# Generated by FakeRAM 2.0
VERSION 5.7 ;
BUSBITCHARS "[]" ;
PROPERTYDEFINITIONS
  MACRO width INTEGER ;
  MACRO depth INTEGER ;
  MACRO banks INTEGER ;
END PROPERTYDEFINITIONS
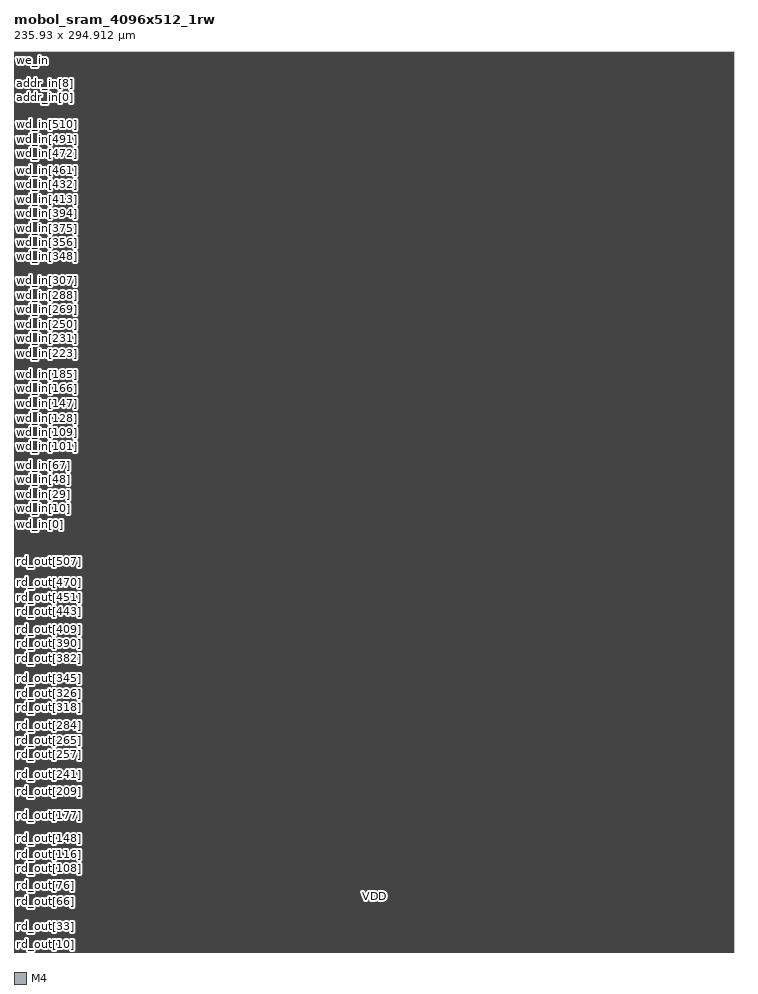
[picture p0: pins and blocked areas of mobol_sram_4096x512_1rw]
MACRO mobol_sram_4096x512_1rw
  PROPERTY width 512 ;
  PROPERTY depth 4096 ;
  PROPERTY banks 4 ;
  FOREIGN mobol_sram_4096x512_1rw 0 0 ;
  SYMMETRY X Y R90 ;
  SIZE 235.930 BY 294.912 ;
  CLASS BLOCK ;
  PIN rd_out[0]
    DIRECTION OUTPUT ;
    USE SIGNAL ;
    SHAPE ABUTMENT ;
    PORT
      LAYER M4 ;
      RECT 0.000 0.035 0.018 0.053 ;
    END
  END rd_out[0]
  PIN rd_out[1]
    DIRECTION OUTPUT ;
    USE SIGNAL ;
    SHAPE ABUTMENT ;
    PORT
      LAYER M4 ;
      RECT 0.000 0.287 0.018 0.305 ;
    END
  END rd_out[1]
  PIN rd_out[2]
    DIRECTION OUTPUT ;
    USE SIGNAL ;
    SHAPE ABUTMENT ;
    PORT
      LAYER M4 ;
      RECT 0.000 0.539 0.018 0.557 ;
    END
  END rd_out[2]
  PIN rd_out[3]
    DIRECTION OUTPUT ;
    USE SIGNAL ;
    SHAPE ABUTMENT ;
    PORT
      LAYER M4 ;
      RECT 0.000 0.791 0.018 0.809 ;
    END
  END rd_out[3]
  PIN rd_out[4]
    DIRECTION OUTPUT ;
    USE SIGNAL ;
    SHAPE ABUTMENT ;
    PORT
      LAYER M4 ;
      RECT 0.000 1.043 0.018 1.061 ;
    END
  END rd_out[4]
  PIN rd_out[5]
    DIRECTION OUTPUT ;
    USE SIGNAL ;
    SHAPE ABUTMENT ;
    PORT
      LAYER M4 ;
      RECT 0.000 1.295 0.018 1.313 ;
    END
  END rd_out[5]
  PIN rd_out[6]
    DIRECTION OUTPUT ;
    USE SIGNAL ;
    SHAPE ABUTMENT ;
    PORT
      LAYER M4 ;
      RECT 0.000 1.547 0.018 1.565 ;
    END
  END rd_out[6]
  PIN rd_out[7]
    DIRECTION OUTPUT ;
    USE SIGNAL ;
    SHAPE ABUTMENT ;
    PORT
      LAYER M4 ;
      RECT 0.000 1.799 0.018 1.817 ;
    END
  END rd_out[7]
  PIN rd_out[8]
    DIRECTION OUTPUT ;
    USE SIGNAL ;
    SHAPE ABUTMENT ;
    PORT
      LAYER M4 ;
      RECT 0.000 2.051 0.018 2.069 ;
    END
  END rd_out[8]
  PIN rd_out[9]
    DIRECTION OUTPUT ;
    USE SIGNAL ;
    SHAPE ABUTMENT ;
    PORT
      LAYER M4 ;
      RECT 0.000 2.303 0.018 2.321 ;
    END
  END rd_out[9]
  PIN rd_out[10]
    DIRECTION OUTPUT ;
    USE SIGNAL ;
    SHAPE ABUTMENT ;
    PORT
      LAYER M4 ;
      RECT 0.000 2.555 0.018 2.573 ;
    END
  END rd_out[10]
  PIN rd_out[11]
    DIRECTION OUTPUT ;
    USE SIGNAL ;
    SHAPE ABUTMENT ;
    PORT
      LAYER M4 ;
      RECT 0.000 2.807 0.018 2.825 ;
    END
  END rd_out[11]
  PIN rd_out[12]
    DIRECTION OUTPUT ;
    USE SIGNAL ;
    SHAPE ABUTMENT ;
    PORT
      LAYER M4 ;
      RECT 0.000 3.059 0.018 3.077 ;
    END
  END rd_out[12]
  PIN rd_out[13]
    DIRECTION OUTPUT ;
    USE SIGNAL ;
    SHAPE ABUTMENT ;
    PORT
      LAYER M4 ;
      RECT 0.000 3.311 0.018 3.329 ;
    END
  END rd_out[13]
  PIN rd_out[14]
    DIRECTION OUTPUT ;
    USE SIGNAL ;
    SHAPE ABUTMENT ;
    PORT
      LAYER M4 ;
      RECT 0.000 3.563 0.018 3.581 ;
    END
  END rd_out[14]
  PIN rd_out[15]
    DIRECTION OUTPUT ;
    USE SIGNAL ;
    SHAPE ABUTMENT ;
    PORT
      LAYER M4 ;
      RECT 0.000 3.815 0.018 3.833 ;
    END
  END rd_out[15]
  PIN rd_out[16]
    DIRECTION OUTPUT ;
    USE SIGNAL ;
    SHAPE ABUTMENT ;
    PORT
      LAYER M4 ;
      RECT 0.000 4.067 0.018 4.085 ;
    END
  END rd_out[16]
  PIN rd_out[17]
    DIRECTION OUTPUT ;
    USE SIGNAL ;
    SHAPE ABUTMENT ;
    PORT
      LAYER M4 ;
      RECT 0.000 4.319 0.018 4.337 ;
    END
  END rd_out[17]
  PIN rd_out[18]
    DIRECTION OUTPUT ;
    USE SIGNAL ;
    SHAPE ABUTMENT ;
    PORT
      LAYER M4 ;
      RECT 0.000 4.571 0.018 4.589 ;
    END
  END rd_out[18]
  PIN rd_out[19]
    DIRECTION OUTPUT ;
    USE SIGNAL ;
    SHAPE ABUTMENT ;
    PORT
      LAYER M4 ;
      RECT 0.000 4.823 0.018 4.841 ;
    END
  END rd_out[19]
  PIN rd_out[20]
    DIRECTION OUTPUT ;
    USE SIGNAL ;
    SHAPE ABUTMENT ;
    PORT
      LAYER M4 ;
      RECT 0.000 5.075 0.018 5.093 ;
    END
  END rd_out[20]
  PIN rd_out[21]
    DIRECTION OUTPUT ;
    USE SIGNAL ;
    SHAPE ABUTMENT ;
    PORT
      LAYER M4 ;
      RECT 0.000 5.327 0.018 5.345 ;
    END
  END rd_out[21]
  PIN rd_out[22]
    DIRECTION OUTPUT ;
    USE SIGNAL ;
    SHAPE ABUTMENT ;
    PORT
      LAYER M4 ;
      RECT 0.000 5.579 0.018 5.597 ;
    END
  END rd_out[22]
  PIN rd_out[23]
    DIRECTION OUTPUT ;
    USE SIGNAL ;
    SHAPE ABUTMENT ;
    PORT
      LAYER M4 ;
      RECT 0.000 5.831 0.018 5.849 ;
    END
  END rd_out[23]
  PIN rd_out[24]
    DIRECTION OUTPUT ;
    USE SIGNAL ;
    SHAPE ABUTMENT ;
    PORT
      LAYER M4 ;
      RECT 0.000 6.083 0.018 6.101 ;
    END
  END rd_out[24]
  PIN rd_out[25]
    DIRECTION OUTPUT ;
    USE SIGNAL ;
    SHAPE ABUTMENT ;
    PORT
      LAYER M4 ;
      RECT 0.000 6.335 0.018 6.353 ;
    END
  END rd_out[25]
  PIN rd_out[26]
    DIRECTION OUTPUT ;
    USE SIGNAL ;
    SHAPE ABUTMENT ;
    PORT
      LAYER M4 ;
      RECT 0.000 6.587 0.018 6.605 ;
    END
  END rd_out[26]
  PIN rd_out[27]
    DIRECTION OUTPUT ;
    USE SIGNAL ;
    SHAPE ABUTMENT ;
    PORT
      LAYER M4 ;
      RECT 0.000 6.839 0.018 6.857 ;
    END
  END rd_out[27]
  PIN rd_out[28]
    DIRECTION OUTPUT ;
    USE SIGNAL ;
    SHAPE ABUTMENT ;
    PORT
      LAYER M4 ;
      RECT 0.000 7.091 0.018 7.109 ;
    END
  END rd_out[28]
  PIN rd_out[29]
    DIRECTION OUTPUT ;
    USE SIGNAL ;
    SHAPE ABUTMENT ;
    PORT
      LAYER M4 ;
      RECT 0.000 7.343 0.018 7.361 ;
    END
  END rd_out[29]
  PIN rd_out[30]
    DIRECTION OUTPUT ;
    USE SIGNAL ;
    SHAPE ABUTMENT ;
    PORT
      LAYER M4 ;
      RECT 0.000 7.595 0.018 7.613 ;
    END
  END rd_out[30]
  PIN rd_out[31]
    DIRECTION OUTPUT ;
    USE SIGNAL ;
    SHAPE ABUTMENT ;
    PORT
      LAYER M4 ;
      RECT 0.000 7.847 0.018 7.865 ;
    END
  END rd_out[31]
  PIN rd_out[32]
    DIRECTION OUTPUT ;
    USE SIGNAL ;
    SHAPE ABUTMENT ;
    PORT
      LAYER M4 ;
      RECT 0.000 8.099 0.018 8.117 ;
    END
  END rd_out[32]
  PIN rd_out[33]
    DIRECTION OUTPUT ;
    USE SIGNAL ;
    SHAPE ABUTMENT ;
    PORT
      LAYER M4 ;
      RECT 0.000 8.351 0.018 8.369 ;
    END
  END rd_out[33]
  PIN rd_out[34]
    DIRECTION OUTPUT ;
    USE SIGNAL ;
    SHAPE ABUTMENT ;
    PORT
      LAYER M4 ;
      RECT 0.000 8.603 0.018 8.621 ;
    END
  END rd_out[34]
  PIN rd_out[35]
    DIRECTION OUTPUT ;
    USE SIGNAL ;
    SHAPE ABUTMENT ;
    PORT
      LAYER M4 ;
      RECT 0.000 8.855 0.018 8.873 ;
    END
  END rd_out[35]
  PIN rd_out[36]
    DIRECTION OUTPUT ;
    USE SIGNAL ;
    SHAPE ABUTMENT ;
    PORT
      LAYER M4 ;
      RECT 0.000 9.107 0.018 9.125 ;
    END
  END rd_out[36]
  PIN rd_out[37]
    DIRECTION OUTPUT ;
    USE SIGNAL ;
    SHAPE ABUTMENT ;
    PORT
      LAYER M4 ;
      RECT 0.000 9.359 0.018 9.377 ;
    END
  END rd_out[37]
  PIN rd_out[38]
    DIRECTION OUTPUT ;
    USE SIGNAL ;
    SHAPE ABUTMENT ;
    PORT
      LAYER M4 ;
      RECT 0.000 9.611 0.018 9.629 ;
    END
  END rd_out[38]
  PIN rd_out[39]
    DIRECTION OUTPUT ;
    USE SIGNAL ;
    SHAPE ABUTMENT ;
    PORT
      LAYER M4 ;
      RECT 0.000 9.863 0.018 9.881 ;
    END
  END rd_out[39]
  PIN rd_out[40]
    DIRECTION OUTPUT ;
    USE SIGNAL ;
    SHAPE ABUTMENT ;
    PORT
      LAYER M4 ;
      RECT 0.000 10.115 0.018 10.133 ;
    END
  END rd_out[40]
  PIN rd_out[41]
    DIRECTION OUTPUT ;
    USE SIGNAL ;
    SHAPE ABUTMENT ;
    PORT
      LAYER M4 ;
      RECT 0.000 10.367 0.018 10.385 ;
    END
  END rd_out[41]
  PIN rd_out[42]
    DIRECTION OUTPUT ;
    USE SIGNAL ;
    SHAPE ABUTMENT ;
    PORT
      LAYER M4 ;
      RECT 0.000 10.619 0.018 10.637 ;
    END
  END rd_out[42]
  PIN rd_out[43]
    DIRECTION OUTPUT ;
    USE SIGNAL ;
    SHAPE ABUTMENT ;
    PORT
      LAYER M4 ;
      RECT 0.000 10.871 0.018 10.889 ;
    END
  END rd_out[43]
  PIN rd_out[44]
    DIRECTION OUTPUT ;
    USE SIGNAL ;
    SHAPE ABUTMENT ;
    PORT
      LAYER M4 ;
      RECT 0.000 11.123 0.018 11.141 ;
    END
  END rd_out[44]
  PIN rd_out[45]
    DIRECTION OUTPUT ;
    USE SIGNAL ;
    SHAPE ABUTMENT ;
    PORT
      LAYER M4 ;
      RECT 0.000 11.375 0.018 11.393 ;
    END
  END rd_out[45]
  PIN rd_out[46]
    DIRECTION OUTPUT ;
    USE SIGNAL ;
    SHAPE ABUTMENT ;
    PORT
      LAYER M4 ;
      RECT 0.000 11.627 0.018 11.645 ;
    END
  END rd_out[46]
  PIN rd_out[47]
    DIRECTION OUTPUT ;
    USE SIGNAL ;
    SHAPE ABUTMENT ;
    PORT
      LAYER M4 ;
      RECT 0.000 11.879 0.018 11.897 ;
    END
  END rd_out[47]
  PIN rd_out[48]
    DIRECTION OUTPUT ;
    USE SIGNAL ;
    SHAPE ABUTMENT ;
    PORT
      LAYER M4 ;
      RECT 0.000 12.131 0.018 12.149 ;
    END
  END rd_out[48]
  PIN rd_out[49]
    DIRECTION OUTPUT ;
    USE SIGNAL ;
    SHAPE ABUTMENT ;
    PORT
      LAYER M4 ;
      RECT 0.000 12.383 0.018 12.401 ;
    END
  END rd_out[49]
  PIN rd_out[50]
    DIRECTION OUTPUT ;
    USE SIGNAL ;
    SHAPE ABUTMENT ;
    PORT
      LAYER M4 ;
      RECT 0.000 12.635 0.018 12.653 ;
    END
  END rd_out[50]
  PIN rd_out[51]
    DIRECTION OUTPUT ;
    USE SIGNAL ;
    SHAPE ABUTMENT ;
    PORT
      LAYER M4 ;
      RECT 0.000 12.887 0.018 12.905 ;
    END
  END rd_out[51]
  PIN rd_out[52]
    DIRECTION OUTPUT ;
    USE SIGNAL ;
    SHAPE ABUTMENT ;
    PORT
      LAYER M4 ;
      RECT 0.000 13.139 0.018 13.157 ;
    END
  END rd_out[52]
  PIN rd_out[53]
    DIRECTION OUTPUT ;
    USE SIGNAL ;
    SHAPE ABUTMENT ;
    PORT
      LAYER M4 ;
      RECT 0.000 13.391 0.018 13.409 ;
    END
  END rd_out[53]
  PIN rd_out[54]
    DIRECTION OUTPUT ;
    USE SIGNAL ;
    SHAPE ABUTMENT ;
    PORT
      LAYER M4 ;
      RECT 0.000 13.643 0.018 13.661 ;
    END
  END rd_out[54]
  PIN rd_out[55]
    DIRECTION OUTPUT ;
    USE SIGNAL ;
    SHAPE ABUTMENT ;
    PORT
      LAYER M4 ;
      RECT 0.000 13.895 0.018 13.913 ;
    END
  END rd_out[55]
  PIN rd_out[56]
    DIRECTION OUTPUT ;
    USE SIGNAL ;
    SHAPE ABUTMENT ;
    PORT
      LAYER M4 ;
      RECT 0.000 14.147 0.018 14.165 ;
    END
  END rd_out[56]
  PIN rd_out[57]
    DIRECTION OUTPUT ;
    USE SIGNAL ;
    SHAPE ABUTMENT ;
    PORT
      LAYER M4 ;
      RECT 0.000 14.399 0.018 14.417 ;
    END
  END rd_out[57]
  PIN rd_out[58]
    DIRECTION OUTPUT ;
    USE SIGNAL ;
    SHAPE ABUTMENT ;
    PORT
      LAYER M4 ;
      RECT 0.000 14.651 0.018 14.669 ;
    END
  END rd_out[58]
  PIN rd_out[59]
    DIRECTION OUTPUT ;
    USE SIGNAL ;
    SHAPE ABUTMENT ;
    PORT
      LAYER M4 ;
      RECT 0.000 14.903 0.018 14.921 ;
    END
  END rd_out[59]
  PIN rd_out[60]
    DIRECTION OUTPUT ;
    USE SIGNAL ;
    SHAPE ABUTMENT ;
    PORT
      LAYER M4 ;
      RECT 0.000 15.155 0.018 15.173 ;
    END
  END rd_out[60]
  PIN rd_out[61]
    DIRECTION OUTPUT ;
    USE SIGNAL ;
    SHAPE ABUTMENT ;
    PORT
      LAYER M4 ;
      RECT 0.000 15.407 0.018 15.425 ;
    END
  END rd_out[61]
  PIN rd_out[62]
    DIRECTION OUTPUT ;
    USE SIGNAL ;
    SHAPE ABUTMENT ;
    PORT
      LAYER M4 ;
      RECT 0.000 15.659 0.018 15.677 ;
    END
  END rd_out[62]
  PIN rd_out[63]
    DIRECTION OUTPUT ;
    USE SIGNAL ;
    SHAPE ABUTMENT ;
    PORT
      LAYER M4 ;
      RECT 0.000 15.911 0.018 15.929 ;
    END
  END rd_out[63]
  PIN rd_out[64]
    DIRECTION OUTPUT ;
    USE SIGNAL ;
    SHAPE ABUTMENT ;
    PORT
      LAYER M4 ;
      RECT 0.000 16.163 0.018 16.181 ;
    END
  END rd_out[64]
  PIN rd_out[65]
    DIRECTION OUTPUT ;
    USE SIGNAL ;
    SHAPE ABUTMENT ;
    PORT
      LAYER M4 ;
      RECT 0.000 16.415 0.018 16.433 ;
    END
  END rd_out[65]
  PIN rd_out[66]
    DIRECTION OUTPUT ;
    USE SIGNAL ;
    SHAPE ABUTMENT ;
    PORT
      LAYER M4 ;
      RECT 0.000 16.667 0.018 16.685 ;
    END
  END rd_out[66]
  PIN rd_out[67]
    DIRECTION OUTPUT ;
    USE SIGNAL ;
    SHAPE ABUTMENT ;
    PORT
      LAYER M4 ;
      RECT 0.000 16.919 0.018 16.937 ;
    END
  END rd_out[67]
  PIN rd_out[68]
    DIRECTION OUTPUT ;
    USE SIGNAL ;
    SHAPE ABUTMENT ;
    PORT
      LAYER M4 ;
      RECT 0.000 17.171 0.018 17.189 ;
    END
  END rd_out[68]
  PIN rd_out[69]
    DIRECTION OUTPUT ;
    USE SIGNAL ;
    SHAPE ABUTMENT ;
    PORT
      LAYER M4 ;
      RECT 0.000 17.423 0.018 17.441 ;
    END
  END rd_out[69]
  PIN rd_out[70]
    DIRECTION OUTPUT ;
    USE SIGNAL ;
    SHAPE ABUTMENT ;
    PORT
      LAYER M4 ;
      RECT 0.000 17.675 0.018 17.693 ;
    END
  END rd_out[70]
  PIN rd_out[71]
    DIRECTION OUTPUT ;
    USE SIGNAL ;
    SHAPE ABUTMENT ;
    PORT
      LAYER M4 ;
      RECT 0.000 17.927 0.018 17.945 ;
    END
  END rd_out[71]
  PIN rd_out[72]
    DIRECTION OUTPUT ;
    USE SIGNAL ;
    SHAPE ABUTMENT ;
    PORT
      LAYER M4 ;
      RECT 0.000 18.179 0.018 18.197 ;
    END
  END rd_out[72]
  PIN rd_out[73]
    DIRECTION OUTPUT ;
    USE SIGNAL ;
    SHAPE ABUTMENT ;
    PORT
      LAYER M4 ;
      RECT 0.000 18.431 0.018 18.449 ;
    END
  END rd_out[73]
  PIN rd_out[74]
    DIRECTION OUTPUT ;
    USE SIGNAL ;
    SHAPE ABUTMENT ;
    PORT
      LAYER M4 ;
      RECT 0.000 18.683 0.018 18.701 ;
    END
  END rd_out[74]
  PIN rd_out[75]
    DIRECTION OUTPUT ;
    USE SIGNAL ;
    SHAPE ABUTMENT ;
    PORT
      LAYER M4 ;
      RECT 0.000 18.935 0.018 18.953 ;
    END
  END rd_out[75]
  PIN rd_out[76]
    DIRECTION OUTPUT ;
    USE SIGNAL ;
    SHAPE ABUTMENT ;
    PORT
      LAYER M4 ;
      RECT 0.000 19.187 0.018 19.205 ;
    END
  END rd_out[76]
  PIN rd_out[77]
    DIRECTION OUTPUT ;
    USE SIGNAL ;
    SHAPE ABUTMENT ;
    PORT
      LAYER M4 ;
      RECT 0.000 19.439 0.018 19.457 ;
    END
  END rd_out[77]
  PIN rd_out[78]
    DIRECTION OUTPUT ;
    USE SIGNAL ;
    SHAPE ABUTMENT ;
    PORT
      LAYER M4 ;
      RECT 0.000 19.691 0.018 19.709 ;
    END
  END rd_out[78]
  PIN rd_out[79]
    DIRECTION OUTPUT ;
    USE SIGNAL ;
    SHAPE ABUTMENT ;
    PORT
      LAYER M4 ;
      RECT 0.000 19.943 0.018 19.961 ;
    END
  END rd_out[79]
  PIN rd_out[80]
    DIRECTION OUTPUT ;
    USE SIGNAL ;
    SHAPE ABUTMENT ;
    PORT
      LAYER M4 ;
      RECT 0.000 20.195 0.018 20.213 ;
    END
  END rd_out[80]
  PIN rd_out[81]
    DIRECTION OUTPUT ;
    USE SIGNAL ;
    SHAPE ABUTMENT ;
    PORT
      LAYER M4 ;
      RECT 0.000 20.447 0.018 20.465 ;
    END
  END rd_out[81]
  PIN rd_out[82]
    DIRECTION OUTPUT ;
    USE SIGNAL ;
    SHAPE ABUTMENT ;
    PORT
      LAYER M4 ;
      RECT 0.000 20.699 0.018 20.717 ;
    END
  END rd_out[82]
  PIN rd_out[83]
    DIRECTION OUTPUT ;
    USE SIGNAL ;
    SHAPE ABUTMENT ;
    PORT
      LAYER M4 ;
      RECT 0.000 20.951 0.018 20.969 ;
    END
  END rd_out[83]
  PIN rd_out[84]
    DIRECTION OUTPUT ;
    USE SIGNAL ;
    SHAPE ABUTMENT ;
    PORT
      LAYER M4 ;
      RECT 0.000 21.203 0.018 21.221 ;
    END
  END rd_out[84]
  PIN rd_out[85]
    DIRECTION OUTPUT ;
    USE SIGNAL ;
    SHAPE ABUTMENT ;
    PORT
      LAYER M4 ;
      RECT 0.000 21.455 0.018 21.473 ;
    END
  END rd_out[85]
  PIN rd_out[86]
    DIRECTION OUTPUT ;
    USE SIGNAL ;
    SHAPE ABUTMENT ;
    PORT
      LAYER M4 ;
      RECT 0.000 21.707 0.018 21.725 ;
    END
  END rd_out[86]
  PIN rd_out[87]
    DIRECTION OUTPUT ;
    USE SIGNAL ;
    SHAPE ABUTMENT ;
    PORT
      LAYER M4 ;
      RECT 0.000 21.959 0.018 21.977 ;
    END
  END rd_out[87]
  PIN rd_out[88]
    DIRECTION OUTPUT ;
    USE SIGNAL ;
    SHAPE ABUTMENT ;
    PORT
      LAYER M4 ;
      RECT 0.000 22.211 0.018 22.229 ;
    END
  END rd_out[88]
  PIN rd_out[89]
    DIRECTION OUTPUT ;
    USE SIGNAL ;
    SHAPE ABUTMENT ;
    PORT
      LAYER M4 ;
      RECT 0.000 22.463 0.018 22.481 ;
    END
  END rd_out[89]
  PIN rd_out[90]
    DIRECTION OUTPUT ;
    USE SIGNAL ;
    SHAPE ABUTMENT ;
    PORT
      LAYER M4 ;
      RECT 0.000 22.715 0.018 22.733 ;
    END
  END rd_out[90]
  PIN rd_out[91]
    DIRECTION OUTPUT ;
    USE SIGNAL ;
    SHAPE ABUTMENT ;
    PORT
      LAYER M4 ;
      RECT 0.000 22.967 0.018 22.985 ;
    END
  END rd_out[91]
  PIN rd_out[92]
    DIRECTION OUTPUT ;
    USE SIGNAL ;
    SHAPE ABUTMENT ;
    PORT
      LAYER M4 ;
      RECT 0.000 23.219 0.018 23.237 ;
    END
  END rd_out[92]
  PIN rd_out[93]
    DIRECTION OUTPUT ;
    USE SIGNAL ;
    SHAPE ABUTMENT ;
    PORT
      LAYER M4 ;
      RECT 0.000 23.471 0.018 23.489 ;
    END
  END rd_out[93]
  PIN rd_out[94]
    DIRECTION OUTPUT ;
    USE SIGNAL ;
    SHAPE ABUTMENT ;
    PORT
      LAYER M4 ;
      RECT 0.000 23.723 0.018 23.741 ;
    END
  END rd_out[94]
  PIN rd_out[95]
    DIRECTION OUTPUT ;
    USE SIGNAL ;
    SHAPE ABUTMENT ;
    PORT
      LAYER M4 ;
      RECT 0.000 23.975 0.018 23.993 ;
    END
  END rd_out[95]
  PIN rd_out[96]
    DIRECTION OUTPUT ;
    USE SIGNAL ;
    SHAPE ABUTMENT ;
    PORT
      LAYER M4 ;
      RECT 0.000 24.227 0.018 24.245 ;
    END
  END rd_out[96]
  PIN rd_out[97]
    DIRECTION OUTPUT ;
    USE SIGNAL ;
    SHAPE ABUTMENT ;
    PORT
      LAYER M4 ;
      RECT 0.000 24.479 0.018 24.497 ;
    END
  END rd_out[97]
  PIN rd_out[98]
    DIRECTION OUTPUT ;
    USE SIGNAL ;
    SHAPE ABUTMENT ;
    PORT
      LAYER M4 ;
      RECT 0.000 24.731 0.018 24.749 ;
    END
  END rd_out[98]
  PIN rd_out[99]
    DIRECTION OUTPUT ;
    USE SIGNAL ;
    SHAPE ABUTMENT ;
    PORT
      LAYER M4 ;
      RECT 0.000 24.983 0.018 25.001 ;
    END
  END rd_out[99]
  PIN rd_out[100]
    DIRECTION OUTPUT ;
    USE SIGNAL ;
    SHAPE ABUTMENT ;
    PORT
      LAYER M4 ;
      RECT 0.000 25.235 0.018 25.253 ;
    END
  END rd_out[100]
  PIN rd_out[101]
    DIRECTION OUTPUT ;
    USE SIGNAL ;
    SHAPE ABUTMENT ;
    PORT
      LAYER M4 ;
      RECT 0.000 25.487 0.018 25.505 ;
    END
  END rd_out[101]
  PIN rd_out[102]
    DIRECTION OUTPUT ;
    USE SIGNAL ;
    SHAPE ABUTMENT ;
    PORT
      LAYER M4 ;
      RECT 0.000 25.739 0.018 25.757 ;
    END
  END rd_out[102]
  PIN rd_out[103]
    DIRECTION OUTPUT ;
    USE SIGNAL ;
    SHAPE ABUTMENT ;
    PORT
      LAYER M4 ;
      RECT 0.000 25.991 0.018 26.009 ;
    END
  END rd_out[103]
  PIN rd_out[104]
    DIRECTION OUTPUT ;
    USE SIGNAL ;
    SHAPE ABUTMENT ;
    PORT
      LAYER M4 ;
      RECT 0.000 26.243 0.018 26.261 ;
    END
  END rd_out[104]
  PIN rd_out[105]
    DIRECTION OUTPUT ;
    USE SIGNAL ;
    SHAPE ABUTMENT ;
    PORT
      LAYER M4 ;
      RECT 0.000 26.495 0.018 26.513 ;
    END
  END rd_out[105]
  PIN rd_out[106]
    DIRECTION OUTPUT ;
    USE SIGNAL ;
    SHAPE ABUTMENT ;
    PORT
      LAYER M4 ;
      RECT 0.000 26.747 0.018 26.765 ;
    END
  END rd_out[106]
  PIN rd_out[107]
    DIRECTION OUTPUT ;
    USE SIGNAL ;
    SHAPE ABUTMENT ;
    PORT
      LAYER M4 ;
      RECT 0.000 26.999 0.018 27.017 ;
    END
  END rd_out[107]
  PIN rd_out[108]
    DIRECTION OUTPUT ;
    USE SIGNAL ;
    SHAPE ABUTMENT ;
    PORT
      LAYER M4 ;
      RECT 0.000 27.251 0.018 27.269 ;
    END
  END rd_out[108]
  PIN rd_out[109]
    DIRECTION OUTPUT ;
    USE SIGNAL ;
    SHAPE ABUTMENT ;
    PORT
      LAYER M4 ;
      RECT 0.000 27.503 0.018 27.521 ;
    END
  END rd_out[109]
  PIN rd_out[110]
    DIRECTION OUTPUT ;
    USE SIGNAL ;
    SHAPE ABUTMENT ;
    PORT
      LAYER M4 ;
      RECT 0.000 27.755 0.018 27.773 ;
    END
  END rd_out[110]
  PIN rd_out[111]
    DIRECTION OUTPUT ;
    USE SIGNAL ;
    SHAPE ABUTMENT ;
    PORT
      LAYER M4 ;
      RECT 0.000 28.007 0.018 28.025 ;
    END
  END rd_out[111]
  PIN rd_out[112]
    DIRECTION OUTPUT ;
    USE SIGNAL ;
    SHAPE ABUTMENT ;
    PORT
      LAYER M4 ;
      RECT 0.000 28.259 0.018 28.277 ;
    END
  END rd_out[112]
  PIN rd_out[113]
    DIRECTION OUTPUT ;
    USE SIGNAL ;
    SHAPE ABUTMENT ;
    PORT
      LAYER M4 ;
      RECT 0.000 28.511 0.018 28.529 ;
    END
  END rd_out[113]
  PIN rd_out[114]
    DIRECTION OUTPUT ;
    USE SIGNAL ;
    SHAPE ABUTMENT ;
    PORT
      LAYER M4 ;
      RECT 0.000 28.763 0.018 28.781 ;
    END
  END rd_out[114]
  PIN rd_out[115]
    DIRECTION OUTPUT ;
    USE SIGNAL ;
    SHAPE ABUTMENT ;
    PORT
      LAYER M4 ;
      RECT 0.000 29.015 0.018 29.033 ;
    END
  END rd_out[115]
  PIN rd_out[116]
    DIRECTION OUTPUT ;
    USE SIGNAL ;
    SHAPE ABUTMENT ;
    PORT
      LAYER M4 ;
      RECT 0.000 29.267 0.018 29.285 ;
    END
  END rd_out[116]
  PIN rd_out[117]
    DIRECTION OUTPUT ;
    USE SIGNAL ;
    SHAPE ABUTMENT ;
    PORT
      LAYER M4 ;
      RECT 0.000 29.519 0.018 29.537 ;
    END
  END rd_out[117]
  PIN rd_out[118]
    DIRECTION OUTPUT ;
    USE SIGNAL ;
    SHAPE ABUTMENT ;
    PORT
      LAYER M4 ;
      RECT 0.000 29.771 0.018 29.789 ;
    END
  END rd_out[118]
  PIN rd_out[119]
    DIRECTION OUTPUT ;
    USE SIGNAL ;
    SHAPE ABUTMENT ;
    PORT
      LAYER M4 ;
      RECT 0.000 30.023 0.018 30.041 ;
    END
  END rd_out[119]
  PIN rd_out[120]
    DIRECTION OUTPUT ;
    USE SIGNAL ;
    SHAPE ABUTMENT ;
    PORT
      LAYER M4 ;
      RECT 0.000 30.275 0.018 30.293 ;
    END
  END rd_out[120]
  PIN rd_out[121]
    DIRECTION OUTPUT ;
    USE SIGNAL ;
    SHAPE ABUTMENT ;
    PORT
      LAYER M4 ;
      RECT 0.000 30.527 0.018 30.545 ;
    END
  END rd_out[121]
  PIN rd_out[122]
    DIRECTION OUTPUT ;
    USE SIGNAL ;
    SHAPE ABUTMENT ;
    PORT
      LAYER M4 ;
      RECT 0.000 30.779 0.018 30.797 ;
    END
  END rd_out[122]
  PIN rd_out[123]
    DIRECTION OUTPUT ;
    USE SIGNAL ;
    SHAPE ABUTMENT ;
    PORT
      LAYER M4 ;
      RECT 0.000 31.031 0.018 31.049 ;
    END
  END rd_out[123]
  PIN rd_out[124]
    DIRECTION OUTPUT ;
    USE SIGNAL ;
    SHAPE ABUTMENT ;
    PORT
      LAYER M4 ;
      RECT 0.000 31.283 0.018 31.301 ;
    END
  END rd_out[124]
  PIN rd_out[125]
    DIRECTION OUTPUT ;
    USE SIGNAL ;
    SHAPE ABUTMENT ;
    PORT
      LAYER M4 ;
      RECT 0.000 31.535 0.018 31.553 ;
    END
  END rd_out[125]
  PIN rd_out[126]
    DIRECTION OUTPUT ;
    USE SIGNAL ;
    SHAPE ABUTMENT ;
    PORT
      LAYER M4 ;
      RECT 0.000 31.787 0.018 31.805 ;
    END
  END rd_out[126]
  PIN rd_out[127]
    DIRECTION OUTPUT ;
    USE SIGNAL ;
    SHAPE ABUTMENT ;
    PORT
      LAYER M4 ;
      RECT 0.000 32.039 0.018 32.057 ;
    END
  END rd_out[127]
  PIN rd_out[128]
    DIRECTION OUTPUT ;
    USE SIGNAL ;
    SHAPE ABUTMENT ;
    PORT
      LAYER M4 ;
      RECT 0.000 32.291 0.018 32.309 ;
    END
  END rd_out[128]
  PIN rd_out[129]
    DIRECTION OUTPUT ;
    USE SIGNAL ;
    SHAPE ABUTMENT ;
    PORT
      LAYER M4 ;
      RECT 0.000 32.543 0.018 32.561 ;
    END
  END rd_out[129]
  PIN rd_out[130]
    DIRECTION OUTPUT ;
    USE SIGNAL ;
    SHAPE ABUTMENT ;
    PORT
      LAYER M4 ;
      RECT 0.000 32.795 0.018 32.813 ;
    END
  END rd_out[130]
  PIN rd_out[131]
    DIRECTION OUTPUT ;
    USE SIGNAL ;
    SHAPE ABUTMENT ;
    PORT
      LAYER M4 ;
      RECT 0.000 33.047 0.018 33.065 ;
    END
  END rd_out[131]
  PIN rd_out[132]
    DIRECTION OUTPUT ;
    USE SIGNAL ;
    SHAPE ABUTMENT ;
    PORT
      LAYER M4 ;
      RECT 0.000 33.299 0.018 33.317 ;
    END
  END rd_out[132]
  PIN rd_out[133]
    DIRECTION OUTPUT ;
    USE SIGNAL ;
    SHAPE ABUTMENT ;
    PORT
      LAYER M4 ;
      RECT 0.000 33.551 0.018 33.569 ;
    END
  END rd_out[133]
  PIN rd_out[134]
    DIRECTION OUTPUT ;
    USE SIGNAL ;
    SHAPE ABUTMENT ;
    PORT
      LAYER M4 ;
      RECT 0.000 33.803 0.018 33.821 ;
    END
  END rd_out[134]
  PIN rd_out[135]
    DIRECTION OUTPUT ;
    USE SIGNAL ;
    SHAPE ABUTMENT ;
    PORT
      LAYER M4 ;
      RECT 0.000 34.055 0.018 34.073 ;
    END
  END rd_out[135]
  PIN rd_out[136]
    DIRECTION OUTPUT ;
    USE SIGNAL ;
    SHAPE ABUTMENT ;
    PORT
      LAYER M4 ;
      RECT 0.000 34.307 0.018 34.325 ;
    END
  END rd_out[136]
  PIN rd_out[137]
    DIRECTION OUTPUT ;
    USE SIGNAL ;
    SHAPE ABUTMENT ;
    PORT
      LAYER M4 ;
      RECT 0.000 34.559 0.018 34.577 ;
    END
  END rd_out[137]
  PIN rd_out[138]
    DIRECTION OUTPUT ;
    USE SIGNAL ;
    SHAPE ABUTMENT ;
    PORT
      LAYER M4 ;
      RECT 0.000 34.811 0.018 34.829 ;
    END
  END rd_out[138]
  PIN rd_out[139]
    DIRECTION OUTPUT ;
    USE SIGNAL ;
    SHAPE ABUTMENT ;
    PORT
      LAYER M4 ;
      RECT 0.000 35.063 0.018 35.081 ;
    END
  END rd_out[139]
  PIN rd_out[140]
    DIRECTION OUTPUT ;
    USE SIGNAL ;
    SHAPE ABUTMENT ;
    PORT
      LAYER M4 ;
      RECT 0.000 35.315 0.018 35.333 ;
    END
  END rd_out[140]
  PIN rd_out[141]
    DIRECTION OUTPUT ;
    USE SIGNAL ;
    SHAPE ABUTMENT ;
    PORT
      LAYER M4 ;
      RECT 0.000 35.567 0.018 35.585 ;
    END
  END rd_out[141]
  PIN rd_out[142]
    DIRECTION OUTPUT ;
    USE SIGNAL ;
    SHAPE ABUTMENT ;
    PORT
      LAYER M4 ;
      RECT 0.000 35.819 0.018 35.837 ;
    END
  END rd_out[142]
  PIN rd_out[143]
    DIRECTION OUTPUT ;
    USE SIGNAL ;
    SHAPE ABUTMENT ;
    PORT
      LAYER M4 ;
      RECT 0.000 36.071 0.018 36.089 ;
    END
  END rd_out[143]
  PIN rd_out[144]
    DIRECTION OUTPUT ;
    USE SIGNAL ;
    SHAPE ABUTMENT ;
    PORT
      LAYER M4 ;
      RECT 0.000 36.323 0.018 36.341 ;
    END
  END rd_out[144]
  PIN rd_out[145]
    DIRECTION OUTPUT ;
    USE SIGNAL ;
    SHAPE ABUTMENT ;
    PORT
      LAYER M4 ;
      RECT 0.000 36.575 0.018 36.593 ;
    END
  END rd_out[145]
  PIN rd_out[146]
    DIRECTION OUTPUT ;
    USE SIGNAL ;
    SHAPE ABUTMENT ;
    PORT
      LAYER M4 ;
      RECT 0.000 36.827 0.018 36.845 ;
    END
  END rd_out[146]
  PIN rd_out[147]
    DIRECTION OUTPUT ;
    USE SIGNAL ;
    SHAPE ABUTMENT ;
    PORT
      LAYER M4 ;
      RECT 0.000 37.079 0.018 37.097 ;
    END
  END rd_out[147]
  PIN rd_out[148]
    DIRECTION OUTPUT ;
    USE SIGNAL ;
    SHAPE ABUTMENT ;
    PORT
      LAYER M4 ;
      RECT 0.000 37.331 0.018 37.349 ;
    END
  END rd_out[148]
  PIN rd_out[149]
    DIRECTION OUTPUT ;
    USE SIGNAL ;
    SHAPE ABUTMENT ;
    PORT
      LAYER M4 ;
      RECT 0.000 37.583 0.018 37.601 ;
    END
  END rd_out[149]
  PIN rd_out[150]
    DIRECTION OUTPUT ;
    USE SIGNAL ;
    SHAPE ABUTMENT ;
    PORT
      LAYER M4 ;
      RECT 0.000 37.835 0.018 37.853 ;
    END
  END rd_out[150]
  PIN rd_out[151]
    DIRECTION OUTPUT ;
    USE SIGNAL ;
    SHAPE ABUTMENT ;
    PORT
      LAYER M4 ;
      RECT 0.000 38.087 0.018 38.105 ;
    END
  END rd_out[151]
  PIN rd_out[152]
    DIRECTION OUTPUT ;
    USE SIGNAL ;
    SHAPE ABUTMENT ;
    PORT
      LAYER M4 ;
      RECT 0.000 38.339 0.018 38.357 ;
    END
  END rd_out[152]
  PIN rd_out[153]
    DIRECTION OUTPUT ;
    USE SIGNAL ;
    SHAPE ABUTMENT ;
    PORT
      LAYER M4 ;
      RECT 0.000 38.591 0.018 38.609 ;
    END
  END rd_out[153]
  PIN rd_out[154]
    DIRECTION OUTPUT ;
    USE SIGNAL ;
    SHAPE ABUTMENT ;
    PORT
      LAYER M4 ;
      RECT 0.000 38.843 0.018 38.861 ;
    END
  END rd_out[154]
  PIN rd_out[155]
    DIRECTION OUTPUT ;
    USE SIGNAL ;
    SHAPE ABUTMENT ;
    PORT
      LAYER M4 ;
      RECT 0.000 39.095 0.018 39.113 ;
    END
  END rd_out[155]
  PIN rd_out[156]
    DIRECTION OUTPUT ;
    USE SIGNAL ;
    SHAPE ABUTMENT ;
    PORT
      LAYER M4 ;
      RECT 0.000 39.347 0.018 39.365 ;
    END
  END rd_out[156]
  PIN rd_out[157]
    DIRECTION OUTPUT ;
    USE SIGNAL ;
    SHAPE ABUTMENT ;
    PORT
      LAYER M4 ;
      RECT 0.000 39.599 0.018 39.617 ;
    END
  END rd_out[157]
  PIN rd_out[158]
    DIRECTION OUTPUT ;
    USE SIGNAL ;
    SHAPE ABUTMENT ;
    PORT
      LAYER M4 ;
      RECT 0.000 39.851 0.018 39.869 ;
    END
  END rd_out[158]
  PIN rd_out[159]
    DIRECTION OUTPUT ;
    USE SIGNAL ;
    SHAPE ABUTMENT ;
    PORT
      LAYER M4 ;
      RECT 0.000 40.103 0.018 40.121 ;
    END
  END rd_out[159]
  PIN rd_out[160]
    DIRECTION OUTPUT ;
    USE SIGNAL ;
    SHAPE ABUTMENT ;
    PORT
      LAYER M4 ;
      RECT 0.000 40.355 0.018 40.373 ;
    END
  END rd_out[160]
  PIN rd_out[161]
    DIRECTION OUTPUT ;
    USE SIGNAL ;
    SHAPE ABUTMENT ;
    PORT
      LAYER M4 ;
      RECT 0.000 40.607 0.018 40.625 ;
    END
  END rd_out[161]
  PIN rd_out[162]
    DIRECTION OUTPUT ;
    USE SIGNAL ;
    SHAPE ABUTMENT ;
    PORT
      LAYER M4 ;
      RECT 0.000 40.859 0.018 40.877 ;
    END
  END rd_out[162]
  PIN rd_out[163]
    DIRECTION OUTPUT ;
    USE SIGNAL ;
    SHAPE ABUTMENT ;
    PORT
      LAYER M4 ;
      RECT 0.000 41.111 0.018 41.129 ;
    END
  END rd_out[163]
  PIN rd_out[164]
    DIRECTION OUTPUT ;
    USE SIGNAL ;
    SHAPE ABUTMENT ;
    PORT
      LAYER M4 ;
      RECT 0.000 41.363 0.018 41.381 ;
    END
  END rd_out[164]
  PIN rd_out[165]
    DIRECTION OUTPUT ;
    USE SIGNAL ;
    SHAPE ABUTMENT ;
    PORT
      LAYER M4 ;
      RECT 0.000 41.615 0.018 41.633 ;
    END
  END rd_out[165]
  PIN rd_out[166]
    DIRECTION OUTPUT ;
    USE SIGNAL ;
    SHAPE ABUTMENT ;
    PORT
      LAYER M4 ;
      RECT 0.000 41.867 0.018 41.885 ;
    END
  END rd_out[166]
  PIN rd_out[167]
    DIRECTION OUTPUT ;
    USE SIGNAL ;
    SHAPE ABUTMENT ;
    PORT
      LAYER M4 ;
      RECT 0.000 42.119 0.018 42.137 ;
    END
  END rd_out[167]
  PIN rd_out[168]
    DIRECTION OUTPUT ;
    USE SIGNAL ;
    SHAPE ABUTMENT ;
    PORT
      LAYER M4 ;
      RECT 0.000 42.371 0.018 42.389 ;
    END
  END rd_out[168]
  PIN rd_out[169]
    DIRECTION OUTPUT ;
    USE SIGNAL ;
    SHAPE ABUTMENT ;
    PORT
      LAYER M4 ;
      RECT 0.000 42.623 0.018 42.641 ;
    END
  END rd_out[169]
  PIN rd_out[170]
    DIRECTION OUTPUT ;
    USE SIGNAL ;
    SHAPE ABUTMENT ;
    PORT
      LAYER M4 ;
      RECT 0.000 42.875 0.018 42.893 ;
    END
  END rd_out[170]
  PIN rd_out[171]
    DIRECTION OUTPUT ;
    USE SIGNAL ;
    SHAPE ABUTMENT ;
    PORT
      LAYER M4 ;
      RECT 0.000 43.127 0.018 43.145 ;
    END
  END rd_out[171]
  PIN rd_out[172]
    DIRECTION OUTPUT ;
    USE SIGNAL ;
    SHAPE ABUTMENT ;
    PORT
      LAYER M4 ;
      RECT 0.000 43.379 0.018 43.397 ;
    END
  END rd_out[172]
  PIN rd_out[173]
    DIRECTION OUTPUT ;
    USE SIGNAL ;
    SHAPE ABUTMENT ;
    PORT
      LAYER M4 ;
      RECT 0.000 43.631 0.018 43.649 ;
    END
  END rd_out[173]
  PIN rd_out[174]
    DIRECTION OUTPUT ;
    USE SIGNAL ;
    SHAPE ABUTMENT ;
    PORT
      LAYER M4 ;
      RECT 0.000 43.883 0.018 43.901 ;
    END
  END rd_out[174]
  PIN rd_out[175]
    DIRECTION OUTPUT ;
    USE SIGNAL ;
    SHAPE ABUTMENT ;
    PORT
      LAYER M4 ;
      RECT 0.000 44.135 0.018 44.153 ;
    END
  END rd_out[175]
  PIN rd_out[176]
    DIRECTION OUTPUT ;
    USE SIGNAL ;
    SHAPE ABUTMENT ;
    PORT
      LAYER M4 ;
      RECT 0.000 44.387 0.018 44.405 ;
    END
  END rd_out[176]
  PIN rd_out[177]
    DIRECTION OUTPUT ;
    USE SIGNAL ;
    SHAPE ABUTMENT ;
    PORT
      LAYER M4 ;
      RECT 0.000 44.639 0.018 44.657 ;
    END
  END rd_out[177]
  PIN rd_out[178]
    DIRECTION OUTPUT ;
    USE SIGNAL ;
    SHAPE ABUTMENT ;
    PORT
      LAYER M4 ;
      RECT 0.000 44.891 0.018 44.909 ;
    END
  END rd_out[178]
  PIN rd_out[179]
    DIRECTION OUTPUT ;
    USE SIGNAL ;
    SHAPE ABUTMENT ;
    PORT
      LAYER M4 ;
      RECT 0.000 45.143 0.018 45.161 ;
    END
  END rd_out[179]
  PIN rd_out[180]
    DIRECTION OUTPUT ;
    USE SIGNAL ;
    SHAPE ABUTMENT ;
    PORT
      LAYER M4 ;
      RECT 0.000 45.395 0.018 45.413 ;
    END
  END rd_out[180]
  PIN rd_out[181]
    DIRECTION OUTPUT ;
    USE SIGNAL ;
    SHAPE ABUTMENT ;
    PORT
      LAYER M4 ;
      RECT 0.000 45.647 0.018 45.665 ;
    END
  END rd_out[181]
  PIN rd_out[182]
    DIRECTION OUTPUT ;
    USE SIGNAL ;
    SHAPE ABUTMENT ;
    PORT
      LAYER M4 ;
      RECT 0.000 45.899 0.018 45.917 ;
    END
  END rd_out[182]
  PIN rd_out[183]
    DIRECTION OUTPUT ;
    USE SIGNAL ;
    SHAPE ABUTMENT ;
    PORT
      LAYER M4 ;
      RECT 0.000 46.151 0.018 46.169 ;
    END
  END rd_out[183]
  PIN rd_out[184]
    DIRECTION OUTPUT ;
    USE SIGNAL ;
    SHAPE ABUTMENT ;
    PORT
      LAYER M4 ;
      RECT 0.000 46.403 0.018 46.421 ;
    END
  END rd_out[184]
  PIN rd_out[185]
    DIRECTION OUTPUT ;
    USE SIGNAL ;
    SHAPE ABUTMENT ;
    PORT
      LAYER M4 ;
      RECT 0.000 46.655 0.018 46.673 ;
    END
  END rd_out[185]
  PIN rd_out[186]
    DIRECTION OUTPUT ;
    USE SIGNAL ;
    SHAPE ABUTMENT ;
    PORT
      LAYER M4 ;
      RECT 0.000 46.907 0.018 46.925 ;
    END
  END rd_out[186]
  PIN rd_out[187]
    DIRECTION OUTPUT ;
    USE SIGNAL ;
    SHAPE ABUTMENT ;
    PORT
      LAYER M4 ;
      RECT 0.000 47.159 0.018 47.177 ;
    END
  END rd_out[187]
  PIN rd_out[188]
    DIRECTION OUTPUT ;
    USE SIGNAL ;
    SHAPE ABUTMENT ;
    PORT
      LAYER M4 ;
      RECT 0.000 47.411 0.018 47.429 ;
    END
  END rd_out[188]
  PIN rd_out[189]
    DIRECTION OUTPUT ;
    USE SIGNAL ;
    SHAPE ABUTMENT ;
    PORT
      LAYER M4 ;
      RECT 0.000 47.663 0.018 47.681 ;
    END
  END rd_out[189]
  PIN rd_out[190]
    DIRECTION OUTPUT ;
    USE SIGNAL ;
    SHAPE ABUTMENT ;
    PORT
      LAYER M4 ;
      RECT 0.000 47.915 0.018 47.933 ;
    END
  END rd_out[190]
  PIN rd_out[191]
    DIRECTION OUTPUT ;
    USE SIGNAL ;
    SHAPE ABUTMENT ;
    PORT
      LAYER M4 ;
      RECT 0.000 48.167 0.018 48.185 ;
    END
  END rd_out[191]
  PIN rd_out[192]
    DIRECTION OUTPUT ;
    USE SIGNAL ;
    SHAPE ABUTMENT ;
    PORT
      LAYER M4 ;
      RECT 0.000 48.419 0.018 48.437 ;
    END
  END rd_out[192]
  PIN rd_out[193]
    DIRECTION OUTPUT ;
    USE SIGNAL ;
    SHAPE ABUTMENT ;
    PORT
      LAYER M4 ;
      RECT 0.000 48.671 0.018 48.689 ;
    END
  END rd_out[193]
  PIN rd_out[194]
    DIRECTION OUTPUT ;
    USE SIGNAL ;
    SHAPE ABUTMENT ;
    PORT
      LAYER M4 ;
      RECT 0.000 48.923 0.018 48.941 ;
    END
  END rd_out[194]
  PIN rd_out[195]
    DIRECTION OUTPUT ;
    USE SIGNAL ;
    SHAPE ABUTMENT ;
    PORT
      LAYER M4 ;
      RECT 0.000 49.175 0.018 49.193 ;
    END
  END rd_out[195]
  PIN rd_out[196]
    DIRECTION OUTPUT ;
    USE SIGNAL ;
    SHAPE ABUTMENT ;
    PORT
      LAYER M4 ;
      RECT 0.000 49.427 0.018 49.445 ;
    END
  END rd_out[196]
  PIN rd_out[197]
    DIRECTION OUTPUT ;
    USE SIGNAL ;
    SHAPE ABUTMENT ;
    PORT
      LAYER M4 ;
      RECT 0.000 49.679 0.018 49.697 ;
    END
  END rd_out[197]
  PIN rd_out[198]
    DIRECTION OUTPUT ;
    USE SIGNAL ;
    SHAPE ABUTMENT ;
    PORT
      LAYER M4 ;
      RECT 0.000 49.931 0.018 49.949 ;
    END
  END rd_out[198]
  PIN rd_out[199]
    DIRECTION OUTPUT ;
    USE SIGNAL ;
    SHAPE ABUTMENT ;
    PORT
      LAYER M4 ;
      RECT 0.000 50.183 0.018 50.201 ;
    END
  END rd_out[199]
  PIN rd_out[200]
    DIRECTION OUTPUT ;
    USE SIGNAL ;
    SHAPE ABUTMENT ;
    PORT
      LAYER M4 ;
      RECT 0.000 50.435 0.018 50.453 ;
    END
  END rd_out[200]
  PIN rd_out[201]
    DIRECTION OUTPUT ;
    USE SIGNAL ;
    SHAPE ABUTMENT ;
    PORT
      LAYER M4 ;
      RECT 0.000 50.687 0.018 50.705 ;
    END
  END rd_out[201]
  PIN rd_out[202]
    DIRECTION OUTPUT ;
    USE SIGNAL ;
    SHAPE ABUTMENT ;
    PORT
      LAYER M4 ;
      RECT 0.000 50.939 0.018 50.957 ;
    END
  END rd_out[202]
  PIN rd_out[203]
    DIRECTION OUTPUT ;
    USE SIGNAL ;
    SHAPE ABUTMENT ;
    PORT
      LAYER M4 ;
      RECT 0.000 51.191 0.018 51.209 ;
    END
  END rd_out[203]
  PIN rd_out[204]
    DIRECTION OUTPUT ;
    USE SIGNAL ;
    SHAPE ABUTMENT ;
    PORT
      LAYER M4 ;
      RECT 0.000 51.443 0.018 51.461 ;
    END
  END rd_out[204]
  PIN rd_out[205]
    DIRECTION OUTPUT ;
    USE SIGNAL ;
    SHAPE ABUTMENT ;
    PORT
      LAYER M4 ;
      RECT 0.000 51.695 0.018 51.713 ;
    END
  END rd_out[205]
  PIN rd_out[206]
    DIRECTION OUTPUT ;
    USE SIGNAL ;
    SHAPE ABUTMENT ;
    PORT
      LAYER M4 ;
      RECT 0.000 51.947 0.018 51.965 ;
    END
  END rd_out[206]
  PIN rd_out[207]
    DIRECTION OUTPUT ;
    USE SIGNAL ;
    SHAPE ABUTMENT ;
    PORT
      LAYER M4 ;
      RECT 0.000 52.199 0.018 52.217 ;
    END
  END rd_out[207]
  PIN rd_out[208]
    DIRECTION OUTPUT ;
    USE SIGNAL ;
    SHAPE ABUTMENT ;
    PORT
      LAYER M4 ;
      RECT 0.000 52.451 0.018 52.469 ;
    END
  END rd_out[208]
  PIN rd_out[209]
    DIRECTION OUTPUT ;
    USE SIGNAL ;
    SHAPE ABUTMENT ;
    PORT
      LAYER M4 ;
      RECT 0.000 52.703 0.018 52.721 ;
    END
  END rd_out[209]
  PIN rd_out[210]
    DIRECTION OUTPUT ;
    USE SIGNAL ;
    SHAPE ABUTMENT ;
    PORT
      LAYER M4 ;
      RECT 0.000 52.955 0.018 52.973 ;
    END
  END rd_out[210]
  PIN rd_out[211]
    DIRECTION OUTPUT ;
    USE SIGNAL ;
    SHAPE ABUTMENT ;
    PORT
      LAYER M4 ;
      RECT 0.000 53.207 0.018 53.225 ;
    END
  END rd_out[211]
  PIN rd_out[212]
    DIRECTION OUTPUT ;
    USE SIGNAL ;
    SHAPE ABUTMENT ;
    PORT
      LAYER M4 ;
      RECT 0.000 53.459 0.018 53.477 ;
    END
  END rd_out[212]
  PIN rd_out[213]
    DIRECTION OUTPUT ;
    USE SIGNAL ;
    SHAPE ABUTMENT ;
    PORT
      LAYER M4 ;
      RECT 0.000 53.711 0.018 53.729 ;
    END
  END rd_out[213]
  PIN rd_out[214]
    DIRECTION OUTPUT ;
    USE SIGNAL ;
    SHAPE ABUTMENT ;
    PORT
      LAYER M4 ;
      RECT 0.000 53.963 0.018 53.981 ;
    END
  END rd_out[214]
  PIN rd_out[215]
    DIRECTION OUTPUT ;
    USE SIGNAL ;
    SHAPE ABUTMENT ;
    PORT
      LAYER M4 ;
      RECT 0.000 54.215 0.018 54.233 ;
    END
  END rd_out[215]
  PIN rd_out[216]
    DIRECTION OUTPUT ;
    USE SIGNAL ;
    SHAPE ABUTMENT ;
    PORT
      LAYER M4 ;
      RECT 0.000 54.467 0.018 54.485 ;
    END
  END rd_out[216]
  PIN rd_out[217]
    DIRECTION OUTPUT ;
    USE SIGNAL ;
    SHAPE ABUTMENT ;
    PORT
      LAYER M4 ;
      RECT 0.000 54.719 0.018 54.737 ;
    END
  END rd_out[217]
  PIN rd_out[218]
    DIRECTION OUTPUT ;
    USE SIGNAL ;
    SHAPE ABUTMENT ;
    PORT
      LAYER M4 ;
      RECT 0.000 54.971 0.018 54.989 ;
    END
  END rd_out[218]
  PIN rd_out[219]
    DIRECTION OUTPUT ;
    USE SIGNAL ;
    SHAPE ABUTMENT ;
    PORT
      LAYER M4 ;
      RECT 0.000 55.223 0.018 55.241 ;
    END
  END rd_out[219]
  PIN rd_out[220]
    DIRECTION OUTPUT ;
    USE SIGNAL ;
    SHAPE ABUTMENT ;
    PORT
      LAYER M4 ;
      RECT 0.000 55.475 0.018 55.493 ;
    END
  END rd_out[220]
  PIN rd_out[221]
    DIRECTION OUTPUT ;
    USE SIGNAL ;
    SHAPE ABUTMENT ;
    PORT
      LAYER M4 ;
      RECT 0.000 55.727 0.018 55.745 ;
    END
  END rd_out[221]
  PIN rd_out[222]
    DIRECTION OUTPUT ;
    USE SIGNAL ;
    SHAPE ABUTMENT ;
    PORT
      LAYER M4 ;
      RECT 0.000 55.979 0.018 55.997 ;
    END
  END rd_out[222]
  PIN rd_out[223]
    DIRECTION OUTPUT ;
    USE SIGNAL ;
    SHAPE ABUTMENT ;
    PORT
      LAYER M4 ;
      RECT 0.000 56.231 0.018 56.249 ;
    END
  END rd_out[223]
  PIN rd_out[224]
    DIRECTION OUTPUT ;
    USE SIGNAL ;
    SHAPE ABUTMENT ;
    PORT
      LAYER M4 ;
      RECT 0.000 56.483 0.018 56.501 ;
    END
  END rd_out[224]
  PIN rd_out[225]
    DIRECTION OUTPUT ;
    USE SIGNAL ;
    SHAPE ABUTMENT ;
    PORT
      LAYER M4 ;
      RECT 0.000 56.735 0.018 56.753 ;
    END
  END rd_out[225]
  PIN rd_out[226]
    DIRECTION OUTPUT ;
    USE SIGNAL ;
    SHAPE ABUTMENT ;
    PORT
      LAYER M4 ;
      RECT 0.000 56.987 0.018 57.005 ;
    END
  END rd_out[226]
  PIN rd_out[227]
    DIRECTION OUTPUT ;
    USE SIGNAL ;
    SHAPE ABUTMENT ;
    PORT
      LAYER M4 ;
      RECT 0.000 57.239 0.018 57.257 ;
    END
  END rd_out[227]
  PIN rd_out[228]
    DIRECTION OUTPUT ;
    USE SIGNAL ;
    SHAPE ABUTMENT ;
    PORT
      LAYER M4 ;
      RECT 0.000 57.491 0.018 57.509 ;
    END
  END rd_out[228]
  PIN rd_out[229]
    DIRECTION OUTPUT ;
    USE SIGNAL ;
    SHAPE ABUTMENT ;
    PORT
      LAYER M4 ;
      RECT 0.000 57.743 0.018 57.761 ;
    END
  END rd_out[229]
  PIN rd_out[230]
    DIRECTION OUTPUT ;
    USE SIGNAL ;
    SHAPE ABUTMENT ;
    PORT
      LAYER M4 ;
      RECT 0.000 57.995 0.018 58.013 ;
    END
  END rd_out[230]
  PIN rd_out[231]
    DIRECTION OUTPUT ;
    USE SIGNAL ;
    SHAPE ABUTMENT ;
    PORT
      LAYER M4 ;
      RECT 0.000 58.247 0.018 58.265 ;
    END
  END rd_out[231]
  PIN rd_out[232]
    DIRECTION OUTPUT ;
    USE SIGNAL ;
    SHAPE ABUTMENT ;
    PORT
      LAYER M4 ;
      RECT 0.000 58.499 0.018 58.517 ;
    END
  END rd_out[232]
  PIN rd_out[233]
    DIRECTION OUTPUT ;
    USE SIGNAL ;
    SHAPE ABUTMENT ;
    PORT
      LAYER M4 ;
      RECT 0.000 58.751 0.018 58.769 ;
    END
  END rd_out[233]
  PIN rd_out[234]
    DIRECTION OUTPUT ;
    USE SIGNAL ;
    SHAPE ABUTMENT ;
    PORT
      LAYER M4 ;
      RECT 0.000 59.003 0.018 59.021 ;
    END
  END rd_out[234]
  PIN rd_out[235]
    DIRECTION OUTPUT ;
    USE SIGNAL ;
    SHAPE ABUTMENT ;
    PORT
      LAYER M4 ;
      RECT 0.000 59.255 0.018 59.273 ;
    END
  END rd_out[235]
  PIN rd_out[236]
    DIRECTION OUTPUT ;
    USE SIGNAL ;
    SHAPE ABUTMENT ;
    PORT
      LAYER M4 ;
      RECT 0.000 59.507 0.018 59.525 ;
    END
  END rd_out[236]
  PIN rd_out[237]
    DIRECTION OUTPUT ;
    USE SIGNAL ;
    SHAPE ABUTMENT ;
    PORT
      LAYER M4 ;
      RECT 0.000 59.759 0.018 59.777 ;
    END
  END rd_out[237]
  PIN rd_out[238]
    DIRECTION OUTPUT ;
    USE SIGNAL ;
    SHAPE ABUTMENT ;
    PORT
      LAYER M4 ;
      RECT 0.000 60.011 0.018 60.029 ;
    END
  END rd_out[238]
  PIN rd_out[239]
    DIRECTION OUTPUT ;
    USE SIGNAL ;
    SHAPE ABUTMENT ;
    PORT
      LAYER M4 ;
      RECT 0.000 60.263 0.018 60.281 ;
    END
  END rd_out[239]
  PIN rd_out[240]
    DIRECTION OUTPUT ;
    USE SIGNAL ;
    SHAPE ABUTMENT ;
    PORT
      LAYER M4 ;
      RECT 0.000 60.515 0.018 60.533 ;
    END
  END rd_out[240]
  PIN rd_out[241]
    DIRECTION OUTPUT ;
    USE SIGNAL ;
    SHAPE ABUTMENT ;
    PORT
      LAYER M4 ;
      RECT 0.000 60.767 0.018 60.785 ;
    END
  END rd_out[241]
  PIN rd_out[242]
    DIRECTION OUTPUT ;
    USE SIGNAL ;
    SHAPE ABUTMENT ;
    PORT
      LAYER M4 ;
      RECT 0.000 61.019 0.018 61.037 ;
    END
  END rd_out[242]
  PIN rd_out[243]
    DIRECTION OUTPUT ;
    USE SIGNAL ;
    SHAPE ABUTMENT ;
    PORT
      LAYER M4 ;
      RECT 0.000 61.271 0.018 61.289 ;
    END
  END rd_out[243]
  PIN rd_out[244]
    DIRECTION OUTPUT ;
    USE SIGNAL ;
    SHAPE ABUTMENT ;
    PORT
      LAYER M4 ;
      RECT 0.000 61.523 0.018 61.541 ;
    END
  END rd_out[244]
  PIN rd_out[245]
    DIRECTION OUTPUT ;
    USE SIGNAL ;
    SHAPE ABUTMENT ;
    PORT
      LAYER M4 ;
      RECT 0.000 61.775 0.018 61.793 ;
    END
  END rd_out[245]
  PIN rd_out[246]
    DIRECTION OUTPUT ;
    USE SIGNAL ;
    SHAPE ABUTMENT ;
    PORT
      LAYER M4 ;
      RECT 0.000 62.027 0.018 62.045 ;
    END
  END rd_out[246]
  PIN rd_out[247]
    DIRECTION OUTPUT ;
    USE SIGNAL ;
    SHAPE ABUTMENT ;
    PORT
      LAYER M4 ;
      RECT 0.000 62.279 0.018 62.297 ;
    END
  END rd_out[247]
  PIN rd_out[248]
    DIRECTION OUTPUT ;
    USE SIGNAL ;
    SHAPE ABUTMENT ;
    PORT
      LAYER M4 ;
      RECT 0.000 62.531 0.018 62.549 ;
    END
  END rd_out[248]
  PIN rd_out[249]
    DIRECTION OUTPUT ;
    USE SIGNAL ;
    SHAPE ABUTMENT ;
    PORT
      LAYER M4 ;
      RECT 0.000 62.783 0.018 62.801 ;
    END
  END rd_out[249]
  PIN rd_out[250]
    DIRECTION OUTPUT ;
    USE SIGNAL ;
    SHAPE ABUTMENT ;
    PORT
      LAYER M4 ;
      RECT 0.000 63.035 0.018 63.053 ;
    END
  END rd_out[250]
  PIN rd_out[251]
    DIRECTION OUTPUT ;
    USE SIGNAL ;
    SHAPE ABUTMENT ;
    PORT
      LAYER M4 ;
      RECT 0.000 63.287 0.018 63.305 ;
    END
  END rd_out[251]
  PIN rd_out[252]
    DIRECTION OUTPUT ;
    USE SIGNAL ;
    SHAPE ABUTMENT ;
    PORT
      LAYER M4 ;
      RECT 0.000 63.539 0.018 63.557 ;
    END
  END rd_out[252]
  PIN rd_out[253]
    DIRECTION OUTPUT ;
    USE SIGNAL ;
    SHAPE ABUTMENT ;
    PORT
      LAYER M4 ;
      RECT 0.000 63.791 0.018 63.809 ;
    END
  END rd_out[253]
  PIN rd_out[254]
    DIRECTION OUTPUT ;
    USE SIGNAL ;
    SHAPE ABUTMENT ;
    PORT
      LAYER M4 ;
      RECT 0.000 64.043 0.018 64.061 ;
    END
  END rd_out[254]
  PIN rd_out[255]
    DIRECTION OUTPUT ;
    USE SIGNAL ;
    SHAPE ABUTMENT ;
    PORT
      LAYER M4 ;
      RECT 0.000 64.295 0.018 64.313 ;
    END
  END rd_out[255]
  PIN rd_out[256]
    DIRECTION OUTPUT ;
    USE SIGNAL ;
    SHAPE ABUTMENT ;
    PORT
      LAYER M4 ;
      RECT 0.000 64.547 0.018 64.565 ;
    END
  END rd_out[256]
  PIN rd_out[257]
    DIRECTION OUTPUT ;
    USE SIGNAL ;
    SHAPE ABUTMENT ;
    PORT
      LAYER M4 ;
      RECT 0.000 64.799 0.018 64.817 ;
    END
  END rd_out[257]
  PIN rd_out[258]
    DIRECTION OUTPUT ;
    USE SIGNAL ;
    SHAPE ABUTMENT ;
    PORT
      LAYER M4 ;
      RECT 0.000 65.051 0.018 65.069 ;
    END
  END rd_out[258]
  PIN rd_out[259]
    DIRECTION OUTPUT ;
    USE SIGNAL ;
    SHAPE ABUTMENT ;
    PORT
      LAYER M4 ;
      RECT 0.000 65.303 0.018 65.321 ;
    END
  END rd_out[259]
  PIN rd_out[260]
    DIRECTION OUTPUT ;
    USE SIGNAL ;
    SHAPE ABUTMENT ;
    PORT
      LAYER M4 ;
      RECT 0.000 65.555 0.018 65.573 ;
    END
  END rd_out[260]
  PIN rd_out[261]
    DIRECTION OUTPUT ;
    USE SIGNAL ;
    SHAPE ABUTMENT ;
    PORT
      LAYER M4 ;
      RECT 0.000 65.807 0.018 65.825 ;
    END
  END rd_out[261]
  PIN rd_out[262]
    DIRECTION OUTPUT ;
    USE SIGNAL ;
    SHAPE ABUTMENT ;
    PORT
      LAYER M4 ;
      RECT 0.000 66.059 0.018 66.077 ;
    END
  END rd_out[262]
  PIN rd_out[263]
    DIRECTION OUTPUT ;
    USE SIGNAL ;
    SHAPE ABUTMENT ;
    PORT
      LAYER M4 ;
      RECT 0.000 66.311 0.018 66.329 ;
    END
  END rd_out[263]
  PIN rd_out[264]
    DIRECTION OUTPUT ;
    USE SIGNAL ;
    SHAPE ABUTMENT ;
    PORT
      LAYER M4 ;
      RECT 0.000 66.563 0.018 66.581 ;
    END
  END rd_out[264]
  PIN rd_out[265]
    DIRECTION OUTPUT ;
    USE SIGNAL ;
    SHAPE ABUTMENT ;
    PORT
      LAYER M4 ;
      RECT 0.000 66.815 0.018 66.833 ;
    END
  END rd_out[265]
  PIN rd_out[266]
    DIRECTION OUTPUT ;
    USE SIGNAL ;
    SHAPE ABUTMENT ;
    PORT
      LAYER M4 ;
      RECT 0.000 67.067 0.018 67.085 ;
    END
  END rd_out[266]
  PIN rd_out[267]
    DIRECTION OUTPUT ;
    USE SIGNAL ;
    SHAPE ABUTMENT ;
    PORT
      LAYER M4 ;
      RECT 0.000 67.319 0.018 67.337 ;
    END
  END rd_out[267]
  PIN rd_out[268]
    DIRECTION OUTPUT ;
    USE SIGNAL ;
    SHAPE ABUTMENT ;
    PORT
      LAYER M4 ;
      RECT 0.000 67.571 0.018 67.589 ;
    END
  END rd_out[268]
  PIN rd_out[269]
    DIRECTION OUTPUT ;
    USE SIGNAL ;
    SHAPE ABUTMENT ;
    PORT
      LAYER M4 ;
      RECT 0.000 67.823 0.018 67.841 ;
    END
  END rd_out[269]
  PIN rd_out[270]
    DIRECTION OUTPUT ;
    USE SIGNAL ;
    SHAPE ABUTMENT ;
    PORT
      LAYER M4 ;
      RECT 0.000 68.075 0.018 68.093 ;
    END
  END rd_out[270]
  PIN rd_out[271]
    DIRECTION OUTPUT ;
    USE SIGNAL ;
    SHAPE ABUTMENT ;
    PORT
      LAYER M4 ;
      RECT 0.000 68.327 0.018 68.345 ;
    END
  END rd_out[271]
  PIN rd_out[272]
    DIRECTION OUTPUT ;
    USE SIGNAL ;
    SHAPE ABUTMENT ;
    PORT
      LAYER M4 ;
      RECT 0.000 68.579 0.018 68.597 ;
    END
  END rd_out[272]
  PIN rd_out[273]
    DIRECTION OUTPUT ;
    USE SIGNAL ;
    SHAPE ABUTMENT ;
    PORT
      LAYER M4 ;
      RECT 0.000 68.831 0.018 68.849 ;
    END
  END rd_out[273]
  PIN rd_out[274]
    DIRECTION OUTPUT ;
    USE SIGNAL ;
    SHAPE ABUTMENT ;
    PORT
      LAYER M4 ;
      RECT 0.000 69.083 0.018 69.101 ;
    END
  END rd_out[274]
  PIN rd_out[275]
    DIRECTION OUTPUT ;
    USE SIGNAL ;
    SHAPE ABUTMENT ;
    PORT
      LAYER M4 ;
      RECT 0.000 69.335 0.018 69.353 ;
    END
  END rd_out[275]
  PIN rd_out[276]
    DIRECTION OUTPUT ;
    USE SIGNAL ;
    SHAPE ABUTMENT ;
    PORT
      LAYER M4 ;
      RECT 0.000 69.587 0.018 69.605 ;
    END
  END rd_out[276]
  PIN rd_out[277]
    DIRECTION OUTPUT ;
    USE SIGNAL ;
    SHAPE ABUTMENT ;
    PORT
      LAYER M4 ;
      RECT 0.000 69.839 0.018 69.857 ;
    END
  END rd_out[277]
  PIN rd_out[278]
    DIRECTION OUTPUT ;
    USE SIGNAL ;
    SHAPE ABUTMENT ;
    PORT
      LAYER M4 ;
      RECT 0.000 70.091 0.018 70.109 ;
    END
  END rd_out[278]
  PIN rd_out[279]
    DIRECTION OUTPUT ;
    USE SIGNAL ;
    SHAPE ABUTMENT ;
    PORT
      LAYER M4 ;
      RECT 0.000 70.343 0.018 70.361 ;
    END
  END rd_out[279]
  PIN rd_out[280]
    DIRECTION OUTPUT ;
    USE SIGNAL ;
    SHAPE ABUTMENT ;
    PORT
      LAYER M4 ;
      RECT 0.000 70.595 0.018 70.613 ;
    END
  END rd_out[280]
  PIN rd_out[281]
    DIRECTION OUTPUT ;
    USE SIGNAL ;
    SHAPE ABUTMENT ;
    PORT
      LAYER M4 ;
      RECT 0.000 70.847 0.018 70.865 ;
    END
  END rd_out[281]
  PIN rd_out[282]
    DIRECTION OUTPUT ;
    USE SIGNAL ;
    SHAPE ABUTMENT ;
    PORT
      LAYER M4 ;
      RECT 0.000 71.099 0.018 71.117 ;
    END
  END rd_out[282]
  PIN rd_out[283]
    DIRECTION OUTPUT ;
    USE SIGNAL ;
    SHAPE ABUTMENT ;
    PORT
      LAYER M4 ;
      RECT 0.000 71.351 0.018 71.369 ;
    END
  END rd_out[283]
  PIN rd_out[284]
    DIRECTION OUTPUT ;
    USE SIGNAL ;
    SHAPE ABUTMENT ;
    PORT
      LAYER M4 ;
      RECT 0.000 71.603 0.018 71.621 ;
    END
  END rd_out[284]
  PIN rd_out[285]
    DIRECTION OUTPUT ;
    USE SIGNAL ;
    SHAPE ABUTMENT ;
    PORT
      LAYER M4 ;
      RECT 0.000 71.855 0.018 71.873 ;
    END
  END rd_out[285]
  PIN rd_out[286]
    DIRECTION OUTPUT ;
    USE SIGNAL ;
    SHAPE ABUTMENT ;
    PORT
      LAYER M4 ;
      RECT 0.000 72.107 0.018 72.125 ;
    END
  END rd_out[286]
  PIN rd_out[287]
    DIRECTION OUTPUT ;
    USE SIGNAL ;
    SHAPE ABUTMENT ;
    PORT
      LAYER M4 ;
      RECT 0.000 72.359 0.018 72.377 ;
    END
  END rd_out[287]
  PIN rd_out[288]
    DIRECTION OUTPUT ;
    USE SIGNAL ;
    SHAPE ABUTMENT ;
    PORT
      LAYER M4 ;
      RECT 0.000 72.611 0.018 72.629 ;
    END
  END rd_out[288]
  PIN rd_out[289]
    DIRECTION OUTPUT ;
    USE SIGNAL ;
    SHAPE ABUTMENT ;
    PORT
      LAYER M4 ;
      RECT 0.000 72.863 0.018 72.881 ;
    END
  END rd_out[289]
  PIN rd_out[290]
    DIRECTION OUTPUT ;
    USE SIGNAL ;
    SHAPE ABUTMENT ;
    PORT
      LAYER M4 ;
      RECT 0.000 73.115 0.018 73.133 ;
    END
  END rd_out[290]
  PIN rd_out[291]
    DIRECTION OUTPUT ;
    USE SIGNAL ;
    SHAPE ABUTMENT ;
    PORT
      LAYER M4 ;
      RECT 0.000 73.367 0.018 73.385 ;
    END
  END rd_out[291]
  PIN rd_out[292]
    DIRECTION OUTPUT ;
    USE SIGNAL ;
    SHAPE ABUTMENT ;
    PORT
      LAYER M4 ;
      RECT 0.000 73.619 0.018 73.637 ;
    END
  END rd_out[292]
  PIN rd_out[293]
    DIRECTION OUTPUT ;
    USE SIGNAL ;
    SHAPE ABUTMENT ;
    PORT
      LAYER M4 ;
      RECT 0.000 73.871 0.018 73.889 ;
    END
  END rd_out[293]
  PIN rd_out[294]
    DIRECTION OUTPUT ;
    USE SIGNAL ;
    SHAPE ABUTMENT ;
    PORT
      LAYER M4 ;
      RECT 0.000 74.123 0.018 74.141 ;
    END
  END rd_out[294]
  PIN rd_out[295]
    DIRECTION OUTPUT ;
    USE SIGNAL ;
    SHAPE ABUTMENT ;
    PORT
      LAYER M4 ;
      RECT 0.000 74.375 0.018 74.393 ;
    END
  END rd_out[295]
  PIN rd_out[296]
    DIRECTION OUTPUT ;
    USE SIGNAL ;
    SHAPE ABUTMENT ;
    PORT
      LAYER M4 ;
      RECT 0.000 74.627 0.018 74.645 ;
    END
  END rd_out[296]
  PIN rd_out[297]
    DIRECTION OUTPUT ;
    USE SIGNAL ;
    SHAPE ABUTMENT ;
    PORT
      LAYER M4 ;
      RECT 0.000 74.879 0.018 74.897 ;
    END
  END rd_out[297]
  PIN rd_out[298]
    DIRECTION OUTPUT ;
    USE SIGNAL ;
    SHAPE ABUTMENT ;
    PORT
      LAYER M4 ;
      RECT 0.000 75.131 0.018 75.149 ;
    END
  END rd_out[298]
  PIN rd_out[299]
    DIRECTION OUTPUT ;
    USE SIGNAL ;
    SHAPE ABUTMENT ;
    PORT
      LAYER M4 ;
      RECT 0.000 75.383 0.018 75.401 ;
    END
  END rd_out[299]
  PIN rd_out[300]
    DIRECTION OUTPUT ;
    USE SIGNAL ;
    SHAPE ABUTMENT ;
    PORT
      LAYER M4 ;
      RECT 0.000 75.635 0.018 75.653 ;
    END
  END rd_out[300]
  PIN rd_out[301]
    DIRECTION OUTPUT ;
    USE SIGNAL ;
    SHAPE ABUTMENT ;
    PORT
      LAYER M4 ;
      RECT 0.000 75.887 0.018 75.905 ;
    END
  END rd_out[301]
  PIN rd_out[302]
    DIRECTION OUTPUT ;
    USE SIGNAL ;
    SHAPE ABUTMENT ;
    PORT
      LAYER M4 ;
      RECT 0.000 76.139 0.018 76.157 ;
    END
  END rd_out[302]
  PIN rd_out[303]
    DIRECTION OUTPUT ;
    USE SIGNAL ;
    SHAPE ABUTMENT ;
    PORT
      LAYER M4 ;
      RECT 0.000 76.391 0.018 76.409 ;
    END
  END rd_out[303]
  PIN rd_out[304]
    DIRECTION OUTPUT ;
    USE SIGNAL ;
    SHAPE ABUTMENT ;
    PORT
      LAYER M4 ;
      RECT 0.000 76.643 0.018 76.661 ;
    END
  END rd_out[304]
  PIN rd_out[305]
    DIRECTION OUTPUT ;
    USE SIGNAL ;
    SHAPE ABUTMENT ;
    PORT
      LAYER M4 ;
      RECT 0.000 76.895 0.018 76.913 ;
    END
  END rd_out[305]
  PIN rd_out[306]
    DIRECTION OUTPUT ;
    USE SIGNAL ;
    SHAPE ABUTMENT ;
    PORT
      LAYER M4 ;
      RECT 0.000 77.147 0.018 77.165 ;
    END
  END rd_out[306]
  PIN rd_out[307]
    DIRECTION OUTPUT ;
    USE SIGNAL ;
    SHAPE ABUTMENT ;
    PORT
      LAYER M4 ;
      RECT 0.000 77.399 0.018 77.417 ;
    END
  END rd_out[307]
  PIN rd_out[308]
    DIRECTION OUTPUT ;
    USE SIGNAL ;
    SHAPE ABUTMENT ;
    PORT
      LAYER M4 ;
      RECT 0.000 77.651 0.018 77.669 ;
    END
  END rd_out[308]
  PIN rd_out[309]
    DIRECTION OUTPUT ;
    USE SIGNAL ;
    SHAPE ABUTMENT ;
    PORT
      LAYER M4 ;
      RECT 0.000 77.903 0.018 77.921 ;
    END
  END rd_out[309]
  PIN rd_out[310]
    DIRECTION OUTPUT ;
    USE SIGNAL ;
    SHAPE ABUTMENT ;
    PORT
      LAYER M4 ;
      RECT 0.000 78.155 0.018 78.173 ;
    END
  END rd_out[310]
  PIN rd_out[311]
    DIRECTION OUTPUT ;
    USE SIGNAL ;
    SHAPE ABUTMENT ;
    PORT
      LAYER M4 ;
      RECT 0.000 78.407 0.018 78.425 ;
    END
  END rd_out[311]
  PIN rd_out[312]
    DIRECTION OUTPUT ;
    USE SIGNAL ;
    SHAPE ABUTMENT ;
    PORT
      LAYER M4 ;
      RECT 0.000 78.659 0.018 78.677 ;
    END
  END rd_out[312]
  PIN rd_out[313]
    DIRECTION OUTPUT ;
    USE SIGNAL ;
    SHAPE ABUTMENT ;
    PORT
      LAYER M4 ;
      RECT 0.000 78.911 0.018 78.929 ;
    END
  END rd_out[313]
  PIN rd_out[314]
    DIRECTION OUTPUT ;
    USE SIGNAL ;
    SHAPE ABUTMENT ;
    PORT
      LAYER M4 ;
      RECT 0.000 79.163 0.018 79.181 ;
    END
  END rd_out[314]
  PIN rd_out[315]
    DIRECTION OUTPUT ;
    USE SIGNAL ;
    SHAPE ABUTMENT ;
    PORT
      LAYER M4 ;
      RECT 0.000 79.415 0.018 79.433 ;
    END
  END rd_out[315]
  PIN rd_out[316]
    DIRECTION OUTPUT ;
    USE SIGNAL ;
    SHAPE ABUTMENT ;
    PORT
      LAYER M4 ;
      RECT 0.000 79.667 0.018 79.685 ;
    END
  END rd_out[316]
  PIN rd_out[317]
    DIRECTION OUTPUT ;
    USE SIGNAL ;
    SHAPE ABUTMENT ;
    PORT
      LAYER M4 ;
      RECT 0.000 79.919 0.018 79.937 ;
    END
  END rd_out[317]
  PIN rd_out[318]
    DIRECTION OUTPUT ;
    USE SIGNAL ;
    SHAPE ABUTMENT ;
    PORT
      LAYER M4 ;
      RECT 0.000 80.171 0.018 80.189 ;
    END
  END rd_out[318]
  PIN rd_out[319]
    DIRECTION OUTPUT ;
    USE SIGNAL ;
    SHAPE ABUTMENT ;
    PORT
      LAYER M4 ;
      RECT 0.000 80.423 0.018 80.441 ;
    END
  END rd_out[319]
  PIN rd_out[320]
    DIRECTION OUTPUT ;
    USE SIGNAL ;
    SHAPE ABUTMENT ;
    PORT
      LAYER M4 ;
      RECT 0.000 80.675 0.018 80.693 ;
    END
  END rd_out[320]
  PIN rd_out[321]
    DIRECTION OUTPUT ;
    USE SIGNAL ;
    SHAPE ABUTMENT ;
    PORT
      LAYER M4 ;
      RECT 0.000 80.927 0.018 80.945 ;
    END
  END rd_out[321]
  PIN rd_out[322]
    DIRECTION OUTPUT ;
    USE SIGNAL ;
    SHAPE ABUTMENT ;
    PORT
      LAYER M4 ;
      RECT 0.000 81.179 0.018 81.197 ;
    END
  END rd_out[322]
  PIN rd_out[323]
    DIRECTION OUTPUT ;
    USE SIGNAL ;
    SHAPE ABUTMENT ;
    PORT
      LAYER M4 ;
      RECT 0.000 81.431 0.018 81.449 ;
    END
  END rd_out[323]
  PIN rd_out[324]
    DIRECTION OUTPUT ;
    USE SIGNAL ;
    SHAPE ABUTMENT ;
    PORT
      LAYER M4 ;
      RECT 0.000 81.683 0.018 81.701 ;
    END
  END rd_out[324]
  PIN rd_out[325]
    DIRECTION OUTPUT ;
    USE SIGNAL ;
    SHAPE ABUTMENT ;
    PORT
      LAYER M4 ;
      RECT 0.000 81.935 0.018 81.953 ;
    END
  END rd_out[325]
  PIN rd_out[326]
    DIRECTION OUTPUT ;
    USE SIGNAL ;
    SHAPE ABUTMENT ;
    PORT
      LAYER M4 ;
      RECT 0.000 82.187 0.018 82.205 ;
    END
  END rd_out[326]
  PIN rd_out[327]
    DIRECTION OUTPUT ;
    USE SIGNAL ;
    SHAPE ABUTMENT ;
    PORT
      LAYER M4 ;
      RECT 0.000 82.439 0.018 82.457 ;
    END
  END rd_out[327]
  PIN rd_out[328]
    DIRECTION OUTPUT ;
    USE SIGNAL ;
    SHAPE ABUTMENT ;
    PORT
      LAYER M4 ;
      RECT 0.000 82.691 0.018 82.709 ;
    END
  END rd_out[328]
  PIN rd_out[329]
    DIRECTION OUTPUT ;
    USE SIGNAL ;
    SHAPE ABUTMENT ;
    PORT
      LAYER M4 ;
      RECT 0.000 82.943 0.018 82.961 ;
    END
  END rd_out[329]
  PIN rd_out[330]
    DIRECTION OUTPUT ;
    USE SIGNAL ;
    SHAPE ABUTMENT ;
    PORT
      LAYER M4 ;
      RECT 0.000 83.195 0.018 83.213 ;
    END
  END rd_out[330]
  PIN rd_out[331]
    DIRECTION OUTPUT ;
    USE SIGNAL ;
    SHAPE ABUTMENT ;
    PORT
      LAYER M4 ;
      RECT 0.000 83.447 0.018 83.465 ;
    END
  END rd_out[331]
  PIN rd_out[332]
    DIRECTION OUTPUT ;
    USE SIGNAL ;
    SHAPE ABUTMENT ;
    PORT
      LAYER M4 ;
      RECT 0.000 83.699 0.018 83.717 ;
    END
  END rd_out[332]
  PIN rd_out[333]
    DIRECTION OUTPUT ;
    USE SIGNAL ;
    SHAPE ABUTMENT ;
    PORT
      LAYER M4 ;
      RECT 0.000 83.951 0.018 83.969 ;
    END
  END rd_out[333]
  PIN rd_out[334]
    DIRECTION OUTPUT ;
    USE SIGNAL ;
    SHAPE ABUTMENT ;
    PORT
      LAYER M4 ;
      RECT 0.000 84.203 0.018 84.221 ;
    END
  END rd_out[334]
  PIN rd_out[335]
    DIRECTION OUTPUT ;
    USE SIGNAL ;
    SHAPE ABUTMENT ;
    PORT
      LAYER M4 ;
      RECT 0.000 84.455 0.018 84.473 ;
    END
  END rd_out[335]
  PIN rd_out[336]
    DIRECTION OUTPUT ;
    USE SIGNAL ;
    SHAPE ABUTMENT ;
    PORT
      LAYER M4 ;
      RECT 0.000 84.707 0.018 84.725 ;
    END
  END rd_out[336]
  PIN rd_out[337]
    DIRECTION OUTPUT ;
    USE SIGNAL ;
    SHAPE ABUTMENT ;
    PORT
      LAYER M4 ;
      RECT 0.000 84.959 0.018 84.977 ;
    END
  END rd_out[337]
  PIN rd_out[338]
    DIRECTION OUTPUT ;
    USE SIGNAL ;
    SHAPE ABUTMENT ;
    PORT
      LAYER M4 ;
      RECT 0.000 85.211 0.018 85.229 ;
    END
  END rd_out[338]
  PIN rd_out[339]
    DIRECTION OUTPUT ;
    USE SIGNAL ;
    SHAPE ABUTMENT ;
    PORT
      LAYER M4 ;
      RECT 0.000 85.463 0.018 85.481 ;
    END
  END rd_out[339]
  PIN rd_out[340]
    DIRECTION OUTPUT ;
    USE SIGNAL ;
    SHAPE ABUTMENT ;
    PORT
      LAYER M4 ;
      RECT 0.000 85.715 0.018 85.733 ;
    END
  END rd_out[340]
  PIN rd_out[341]
    DIRECTION OUTPUT ;
    USE SIGNAL ;
    SHAPE ABUTMENT ;
    PORT
      LAYER M4 ;
      RECT 0.000 85.967 0.018 85.985 ;
    END
  END rd_out[341]
  PIN rd_out[342]
    DIRECTION OUTPUT ;
    USE SIGNAL ;
    SHAPE ABUTMENT ;
    PORT
      LAYER M4 ;
      RECT 0.000 86.219 0.018 86.237 ;
    END
  END rd_out[342]
  PIN rd_out[343]
    DIRECTION OUTPUT ;
    USE SIGNAL ;
    SHAPE ABUTMENT ;
    PORT
      LAYER M4 ;
      RECT 0.000 86.471 0.018 86.489 ;
    END
  END rd_out[343]
  PIN rd_out[344]
    DIRECTION OUTPUT ;
    USE SIGNAL ;
    SHAPE ABUTMENT ;
    PORT
      LAYER M4 ;
      RECT 0.000 86.723 0.018 86.741 ;
    END
  END rd_out[344]
  PIN rd_out[345]
    DIRECTION OUTPUT ;
    USE SIGNAL ;
    SHAPE ABUTMENT ;
    PORT
      LAYER M4 ;
      RECT 0.000 86.975 0.018 86.993 ;
    END
  END rd_out[345]
  PIN rd_out[346]
    DIRECTION OUTPUT ;
    USE SIGNAL ;
    SHAPE ABUTMENT ;
    PORT
      LAYER M4 ;
      RECT 0.000 87.227 0.018 87.245 ;
    END
  END rd_out[346]
  PIN rd_out[347]
    DIRECTION OUTPUT ;
    USE SIGNAL ;
    SHAPE ABUTMENT ;
    PORT
      LAYER M4 ;
      RECT 0.000 87.479 0.018 87.497 ;
    END
  END rd_out[347]
  PIN rd_out[348]
    DIRECTION OUTPUT ;
    USE SIGNAL ;
    SHAPE ABUTMENT ;
    PORT
      LAYER M4 ;
      RECT 0.000 87.731 0.018 87.749 ;
    END
  END rd_out[348]
  PIN rd_out[349]
    DIRECTION OUTPUT ;
    USE SIGNAL ;
    SHAPE ABUTMENT ;
    PORT
      LAYER M4 ;
      RECT 0.000 87.983 0.018 88.001 ;
    END
  END rd_out[349]
  PIN rd_out[350]
    DIRECTION OUTPUT ;
    USE SIGNAL ;
    SHAPE ABUTMENT ;
    PORT
      LAYER M4 ;
      RECT 0.000 88.235 0.018 88.253 ;
    END
  END rd_out[350]
  PIN rd_out[351]
    DIRECTION OUTPUT ;
    USE SIGNAL ;
    SHAPE ABUTMENT ;
    PORT
      LAYER M4 ;
      RECT 0.000 88.487 0.018 88.505 ;
    END
  END rd_out[351]
  PIN rd_out[352]
    DIRECTION OUTPUT ;
    USE SIGNAL ;
    SHAPE ABUTMENT ;
    PORT
      LAYER M4 ;
      RECT 0.000 88.739 0.018 88.757 ;
    END
  END rd_out[352]
  PIN rd_out[353]
    DIRECTION OUTPUT ;
    USE SIGNAL ;
    SHAPE ABUTMENT ;
    PORT
      LAYER M4 ;
      RECT 0.000 88.991 0.018 89.009 ;
    END
  END rd_out[353]
  PIN rd_out[354]
    DIRECTION OUTPUT ;
    USE SIGNAL ;
    SHAPE ABUTMENT ;
    PORT
      LAYER M4 ;
      RECT 0.000 89.243 0.018 89.261 ;
    END
  END rd_out[354]
  PIN rd_out[355]
    DIRECTION OUTPUT ;
    USE SIGNAL ;
    SHAPE ABUTMENT ;
    PORT
      LAYER M4 ;
      RECT 0.000 89.495 0.018 89.513 ;
    END
  END rd_out[355]
  PIN rd_out[356]
    DIRECTION OUTPUT ;
    USE SIGNAL ;
    SHAPE ABUTMENT ;
    PORT
      LAYER M4 ;
      RECT 0.000 89.747 0.018 89.765 ;
    END
  END rd_out[356]
  PIN rd_out[357]
    DIRECTION OUTPUT ;
    USE SIGNAL ;
    SHAPE ABUTMENT ;
    PORT
      LAYER M4 ;
      RECT 0.000 89.999 0.018 90.017 ;
    END
  END rd_out[357]
  PIN rd_out[358]
    DIRECTION OUTPUT ;
    USE SIGNAL ;
    SHAPE ABUTMENT ;
    PORT
      LAYER M4 ;
      RECT 0.000 90.251 0.018 90.269 ;
    END
  END rd_out[358]
  PIN rd_out[359]
    DIRECTION OUTPUT ;
    USE SIGNAL ;
    SHAPE ABUTMENT ;
    PORT
      LAYER M4 ;
      RECT 0.000 90.503 0.018 90.521 ;
    END
  END rd_out[359]
  PIN rd_out[360]
    DIRECTION OUTPUT ;
    USE SIGNAL ;
    SHAPE ABUTMENT ;
    PORT
      LAYER M4 ;
      RECT 0.000 90.755 0.018 90.773 ;
    END
  END rd_out[360]
  PIN rd_out[361]
    DIRECTION OUTPUT ;
    USE SIGNAL ;
    SHAPE ABUTMENT ;
    PORT
      LAYER M4 ;
      RECT 0.000 91.007 0.018 91.025 ;
    END
  END rd_out[361]
  PIN rd_out[362]
    DIRECTION OUTPUT ;
    USE SIGNAL ;
    SHAPE ABUTMENT ;
    PORT
      LAYER M4 ;
      RECT 0.000 91.259 0.018 91.277 ;
    END
  END rd_out[362]
  PIN rd_out[363]
    DIRECTION OUTPUT ;
    USE SIGNAL ;
    SHAPE ABUTMENT ;
    PORT
      LAYER M4 ;
      RECT 0.000 91.511 0.018 91.529 ;
    END
  END rd_out[363]
  PIN rd_out[364]
    DIRECTION OUTPUT ;
    USE SIGNAL ;
    SHAPE ABUTMENT ;
    PORT
      LAYER M4 ;
      RECT 0.000 91.763 0.018 91.781 ;
    END
  END rd_out[364]
  PIN rd_out[365]
    DIRECTION OUTPUT ;
    USE SIGNAL ;
    SHAPE ABUTMENT ;
    PORT
      LAYER M4 ;
      RECT 0.000 92.015 0.018 92.033 ;
    END
  END rd_out[365]
  PIN rd_out[366]
    DIRECTION OUTPUT ;
    USE SIGNAL ;
    SHAPE ABUTMENT ;
    PORT
      LAYER M4 ;
      RECT 0.000 92.267 0.018 92.285 ;
    END
  END rd_out[366]
  PIN rd_out[367]
    DIRECTION OUTPUT ;
    USE SIGNAL ;
    SHAPE ABUTMENT ;
    PORT
      LAYER M4 ;
      RECT 0.000 92.519 0.018 92.537 ;
    END
  END rd_out[367]
  PIN rd_out[368]
    DIRECTION OUTPUT ;
    USE SIGNAL ;
    SHAPE ABUTMENT ;
    PORT
      LAYER M4 ;
      RECT 0.000 92.771 0.018 92.789 ;
    END
  END rd_out[368]
  PIN rd_out[369]
    DIRECTION OUTPUT ;
    USE SIGNAL ;
    SHAPE ABUTMENT ;
    PORT
      LAYER M4 ;
      RECT 0.000 93.023 0.018 93.041 ;
    END
  END rd_out[369]
  PIN rd_out[370]
    DIRECTION OUTPUT ;
    USE SIGNAL ;
    SHAPE ABUTMENT ;
    PORT
      LAYER M4 ;
      RECT 0.000 93.275 0.018 93.293 ;
    END
  END rd_out[370]
  PIN rd_out[371]
    DIRECTION OUTPUT ;
    USE SIGNAL ;
    SHAPE ABUTMENT ;
    PORT
      LAYER M4 ;
      RECT 0.000 93.527 0.018 93.545 ;
    END
  END rd_out[371]
  PIN rd_out[372]
    DIRECTION OUTPUT ;
    USE SIGNAL ;
    SHAPE ABUTMENT ;
    PORT
      LAYER M4 ;
      RECT 0.000 93.779 0.018 93.797 ;
    END
  END rd_out[372]
  PIN rd_out[373]
    DIRECTION OUTPUT ;
    USE SIGNAL ;
    SHAPE ABUTMENT ;
    PORT
      LAYER M4 ;
      RECT 0.000 94.031 0.018 94.049 ;
    END
  END rd_out[373]
  PIN rd_out[374]
    DIRECTION OUTPUT ;
    USE SIGNAL ;
    SHAPE ABUTMENT ;
    PORT
      LAYER M4 ;
      RECT 0.000 94.283 0.018 94.301 ;
    END
  END rd_out[374]
  PIN rd_out[375]
    DIRECTION OUTPUT ;
    USE SIGNAL ;
    SHAPE ABUTMENT ;
    PORT
      LAYER M4 ;
      RECT 0.000 94.535 0.018 94.553 ;
    END
  END rd_out[375]
  PIN rd_out[376]
    DIRECTION OUTPUT ;
    USE SIGNAL ;
    SHAPE ABUTMENT ;
    PORT
      LAYER M4 ;
      RECT 0.000 94.787 0.018 94.805 ;
    END
  END rd_out[376]
  PIN rd_out[377]
    DIRECTION OUTPUT ;
    USE SIGNAL ;
    SHAPE ABUTMENT ;
    PORT
      LAYER M4 ;
      RECT 0.000 95.039 0.018 95.057 ;
    END
  END rd_out[377]
  PIN rd_out[378]
    DIRECTION OUTPUT ;
    USE SIGNAL ;
    SHAPE ABUTMENT ;
    PORT
      LAYER M4 ;
      RECT 0.000 95.291 0.018 95.309 ;
    END
  END rd_out[378]
  PIN rd_out[379]
    DIRECTION OUTPUT ;
    USE SIGNAL ;
    SHAPE ABUTMENT ;
    PORT
      LAYER M4 ;
      RECT 0.000 95.543 0.018 95.561 ;
    END
  END rd_out[379]
  PIN rd_out[380]
    DIRECTION OUTPUT ;
    USE SIGNAL ;
    SHAPE ABUTMENT ;
    PORT
      LAYER M4 ;
      RECT 0.000 95.795 0.018 95.813 ;
    END
  END rd_out[380]
  PIN rd_out[381]
    DIRECTION OUTPUT ;
    USE SIGNAL ;
    SHAPE ABUTMENT ;
    PORT
      LAYER M4 ;
      RECT 0.000 96.047 0.018 96.065 ;
    END
  END rd_out[381]
  PIN rd_out[382]
    DIRECTION OUTPUT ;
    USE SIGNAL ;
    SHAPE ABUTMENT ;
    PORT
      LAYER M4 ;
      RECT 0.000 96.299 0.018 96.317 ;
    END
  END rd_out[382]
  PIN rd_out[383]
    DIRECTION OUTPUT ;
    USE SIGNAL ;
    SHAPE ABUTMENT ;
    PORT
      LAYER M4 ;
      RECT 0.000 96.551 0.018 96.569 ;
    END
  END rd_out[383]
  PIN rd_out[384]
    DIRECTION OUTPUT ;
    USE SIGNAL ;
    SHAPE ABUTMENT ;
    PORT
      LAYER M4 ;
      RECT 0.000 96.803 0.018 96.821 ;
    END
  END rd_out[384]
  PIN rd_out[385]
    DIRECTION OUTPUT ;
    USE SIGNAL ;
    SHAPE ABUTMENT ;
    PORT
      LAYER M4 ;
      RECT 0.000 97.055 0.018 97.073 ;
    END
  END rd_out[385]
  PIN rd_out[386]
    DIRECTION OUTPUT ;
    USE SIGNAL ;
    SHAPE ABUTMENT ;
    PORT
      LAYER M4 ;
      RECT 0.000 97.307 0.018 97.325 ;
    END
  END rd_out[386]
  PIN rd_out[387]
    DIRECTION OUTPUT ;
    USE SIGNAL ;
    SHAPE ABUTMENT ;
    PORT
      LAYER M4 ;
      RECT 0.000 97.559 0.018 97.577 ;
    END
  END rd_out[387]
  PIN rd_out[388]
    DIRECTION OUTPUT ;
    USE SIGNAL ;
    SHAPE ABUTMENT ;
    PORT
      LAYER M4 ;
      RECT 0.000 97.811 0.018 97.829 ;
    END
  END rd_out[388]
  PIN rd_out[389]
    DIRECTION OUTPUT ;
    USE SIGNAL ;
    SHAPE ABUTMENT ;
    PORT
      LAYER M4 ;
      RECT 0.000 98.063 0.018 98.081 ;
    END
  END rd_out[389]
  PIN rd_out[390]
    DIRECTION OUTPUT ;
    USE SIGNAL ;
    SHAPE ABUTMENT ;
    PORT
      LAYER M4 ;
      RECT 0.000 98.315 0.018 98.333 ;
    END
  END rd_out[390]
  PIN rd_out[391]
    DIRECTION OUTPUT ;
    USE SIGNAL ;
    SHAPE ABUTMENT ;
    PORT
      LAYER M4 ;
      RECT 0.000 98.567 0.018 98.585 ;
    END
  END rd_out[391]
  PIN rd_out[392]
    DIRECTION OUTPUT ;
    USE SIGNAL ;
    SHAPE ABUTMENT ;
    PORT
      LAYER M4 ;
      RECT 0.000 98.819 0.018 98.837 ;
    END
  END rd_out[392]
  PIN rd_out[393]
    DIRECTION OUTPUT ;
    USE SIGNAL ;
    SHAPE ABUTMENT ;
    PORT
      LAYER M4 ;
      RECT 0.000 99.071 0.018 99.089 ;
    END
  END rd_out[393]
  PIN rd_out[394]
    DIRECTION OUTPUT ;
    USE SIGNAL ;
    SHAPE ABUTMENT ;
    PORT
      LAYER M4 ;
      RECT 0.000 99.323 0.018 99.341 ;
    END
  END rd_out[394]
  PIN rd_out[395]
    DIRECTION OUTPUT ;
    USE SIGNAL ;
    SHAPE ABUTMENT ;
    PORT
      LAYER M4 ;
      RECT 0.000 99.575 0.018 99.593 ;
    END
  END rd_out[395]
  PIN rd_out[396]
    DIRECTION OUTPUT ;
    USE SIGNAL ;
    SHAPE ABUTMENT ;
    PORT
      LAYER M4 ;
      RECT 0.000 99.827 0.018 99.845 ;
    END
  END rd_out[396]
  PIN rd_out[397]
    DIRECTION OUTPUT ;
    USE SIGNAL ;
    SHAPE ABUTMENT ;
    PORT
      LAYER M4 ;
      RECT 0.000 100.079 0.018 100.097 ;
    END
  END rd_out[397]
  PIN rd_out[398]
    DIRECTION OUTPUT ;
    USE SIGNAL ;
    SHAPE ABUTMENT ;
    PORT
      LAYER M4 ;
      RECT 0.000 100.331 0.018 100.349 ;
    END
  END rd_out[398]
  PIN rd_out[399]
    DIRECTION OUTPUT ;
    USE SIGNAL ;
    SHAPE ABUTMENT ;
    PORT
      LAYER M4 ;
      RECT 0.000 100.583 0.018 100.601 ;
    END
  END rd_out[399]
  PIN rd_out[400]
    DIRECTION OUTPUT ;
    USE SIGNAL ;
    SHAPE ABUTMENT ;
    PORT
      LAYER M4 ;
      RECT 0.000 100.835 0.018 100.853 ;
    END
  END rd_out[400]
  PIN rd_out[401]
    DIRECTION OUTPUT ;
    USE SIGNAL ;
    SHAPE ABUTMENT ;
    PORT
      LAYER M4 ;
      RECT 0.000 101.087 0.018 101.105 ;
    END
  END rd_out[401]
  PIN rd_out[402]
    DIRECTION OUTPUT ;
    USE SIGNAL ;
    SHAPE ABUTMENT ;
    PORT
      LAYER M4 ;
      RECT 0.000 101.339 0.018 101.357 ;
    END
  END rd_out[402]
  PIN rd_out[403]
    DIRECTION OUTPUT ;
    USE SIGNAL ;
    SHAPE ABUTMENT ;
    PORT
      LAYER M4 ;
      RECT 0.000 101.591 0.018 101.609 ;
    END
  END rd_out[403]
  PIN rd_out[404]
    DIRECTION OUTPUT ;
    USE SIGNAL ;
    SHAPE ABUTMENT ;
    PORT
      LAYER M4 ;
      RECT 0.000 101.843 0.018 101.861 ;
    END
  END rd_out[404]
  PIN rd_out[405]
    DIRECTION OUTPUT ;
    USE SIGNAL ;
    SHAPE ABUTMENT ;
    PORT
      LAYER M4 ;
      RECT 0.000 102.095 0.018 102.113 ;
    END
  END rd_out[405]
  PIN rd_out[406]
    DIRECTION OUTPUT ;
    USE SIGNAL ;
    SHAPE ABUTMENT ;
    PORT
      LAYER M4 ;
      RECT 0.000 102.347 0.018 102.365 ;
    END
  END rd_out[406]
  PIN rd_out[407]
    DIRECTION OUTPUT ;
    USE SIGNAL ;
    SHAPE ABUTMENT ;
    PORT
      LAYER M4 ;
      RECT 0.000 102.599 0.018 102.617 ;
    END
  END rd_out[407]
  PIN rd_out[408]
    DIRECTION OUTPUT ;
    USE SIGNAL ;
    SHAPE ABUTMENT ;
    PORT
      LAYER M4 ;
      RECT 0.000 102.851 0.018 102.869 ;
    END
  END rd_out[408]
  PIN rd_out[409]
    DIRECTION OUTPUT ;
    USE SIGNAL ;
    SHAPE ABUTMENT ;
    PORT
      LAYER M4 ;
      RECT 0.000 103.103 0.018 103.121 ;
    END
  END rd_out[409]
  PIN rd_out[410]
    DIRECTION OUTPUT ;
    USE SIGNAL ;
    SHAPE ABUTMENT ;
    PORT
      LAYER M4 ;
      RECT 0.000 103.355 0.018 103.373 ;
    END
  END rd_out[410]
  PIN rd_out[411]
    DIRECTION OUTPUT ;
    USE SIGNAL ;
    SHAPE ABUTMENT ;
    PORT
      LAYER M4 ;
      RECT 0.000 103.607 0.018 103.625 ;
    END
  END rd_out[411]
  PIN rd_out[412]
    DIRECTION OUTPUT ;
    USE SIGNAL ;
    SHAPE ABUTMENT ;
    PORT
      LAYER M4 ;
      RECT 0.000 103.859 0.018 103.877 ;
    END
  END rd_out[412]
  PIN rd_out[413]
    DIRECTION OUTPUT ;
    USE SIGNAL ;
    SHAPE ABUTMENT ;
    PORT
      LAYER M4 ;
      RECT 0.000 104.111 0.018 104.129 ;
    END
  END rd_out[413]
  PIN rd_out[414]
    DIRECTION OUTPUT ;
    USE SIGNAL ;
    SHAPE ABUTMENT ;
    PORT
      LAYER M4 ;
      RECT 0.000 104.363 0.018 104.381 ;
    END
  END rd_out[414]
  PIN rd_out[415]
    DIRECTION OUTPUT ;
    USE SIGNAL ;
    SHAPE ABUTMENT ;
    PORT
      LAYER M4 ;
      RECT 0.000 104.615 0.018 104.633 ;
    END
  END rd_out[415]
  PIN rd_out[416]
    DIRECTION OUTPUT ;
    USE SIGNAL ;
    SHAPE ABUTMENT ;
    PORT
      LAYER M4 ;
      RECT 0.000 104.867 0.018 104.885 ;
    END
  END rd_out[416]
  PIN rd_out[417]
    DIRECTION OUTPUT ;
    USE SIGNAL ;
    SHAPE ABUTMENT ;
    PORT
      LAYER M4 ;
      RECT 0.000 105.119 0.018 105.137 ;
    END
  END rd_out[417]
  PIN rd_out[418]
    DIRECTION OUTPUT ;
    USE SIGNAL ;
    SHAPE ABUTMENT ;
    PORT
      LAYER M4 ;
      RECT 0.000 105.371 0.018 105.389 ;
    END
  END rd_out[418]
  PIN rd_out[419]
    DIRECTION OUTPUT ;
    USE SIGNAL ;
    SHAPE ABUTMENT ;
    PORT
      LAYER M4 ;
      RECT 0.000 105.623 0.018 105.641 ;
    END
  END rd_out[419]
  PIN rd_out[420]
    DIRECTION OUTPUT ;
    USE SIGNAL ;
    SHAPE ABUTMENT ;
    PORT
      LAYER M4 ;
      RECT 0.000 105.875 0.018 105.893 ;
    END
  END rd_out[420]
  PIN rd_out[421]
    DIRECTION OUTPUT ;
    USE SIGNAL ;
    SHAPE ABUTMENT ;
    PORT
      LAYER M4 ;
      RECT 0.000 106.127 0.018 106.145 ;
    END
  END rd_out[421]
  PIN rd_out[422]
    DIRECTION OUTPUT ;
    USE SIGNAL ;
    SHAPE ABUTMENT ;
    PORT
      LAYER M4 ;
      RECT 0.000 106.379 0.018 106.397 ;
    END
  END rd_out[422]
  PIN rd_out[423]
    DIRECTION OUTPUT ;
    USE SIGNAL ;
    SHAPE ABUTMENT ;
    PORT
      LAYER M4 ;
      RECT 0.000 106.631 0.018 106.649 ;
    END
  END rd_out[423]
  PIN rd_out[424]
    DIRECTION OUTPUT ;
    USE SIGNAL ;
    SHAPE ABUTMENT ;
    PORT
      LAYER M4 ;
      RECT 0.000 106.883 0.018 106.901 ;
    END
  END rd_out[424]
  PIN rd_out[425]
    DIRECTION OUTPUT ;
    USE SIGNAL ;
    SHAPE ABUTMENT ;
    PORT
      LAYER M4 ;
      RECT 0.000 107.135 0.018 107.153 ;
    END
  END rd_out[425]
  PIN rd_out[426]
    DIRECTION OUTPUT ;
    USE SIGNAL ;
    SHAPE ABUTMENT ;
    PORT
      LAYER M4 ;
      RECT 0.000 107.387 0.018 107.405 ;
    END
  END rd_out[426]
  PIN rd_out[427]
    DIRECTION OUTPUT ;
    USE SIGNAL ;
    SHAPE ABUTMENT ;
    PORT
      LAYER M4 ;
      RECT 0.000 107.639 0.018 107.657 ;
    END
  END rd_out[427]
  PIN rd_out[428]
    DIRECTION OUTPUT ;
    USE SIGNAL ;
    SHAPE ABUTMENT ;
    PORT
      LAYER M4 ;
      RECT 0.000 107.891 0.018 107.909 ;
    END
  END rd_out[428]
  PIN rd_out[429]
    DIRECTION OUTPUT ;
    USE SIGNAL ;
    SHAPE ABUTMENT ;
    PORT
      LAYER M4 ;
      RECT 0.000 108.143 0.018 108.161 ;
    END
  END rd_out[429]
  PIN rd_out[430]
    DIRECTION OUTPUT ;
    USE SIGNAL ;
    SHAPE ABUTMENT ;
    PORT
      LAYER M4 ;
      RECT 0.000 108.395 0.018 108.413 ;
    END
  END rd_out[430]
  PIN rd_out[431]
    DIRECTION OUTPUT ;
    USE SIGNAL ;
    SHAPE ABUTMENT ;
    PORT
      LAYER M4 ;
      RECT 0.000 108.647 0.018 108.665 ;
    END
  END rd_out[431]
  PIN rd_out[432]
    DIRECTION OUTPUT ;
    USE SIGNAL ;
    SHAPE ABUTMENT ;
    PORT
      LAYER M4 ;
      RECT 0.000 108.899 0.018 108.917 ;
    END
  END rd_out[432]
  PIN rd_out[433]
    DIRECTION OUTPUT ;
    USE SIGNAL ;
    SHAPE ABUTMENT ;
    PORT
      LAYER M4 ;
      RECT 0.000 109.151 0.018 109.169 ;
    END
  END rd_out[433]
  PIN rd_out[434]
    DIRECTION OUTPUT ;
    USE SIGNAL ;
    SHAPE ABUTMENT ;
    PORT
      LAYER M4 ;
      RECT 0.000 109.403 0.018 109.421 ;
    END
  END rd_out[434]
  PIN rd_out[435]
    DIRECTION OUTPUT ;
    USE SIGNAL ;
    SHAPE ABUTMENT ;
    PORT
      LAYER M4 ;
      RECT 0.000 109.655 0.018 109.673 ;
    END
  END rd_out[435]
  PIN rd_out[436]
    DIRECTION OUTPUT ;
    USE SIGNAL ;
    SHAPE ABUTMENT ;
    PORT
      LAYER M4 ;
      RECT 0.000 109.907 0.018 109.925 ;
    END
  END rd_out[436]
  PIN rd_out[437]
    DIRECTION OUTPUT ;
    USE SIGNAL ;
    SHAPE ABUTMENT ;
    PORT
      LAYER M4 ;
      RECT 0.000 110.159 0.018 110.177 ;
    END
  END rd_out[437]
  PIN rd_out[438]
    DIRECTION OUTPUT ;
    USE SIGNAL ;
    SHAPE ABUTMENT ;
    PORT
      LAYER M4 ;
      RECT 0.000 110.411 0.018 110.429 ;
    END
  END rd_out[438]
  PIN rd_out[439]
    DIRECTION OUTPUT ;
    USE SIGNAL ;
    SHAPE ABUTMENT ;
    PORT
      LAYER M4 ;
      RECT 0.000 110.663 0.018 110.681 ;
    END
  END rd_out[439]
  PIN rd_out[440]
    DIRECTION OUTPUT ;
    USE SIGNAL ;
    SHAPE ABUTMENT ;
    PORT
      LAYER M4 ;
      RECT 0.000 110.915 0.018 110.933 ;
    END
  END rd_out[440]
  PIN rd_out[441]
    DIRECTION OUTPUT ;
    USE SIGNAL ;
    SHAPE ABUTMENT ;
    PORT
      LAYER M4 ;
      RECT 0.000 111.167 0.018 111.185 ;
    END
  END rd_out[441]
  PIN rd_out[442]
    DIRECTION OUTPUT ;
    USE SIGNAL ;
    SHAPE ABUTMENT ;
    PORT
      LAYER M4 ;
      RECT 0.000 111.419 0.018 111.437 ;
    END
  END rd_out[442]
  PIN rd_out[443]
    DIRECTION OUTPUT ;
    USE SIGNAL ;
    SHAPE ABUTMENT ;
    PORT
      LAYER M4 ;
      RECT 0.000 111.671 0.018 111.689 ;
    END
  END rd_out[443]
  PIN rd_out[444]
    DIRECTION OUTPUT ;
    USE SIGNAL ;
    SHAPE ABUTMENT ;
    PORT
      LAYER M4 ;
      RECT 0.000 111.923 0.018 111.941 ;
    END
  END rd_out[444]
  PIN rd_out[445]
    DIRECTION OUTPUT ;
    USE SIGNAL ;
    SHAPE ABUTMENT ;
    PORT
      LAYER M4 ;
      RECT 0.000 112.175 0.018 112.193 ;
    END
  END rd_out[445]
  PIN rd_out[446]
    DIRECTION OUTPUT ;
    USE SIGNAL ;
    SHAPE ABUTMENT ;
    PORT
      LAYER M4 ;
      RECT 0.000 112.427 0.018 112.445 ;
    END
  END rd_out[446]
  PIN rd_out[447]
    DIRECTION OUTPUT ;
    USE SIGNAL ;
    SHAPE ABUTMENT ;
    PORT
      LAYER M4 ;
      RECT 0.000 112.679 0.018 112.697 ;
    END
  END rd_out[447]
  PIN rd_out[448]
    DIRECTION OUTPUT ;
    USE SIGNAL ;
    SHAPE ABUTMENT ;
    PORT
      LAYER M4 ;
      RECT 0.000 112.931 0.018 112.949 ;
    END
  END rd_out[448]
  PIN rd_out[449]
    DIRECTION OUTPUT ;
    USE SIGNAL ;
    SHAPE ABUTMENT ;
    PORT
      LAYER M4 ;
      RECT 0.000 113.183 0.018 113.201 ;
    END
  END rd_out[449]
  PIN rd_out[450]
    DIRECTION OUTPUT ;
    USE SIGNAL ;
    SHAPE ABUTMENT ;
    PORT
      LAYER M4 ;
      RECT 0.000 113.435 0.018 113.453 ;
    END
  END rd_out[450]
  PIN rd_out[451]
    DIRECTION OUTPUT ;
    USE SIGNAL ;
    SHAPE ABUTMENT ;
    PORT
      LAYER M4 ;
      RECT 0.000 113.687 0.018 113.705 ;
    END
  END rd_out[451]
  PIN rd_out[452]
    DIRECTION OUTPUT ;
    USE SIGNAL ;
    SHAPE ABUTMENT ;
    PORT
      LAYER M4 ;
      RECT 0.000 113.939 0.018 113.957 ;
    END
  END rd_out[452]
  PIN rd_out[453]
    DIRECTION OUTPUT ;
    USE SIGNAL ;
    SHAPE ABUTMENT ;
    PORT
      LAYER M4 ;
      RECT 0.000 114.191 0.018 114.209 ;
    END
  END rd_out[453]
  PIN rd_out[454]
    DIRECTION OUTPUT ;
    USE SIGNAL ;
    SHAPE ABUTMENT ;
    PORT
      LAYER M4 ;
      RECT 0.000 114.443 0.018 114.461 ;
    END
  END rd_out[454]
  PIN rd_out[455]
    DIRECTION OUTPUT ;
    USE SIGNAL ;
    SHAPE ABUTMENT ;
    PORT
      LAYER M4 ;
      RECT 0.000 114.695 0.018 114.713 ;
    END
  END rd_out[455]
  PIN rd_out[456]
    DIRECTION OUTPUT ;
    USE SIGNAL ;
    SHAPE ABUTMENT ;
    PORT
      LAYER M4 ;
      RECT 0.000 114.947 0.018 114.965 ;
    END
  END rd_out[456]
  PIN rd_out[457]
    DIRECTION OUTPUT ;
    USE SIGNAL ;
    SHAPE ABUTMENT ;
    PORT
      LAYER M4 ;
      RECT 0.000 115.199 0.018 115.217 ;
    END
  END rd_out[457]
  PIN rd_out[458]
    DIRECTION OUTPUT ;
    USE SIGNAL ;
    SHAPE ABUTMENT ;
    PORT
      LAYER M4 ;
      RECT 0.000 115.451 0.018 115.469 ;
    END
  END rd_out[458]
  PIN rd_out[459]
    DIRECTION OUTPUT ;
    USE SIGNAL ;
    SHAPE ABUTMENT ;
    PORT
      LAYER M4 ;
      RECT 0.000 115.703 0.018 115.721 ;
    END
  END rd_out[459]
  PIN rd_out[460]
    DIRECTION OUTPUT ;
    USE SIGNAL ;
    SHAPE ABUTMENT ;
    PORT
      LAYER M4 ;
      RECT 0.000 115.955 0.018 115.973 ;
    END
  END rd_out[460]
  PIN rd_out[461]
    DIRECTION OUTPUT ;
    USE SIGNAL ;
    SHAPE ABUTMENT ;
    PORT
      LAYER M4 ;
      RECT 0.000 116.207 0.018 116.225 ;
    END
  END rd_out[461]
  PIN rd_out[462]
    DIRECTION OUTPUT ;
    USE SIGNAL ;
    SHAPE ABUTMENT ;
    PORT
      LAYER M4 ;
      RECT 0.000 116.459 0.018 116.477 ;
    END
  END rd_out[462]
  PIN rd_out[463]
    DIRECTION OUTPUT ;
    USE SIGNAL ;
    SHAPE ABUTMENT ;
    PORT
      LAYER M4 ;
      RECT 0.000 116.711 0.018 116.729 ;
    END
  END rd_out[463]
  PIN rd_out[464]
    DIRECTION OUTPUT ;
    USE SIGNAL ;
    SHAPE ABUTMENT ;
    PORT
      LAYER M4 ;
      RECT 0.000 116.963 0.018 116.981 ;
    END
  END rd_out[464]
  PIN rd_out[465]
    DIRECTION OUTPUT ;
    USE SIGNAL ;
    SHAPE ABUTMENT ;
    PORT
      LAYER M4 ;
      RECT 0.000 117.215 0.018 117.233 ;
    END
  END rd_out[465]
  PIN rd_out[466]
    DIRECTION OUTPUT ;
    USE SIGNAL ;
    SHAPE ABUTMENT ;
    PORT
      LAYER M4 ;
      RECT 0.000 117.467 0.018 117.485 ;
    END
  END rd_out[466]
  PIN rd_out[467]
    DIRECTION OUTPUT ;
    USE SIGNAL ;
    SHAPE ABUTMENT ;
    PORT
      LAYER M4 ;
      RECT 0.000 117.719 0.018 117.737 ;
    END
  END rd_out[467]
  PIN rd_out[468]
    DIRECTION OUTPUT ;
    USE SIGNAL ;
    SHAPE ABUTMENT ;
    PORT
      LAYER M4 ;
      RECT 0.000 117.971 0.018 117.989 ;
    END
  END rd_out[468]
  PIN rd_out[469]
    DIRECTION OUTPUT ;
    USE SIGNAL ;
    SHAPE ABUTMENT ;
    PORT
      LAYER M4 ;
      RECT 0.000 118.223 0.018 118.241 ;
    END
  END rd_out[469]
  PIN rd_out[470]
    DIRECTION OUTPUT ;
    USE SIGNAL ;
    SHAPE ABUTMENT ;
    PORT
      LAYER M4 ;
      RECT 0.000 118.475 0.018 118.493 ;
    END
  END rd_out[470]
  PIN rd_out[471]
    DIRECTION OUTPUT ;
    USE SIGNAL ;
    SHAPE ABUTMENT ;
    PORT
      LAYER M4 ;
      RECT 0.000 118.727 0.018 118.745 ;
    END
  END rd_out[471]
  PIN rd_out[472]
    DIRECTION OUTPUT ;
    USE SIGNAL ;
    SHAPE ABUTMENT ;
    PORT
      LAYER M4 ;
      RECT 0.000 118.979 0.018 118.997 ;
    END
  END rd_out[472]
  PIN rd_out[473]
    DIRECTION OUTPUT ;
    USE SIGNAL ;
    SHAPE ABUTMENT ;
    PORT
      LAYER M4 ;
      RECT 0.000 119.231 0.018 119.249 ;
    END
  END rd_out[473]
  PIN rd_out[474]
    DIRECTION OUTPUT ;
    USE SIGNAL ;
    SHAPE ABUTMENT ;
    PORT
      LAYER M4 ;
      RECT 0.000 119.483 0.018 119.501 ;
    END
  END rd_out[474]
  PIN rd_out[475]
    DIRECTION OUTPUT ;
    USE SIGNAL ;
    SHAPE ABUTMENT ;
    PORT
      LAYER M4 ;
      RECT 0.000 119.735 0.018 119.753 ;
    END
  END rd_out[475]
  PIN rd_out[476]
    DIRECTION OUTPUT ;
    USE SIGNAL ;
    SHAPE ABUTMENT ;
    PORT
      LAYER M4 ;
      RECT 0.000 119.987 0.018 120.005 ;
    END
  END rd_out[476]
  PIN rd_out[477]
    DIRECTION OUTPUT ;
    USE SIGNAL ;
    SHAPE ABUTMENT ;
    PORT
      LAYER M4 ;
      RECT 0.000 120.239 0.018 120.257 ;
    END
  END rd_out[477]
  PIN rd_out[478]
    DIRECTION OUTPUT ;
    USE SIGNAL ;
    SHAPE ABUTMENT ;
    PORT
      LAYER M4 ;
      RECT 0.000 120.491 0.018 120.509 ;
    END
  END rd_out[478]
  PIN rd_out[479]
    DIRECTION OUTPUT ;
    USE SIGNAL ;
    SHAPE ABUTMENT ;
    PORT
      LAYER M4 ;
      RECT 0.000 120.743 0.018 120.761 ;
    END
  END rd_out[479]
  PIN rd_out[480]
    DIRECTION OUTPUT ;
    USE SIGNAL ;
    SHAPE ABUTMENT ;
    PORT
      LAYER M4 ;
      RECT 0.000 120.995 0.018 121.013 ;
    END
  END rd_out[480]
  PIN rd_out[481]
    DIRECTION OUTPUT ;
    USE SIGNAL ;
    SHAPE ABUTMENT ;
    PORT
      LAYER M4 ;
      RECT 0.000 121.247 0.018 121.265 ;
    END
  END rd_out[481]
  PIN rd_out[482]
    DIRECTION OUTPUT ;
    USE SIGNAL ;
    SHAPE ABUTMENT ;
    PORT
      LAYER M4 ;
      RECT 0.000 121.499 0.018 121.517 ;
    END
  END rd_out[482]
  PIN rd_out[483]
    DIRECTION OUTPUT ;
    USE SIGNAL ;
    SHAPE ABUTMENT ;
    PORT
      LAYER M4 ;
      RECT 0.000 121.751 0.018 121.769 ;
    END
  END rd_out[483]
  PIN rd_out[484]
    DIRECTION OUTPUT ;
    USE SIGNAL ;
    SHAPE ABUTMENT ;
    PORT
      LAYER M4 ;
      RECT 0.000 122.003 0.018 122.021 ;
    END
  END rd_out[484]
  PIN rd_out[485]
    DIRECTION OUTPUT ;
    USE SIGNAL ;
    SHAPE ABUTMENT ;
    PORT
      LAYER M4 ;
      RECT 0.000 122.255 0.018 122.273 ;
    END
  END rd_out[485]
  PIN rd_out[486]
    DIRECTION OUTPUT ;
    USE SIGNAL ;
    SHAPE ABUTMENT ;
    PORT
      LAYER M4 ;
      RECT 0.000 122.507 0.018 122.525 ;
    END
  END rd_out[486]
  PIN rd_out[487]
    DIRECTION OUTPUT ;
    USE SIGNAL ;
    SHAPE ABUTMENT ;
    PORT
      LAYER M4 ;
      RECT 0.000 122.759 0.018 122.777 ;
    END
  END rd_out[487]
  PIN rd_out[488]
    DIRECTION OUTPUT ;
    USE SIGNAL ;
    SHAPE ABUTMENT ;
    PORT
      LAYER M4 ;
      RECT 0.000 123.011 0.018 123.029 ;
    END
  END rd_out[488]
  PIN rd_out[489]
    DIRECTION OUTPUT ;
    USE SIGNAL ;
    SHAPE ABUTMENT ;
    PORT
      LAYER M4 ;
      RECT 0.000 123.263 0.018 123.281 ;
    END
  END rd_out[489]
  PIN rd_out[490]
    DIRECTION OUTPUT ;
    USE SIGNAL ;
    SHAPE ABUTMENT ;
    PORT
      LAYER M4 ;
      RECT 0.000 123.515 0.018 123.533 ;
    END
  END rd_out[490]
  PIN rd_out[491]
    DIRECTION OUTPUT ;
    USE SIGNAL ;
    SHAPE ABUTMENT ;
    PORT
      LAYER M4 ;
      RECT 0.000 123.767 0.018 123.785 ;
    END
  END rd_out[491]
  PIN rd_out[492]
    DIRECTION OUTPUT ;
    USE SIGNAL ;
    SHAPE ABUTMENT ;
    PORT
      LAYER M4 ;
      RECT 0.000 124.019 0.018 124.037 ;
    END
  END rd_out[492]
  PIN rd_out[493]
    DIRECTION OUTPUT ;
    USE SIGNAL ;
    SHAPE ABUTMENT ;
    PORT
      LAYER M4 ;
      RECT 0.000 124.271 0.018 124.289 ;
    END
  END rd_out[493]
  PIN rd_out[494]
    DIRECTION OUTPUT ;
    USE SIGNAL ;
    SHAPE ABUTMENT ;
    PORT
      LAYER M4 ;
      RECT 0.000 124.523 0.018 124.541 ;
    END
  END rd_out[494]
  PIN rd_out[495]
    DIRECTION OUTPUT ;
    USE SIGNAL ;
    SHAPE ABUTMENT ;
    PORT
      LAYER M4 ;
      RECT 0.000 124.775 0.018 124.793 ;
    END
  END rd_out[495]
  PIN rd_out[496]
    DIRECTION OUTPUT ;
    USE SIGNAL ;
    SHAPE ABUTMENT ;
    PORT
      LAYER M4 ;
      RECT 0.000 125.027 0.018 125.045 ;
    END
  END rd_out[496]
  PIN rd_out[497]
    DIRECTION OUTPUT ;
    USE SIGNAL ;
    SHAPE ABUTMENT ;
    PORT
      LAYER M4 ;
      RECT 0.000 125.279 0.018 125.297 ;
    END
  END rd_out[497]
  PIN rd_out[498]
    DIRECTION OUTPUT ;
    USE SIGNAL ;
    SHAPE ABUTMENT ;
    PORT
      LAYER M4 ;
      RECT 0.000 125.531 0.018 125.549 ;
    END
  END rd_out[498]
  PIN rd_out[499]
    DIRECTION OUTPUT ;
    USE SIGNAL ;
    SHAPE ABUTMENT ;
    PORT
      LAYER M4 ;
      RECT 0.000 125.783 0.018 125.801 ;
    END
  END rd_out[499]
  PIN rd_out[500]
    DIRECTION OUTPUT ;
    USE SIGNAL ;
    SHAPE ABUTMENT ;
    PORT
      LAYER M4 ;
      RECT 0.000 126.035 0.018 126.053 ;
    END
  END rd_out[500]
  PIN rd_out[501]
    DIRECTION OUTPUT ;
    USE SIGNAL ;
    SHAPE ABUTMENT ;
    PORT
      LAYER M4 ;
      RECT 0.000 126.287 0.018 126.305 ;
    END
  END rd_out[501]
  PIN rd_out[502]
    DIRECTION OUTPUT ;
    USE SIGNAL ;
    SHAPE ABUTMENT ;
    PORT
      LAYER M4 ;
      RECT 0.000 126.539 0.018 126.557 ;
    END
  END rd_out[502]
  PIN rd_out[503]
    DIRECTION OUTPUT ;
    USE SIGNAL ;
    SHAPE ABUTMENT ;
    PORT
      LAYER M4 ;
      RECT 0.000 126.791 0.018 126.809 ;
    END
  END rd_out[503]
  PIN rd_out[504]
    DIRECTION OUTPUT ;
    USE SIGNAL ;
    SHAPE ABUTMENT ;
    PORT
      LAYER M4 ;
      RECT 0.000 127.043 0.018 127.061 ;
    END
  END rd_out[504]
  PIN rd_out[505]
    DIRECTION OUTPUT ;
    USE SIGNAL ;
    SHAPE ABUTMENT ;
    PORT
      LAYER M4 ;
      RECT 0.000 127.295 0.018 127.313 ;
    END
  END rd_out[505]
  PIN rd_out[506]
    DIRECTION OUTPUT ;
    USE SIGNAL ;
    SHAPE ABUTMENT ;
    PORT
      LAYER M4 ;
      RECT 0.000 127.547 0.018 127.565 ;
    END
  END rd_out[506]
  PIN rd_out[507]
    DIRECTION OUTPUT ;
    USE SIGNAL ;
    SHAPE ABUTMENT ;
    PORT
      LAYER M4 ;
      RECT 0.000 127.799 0.018 127.817 ;
    END
  END rd_out[507]
  PIN rd_out[508]
    DIRECTION OUTPUT ;
    USE SIGNAL ;
    SHAPE ABUTMENT ;
    PORT
      LAYER M4 ;
      RECT 0.000 128.051 0.018 128.069 ;
    END
  END rd_out[508]
  PIN rd_out[509]
    DIRECTION OUTPUT ;
    USE SIGNAL ;
    SHAPE ABUTMENT ;
    PORT
      LAYER M4 ;
      RECT 0.000 128.303 0.018 128.321 ;
    END
  END rd_out[509]
  PIN rd_out[510]
    DIRECTION OUTPUT ;
    USE SIGNAL ;
    SHAPE ABUTMENT ;
    PORT
      LAYER M4 ;
      RECT 0.000 128.555 0.018 128.573 ;
    END
  END rd_out[510]
  PIN rd_out[511]
    DIRECTION OUTPUT ;
    USE SIGNAL ;
    SHAPE ABUTMENT ;
    PORT
      LAYER M4 ;
      RECT 0.000 128.807 0.018 128.825 ;
    END
  END rd_out[511]
  PIN wd_in[0]
    DIRECTION INPUT ;
    USE SIGNAL ;
    SHAPE ABUTMENT ;
    PORT
      LAYER M4 ;
      RECT 0.000 140.039 0.018 140.057 ;
    END
  END wd_in[0]
  PIN wd_in[1]
    DIRECTION INPUT ;
    USE SIGNAL ;
    SHAPE ABUTMENT ;
    PORT
      LAYER M4 ;
      RECT 0.000 140.291 0.018 140.309 ;
    END
  END wd_in[1]
  PIN wd_in[2]
    DIRECTION INPUT ;
    USE SIGNAL ;
    SHAPE ABUTMENT ;
    PORT
      LAYER M4 ;
      RECT 0.000 140.543 0.018 140.561 ;
    END
  END wd_in[2]
  PIN wd_in[3]
    DIRECTION INPUT ;
    USE SIGNAL ;
    SHAPE ABUTMENT ;
    PORT
      LAYER M4 ;
      RECT 0.000 140.795 0.018 140.813 ;
    END
  END wd_in[3]
  PIN wd_in[4]
    DIRECTION INPUT ;
    USE SIGNAL ;
    SHAPE ABUTMENT ;
    PORT
      LAYER M4 ;
      RECT 0.000 141.047 0.018 141.065 ;
    END
  END wd_in[4]
  PIN wd_in[5]
    DIRECTION INPUT ;
    USE SIGNAL ;
    SHAPE ABUTMENT ;
    PORT
      LAYER M4 ;
      RECT 0.000 141.299 0.018 141.317 ;
    END
  END wd_in[5]
  PIN wd_in[6]
    DIRECTION INPUT ;
    USE SIGNAL ;
    SHAPE ABUTMENT ;
    PORT
      LAYER M4 ;
      RECT 0.000 141.551 0.018 141.569 ;
    END
  END wd_in[6]
  PIN wd_in[7]
    DIRECTION INPUT ;
    USE SIGNAL ;
    SHAPE ABUTMENT ;
    PORT
      LAYER M4 ;
      RECT 0.000 141.803 0.018 141.821 ;
    END
  END wd_in[7]
  PIN wd_in[8]
    DIRECTION INPUT ;
    USE SIGNAL ;
    SHAPE ABUTMENT ;
    PORT
      LAYER M4 ;
      RECT 0.000 142.055 0.018 142.073 ;
    END
  END wd_in[8]
  PIN wd_in[9]
    DIRECTION INPUT ;
    USE SIGNAL ;
    SHAPE ABUTMENT ;
    PORT
      LAYER M4 ;
      RECT 0.000 142.307 0.018 142.325 ;
    END
  END wd_in[9]
  PIN wd_in[10]
    DIRECTION INPUT ;
    USE SIGNAL ;
    SHAPE ABUTMENT ;
    PORT
      LAYER M4 ;
      RECT 0.000 142.559 0.018 142.577 ;
    END
  END wd_in[10]
  PIN wd_in[11]
    DIRECTION INPUT ;
    USE SIGNAL ;
    SHAPE ABUTMENT ;
    PORT
      LAYER M4 ;
      RECT 0.000 142.811 0.018 142.829 ;
    END
  END wd_in[11]
  PIN wd_in[12]
    DIRECTION INPUT ;
    USE SIGNAL ;
    SHAPE ABUTMENT ;
    PORT
      LAYER M4 ;
      RECT 0.000 143.063 0.018 143.081 ;
    END
  END wd_in[12]
  PIN wd_in[13]
    DIRECTION INPUT ;
    USE SIGNAL ;
    SHAPE ABUTMENT ;
    PORT
      LAYER M4 ;
      RECT 0.000 143.315 0.018 143.333 ;
    END
  END wd_in[13]
  PIN wd_in[14]
    DIRECTION INPUT ;
    USE SIGNAL ;
    SHAPE ABUTMENT ;
    PORT
      LAYER M4 ;
      RECT 0.000 143.567 0.018 143.585 ;
    END
  END wd_in[14]
  PIN wd_in[15]
    DIRECTION INPUT ;
    USE SIGNAL ;
    SHAPE ABUTMENT ;
    PORT
      LAYER M4 ;
      RECT 0.000 143.819 0.018 143.837 ;
    END
  END wd_in[15]
  PIN wd_in[16]
    DIRECTION INPUT ;
    USE SIGNAL ;
    SHAPE ABUTMENT ;
    PORT
      LAYER M4 ;
      RECT 0.000 144.071 0.018 144.089 ;
    END
  END wd_in[16]
  PIN wd_in[17]
    DIRECTION INPUT ;
    USE SIGNAL ;
    SHAPE ABUTMENT ;
    PORT
      LAYER M4 ;
      RECT 0.000 144.323 0.018 144.341 ;
    END
  END wd_in[17]
  PIN wd_in[18]
    DIRECTION INPUT ;
    USE SIGNAL ;
    SHAPE ABUTMENT ;
    PORT
      LAYER M4 ;
      RECT 0.000 144.575 0.018 144.593 ;
    END
  END wd_in[18]
  PIN wd_in[19]
    DIRECTION INPUT ;
    USE SIGNAL ;
    SHAPE ABUTMENT ;
    PORT
      LAYER M4 ;
      RECT 0.000 144.827 0.018 144.845 ;
    END
  END wd_in[19]
  PIN wd_in[20]
    DIRECTION INPUT ;
    USE SIGNAL ;
    SHAPE ABUTMENT ;
    PORT
      LAYER M4 ;
      RECT 0.000 145.079 0.018 145.097 ;
    END
  END wd_in[20]
  PIN wd_in[21]
    DIRECTION INPUT ;
    USE SIGNAL ;
    SHAPE ABUTMENT ;
    PORT
      LAYER M4 ;
      RECT 0.000 145.331 0.018 145.349 ;
    END
  END wd_in[21]
  PIN wd_in[22]
    DIRECTION INPUT ;
    USE SIGNAL ;
    SHAPE ABUTMENT ;
    PORT
      LAYER M4 ;
      RECT 0.000 145.583 0.018 145.601 ;
    END
  END wd_in[22]
  PIN wd_in[23]
    DIRECTION INPUT ;
    USE SIGNAL ;
    SHAPE ABUTMENT ;
    PORT
      LAYER M4 ;
      RECT 0.000 145.835 0.018 145.853 ;
    END
  END wd_in[23]
  PIN wd_in[24]
    DIRECTION INPUT ;
    USE SIGNAL ;
    SHAPE ABUTMENT ;
    PORT
      LAYER M4 ;
      RECT 0.000 146.087 0.018 146.105 ;
    END
  END wd_in[24]
  PIN wd_in[25]
    DIRECTION INPUT ;
    USE SIGNAL ;
    SHAPE ABUTMENT ;
    PORT
      LAYER M4 ;
      RECT 0.000 146.339 0.018 146.357 ;
    END
  END wd_in[25]
  PIN wd_in[26]
    DIRECTION INPUT ;
    USE SIGNAL ;
    SHAPE ABUTMENT ;
    PORT
      LAYER M4 ;
      RECT 0.000 146.591 0.018 146.609 ;
    END
  END wd_in[26]
  PIN wd_in[27]
    DIRECTION INPUT ;
    USE SIGNAL ;
    SHAPE ABUTMENT ;
    PORT
      LAYER M4 ;
      RECT 0.000 146.843 0.018 146.861 ;
    END
  END wd_in[27]
  PIN wd_in[28]
    DIRECTION INPUT ;
    USE SIGNAL ;
    SHAPE ABUTMENT ;
    PORT
      LAYER M4 ;
      RECT 0.000 147.095 0.018 147.113 ;
    END
  END wd_in[28]
  PIN wd_in[29]
    DIRECTION INPUT ;
    USE SIGNAL ;
    SHAPE ABUTMENT ;
    PORT
      LAYER M4 ;
      RECT 0.000 147.347 0.018 147.365 ;
    END
  END wd_in[29]
  PIN wd_in[30]
    DIRECTION INPUT ;
    USE SIGNAL ;
    SHAPE ABUTMENT ;
    PORT
      LAYER M4 ;
      RECT 0.000 147.599 0.018 147.617 ;
    END
  END wd_in[30]
  PIN wd_in[31]
    DIRECTION INPUT ;
    USE SIGNAL ;
    SHAPE ABUTMENT ;
    PORT
      LAYER M4 ;
      RECT 0.000 147.851 0.018 147.869 ;
    END
  END wd_in[31]
  PIN wd_in[32]
    DIRECTION INPUT ;
    USE SIGNAL ;
    SHAPE ABUTMENT ;
    PORT
      LAYER M4 ;
      RECT 0.000 148.103 0.018 148.121 ;
    END
  END wd_in[32]
  PIN wd_in[33]
    DIRECTION INPUT ;
    USE SIGNAL ;
    SHAPE ABUTMENT ;
    PORT
      LAYER M4 ;
      RECT 0.000 148.355 0.018 148.373 ;
    END
  END wd_in[33]
  PIN wd_in[34]
    DIRECTION INPUT ;
    USE SIGNAL ;
    SHAPE ABUTMENT ;
    PORT
      LAYER M4 ;
      RECT 0.000 148.607 0.018 148.625 ;
    END
  END wd_in[34]
  PIN wd_in[35]
    DIRECTION INPUT ;
    USE SIGNAL ;
    SHAPE ABUTMENT ;
    PORT
      LAYER M4 ;
      RECT 0.000 148.859 0.018 148.877 ;
    END
  END wd_in[35]
  PIN wd_in[36]
    DIRECTION INPUT ;
    USE SIGNAL ;
    SHAPE ABUTMENT ;
    PORT
      LAYER M4 ;
      RECT 0.000 149.111 0.018 149.129 ;
    END
  END wd_in[36]
  PIN wd_in[37]
    DIRECTION INPUT ;
    USE SIGNAL ;
    SHAPE ABUTMENT ;
    PORT
      LAYER M4 ;
      RECT 0.000 149.363 0.018 149.381 ;
    END
  END wd_in[37]
  PIN wd_in[38]
    DIRECTION INPUT ;
    USE SIGNAL ;
    SHAPE ABUTMENT ;
    PORT
      LAYER M4 ;
      RECT 0.000 149.615 0.018 149.633 ;
    END
  END wd_in[38]
  PIN wd_in[39]
    DIRECTION INPUT ;
    USE SIGNAL ;
    SHAPE ABUTMENT ;
    PORT
      LAYER M4 ;
      RECT 0.000 149.867 0.018 149.885 ;
    END
  END wd_in[39]
  PIN wd_in[40]
    DIRECTION INPUT ;
    USE SIGNAL ;
    SHAPE ABUTMENT ;
    PORT
      LAYER M4 ;
      RECT 0.000 150.119 0.018 150.137 ;
    END
  END wd_in[40]
  PIN wd_in[41]
    DIRECTION INPUT ;
    USE SIGNAL ;
    SHAPE ABUTMENT ;
    PORT
      LAYER M4 ;
      RECT 0.000 150.371 0.018 150.389 ;
    END
  END wd_in[41]
  PIN wd_in[42]
    DIRECTION INPUT ;
    USE SIGNAL ;
    SHAPE ABUTMENT ;
    PORT
      LAYER M4 ;
      RECT 0.000 150.623 0.018 150.641 ;
    END
  END wd_in[42]
  PIN wd_in[43]
    DIRECTION INPUT ;
    USE SIGNAL ;
    SHAPE ABUTMENT ;
    PORT
      LAYER M4 ;
      RECT 0.000 150.875 0.018 150.893 ;
    END
  END wd_in[43]
  PIN wd_in[44]
    DIRECTION INPUT ;
    USE SIGNAL ;
    SHAPE ABUTMENT ;
    PORT
      LAYER M4 ;
      RECT 0.000 151.127 0.018 151.145 ;
    END
  END wd_in[44]
  PIN wd_in[45]
    DIRECTION INPUT ;
    USE SIGNAL ;
    SHAPE ABUTMENT ;
    PORT
      LAYER M4 ;
      RECT 0.000 151.379 0.018 151.397 ;
    END
  END wd_in[45]
  PIN wd_in[46]
    DIRECTION INPUT ;
    USE SIGNAL ;
    SHAPE ABUTMENT ;
    PORT
      LAYER M4 ;
      RECT 0.000 151.631 0.018 151.649 ;
    END
  END wd_in[46]
  PIN wd_in[47]
    DIRECTION INPUT ;
    USE SIGNAL ;
    SHAPE ABUTMENT ;
    PORT
      LAYER M4 ;
      RECT 0.000 151.883 0.018 151.901 ;
    END
  END wd_in[47]
  PIN wd_in[48]
    DIRECTION INPUT ;
    USE SIGNAL ;
    SHAPE ABUTMENT ;
    PORT
      LAYER M4 ;
      RECT 0.000 152.135 0.018 152.153 ;
    END
  END wd_in[48]
  PIN wd_in[49]
    DIRECTION INPUT ;
    USE SIGNAL ;
    SHAPE ABUTMENT ;
    PORT
      LAYER M4 ;
      RECT 0.000 152.387 0.018 152.405 ;
    END
  END wd_in[49]
  PIN wd_in[50]
    DIRECTION INPUT ;
    USE SIGNAL ;
    SHAPE ABUTMENT ;
    PORT
      LAYER M4 ;
      RECT 0.000 152.639 0.018 152.657 ;
    END
  END wd_in[50]
  PIN wd_in[51]
    DIRECTION INPUT ;
    USE SIGNAL ;
    SHAPE ABUTMENT ;
    PORT
      LAYER M4 ;
      RECT 0.000 152.891 0.018 152.909 ;
    END
  END wd_in[51]
  PIN wd_in[52]
    DIRECTION INPUT ;
    USE SIGNAL ;
    SHAPE ABUTMENT ;
    PORT
      LAYER M4 ;
      RECT 0.000 153.143 0.018 153.161 ;
    END
  END wd_in[52]
  PIN wd_in[53]
    DIRECTION INPUT ;
    USE SIGNAL ;
    SHAPE ABUTMENT ;
    PORT
      LAYER M4 ;
      RECT 0.000 153.395 0.018 153.413 ;
    END
  END wd_in[53]
  PIN wd_in[54]
    DIRECTION INPUT ;
    USE SIGNAL ;
    SHAPE ABUTMENT ;
    PORT
      LAYER M4 ;
      RECT 0.000 153.647 0.018 153.665 ;
    END
  END wd_in[54]
  PIN wd_in[55]
    DIRECTION INPUT ;
    USE SIGNAL ;
    SHAPE ABUTMENT ;
    PORT
      LAYER M4 ;
      RECT 0.000 153.899 0.018 153.917 ;
    END
  END wd_in[55]
  PIN wd_in[56]
    DIRECTION INPUT ;
    USE SIGNAL ;
    SHAPE ABUTMENT ;
    PORT
      LAYER M4 ;
      RECT 0.000 154.151 0.018 154.169 ;
    END
  END wd_in[56]
  PIN wd_in[57]
    DIRECTION INPUT ;
    USE SIGNAL ;
    SHAPE ABUTMENT ;
    PORT
      LAYER M4 ;
      RECT 0.000 154.403 0.018 154.421 ;
    END
  END wd_in[57]
  PIN wd_in[58]
    DIRECTION INPUT ;
    USE SIGNAL ;
    SHAPE ABUTMENT ;
    PORT
      LAYER M4 ;
      RECT 0.000 154.655 0.018 154.673 ;
    END
  END wd_in[58]
  PIN wd_in[59]
    DIRECTION INPUT ;
    USE SIGNAL ;
    SHAPE ABUTMENT ;
    PORT
      LAYER M4 ;
      RECT 0.000 154.907 0.018 154.925 ;
    END
  END wd_in[59]
  PIN wd_in[60]
    DIRECTION INPUT ;
    USE SIGNAL ;
    SHAPE ABUTMENT ;
    PORT
      LAYER M4 ;
      RECT 0.000 155.159 0.018 155.177 ;
    END
  END wd_in[60]
  PIN wd_in[61]
    DIRECTION INPUT ;
    USE SIGNAL ;
    SHAPE ABUTMENT ;
    PORT
      LAYER M4 ;
      RECT 0.000 155.411 0.018 155.429 ;
    END
  END wd_in[61]
  PIN wd_in[62]
    DIRECTION INPUT ;
    USE SIGNAL ;
    SHAPE ABUTMENT ;
    PORT
      LAYER M4 ;
      RECT 0.000 155.663 0.018 155.681 ;
    END
  END wd_in[62]
  PIN wd_in[63]
    DIRECTION INPUT ;
    USE SIGNAL ;
    SHAPE ABUTMENT ;
    PORT
      LAYER M4 ;
      RECT 0.000 155.915 0.018 155.933 ;
    END
  END wd_in[63]
  PIN wd_in[64]
    DIRECTION INPUT ;
    USE SIGNAL ;
    SHAPE ABUTMENT ;
    PORT
      LAYER M4 ;
      RECT 0.000 156.167 0.018 156.185 ;
    END
  END wd_in[64]
  PIN wd_in[65]
    DIRECTION INPUT ;
    USE SIGNAL ;
    SHAPE ABUTMENT ;
    PORT
      LAYER M4 ;
      RECT 0.000 156.419 0.018 156.437 ;
    END
  END wd_in[65]
  PIN wd_in[66]
    DIRECTION INPUT ;
    USE SIGNAL ;
    SHAPE ABUTMENT ;
    PORT
      LAYER M4 ;
      RECT 0.000 156.671 0.018 156.689 ;
    END
  END wd_in[66]
  PIN wd_in[67]
    DIRECTION INPUT ;
    USE SIGNAL ;
    SHAPE ABUTMENT ;
    PORT
      LAYER M4 ;
      RECT 0.000 156.923 0.018 156.941 ;
    END
  END wd_in[67]
  PIN wd_in[68]
    DIRECTION INPUT ;
    USE SIGNAL ;
    SHAPE ABUTMENT ;
    PORT
      LAYER M4 ;
      RECT 0.000 157.175 0.018 157.193 ;
    END
  END wd_in[68]
  PIN wd_in[69]
    DIRECTION INPUT ;
    USE SIGNAL ;
    SHAPE ABUTMENT ;
    PORT
      LAYER M4 ;
      RECT 0.000 157.427 0.018 157.445 ;
    END
  END wd_in[69]
  PIN wd_in[70]
    DIRECTION INPUT ;
    USE SIGNAL ;
    SHAPE ABUTMENT ;
    PORT
      LAYER M4 ;
      RECT 0.000 157.679 0.018 157.697 ;
    END
  END wd_in[70]
  PIN wd_in[71]
    DIRECTION INPUT ;
    USE SIGNAL ;
    SHAPE ABUTMENT ;
    PORT
      LAYER M4 ;
      RECT 0.000 157.931 0.018 157.949 ;
    END
  END wd_in[71]
  PIN wd_in[72]
    DIRECTION INPUT ;
    USE SIGNAL ;
    SHAPE ABUTMENT ;
    PORT
      LAYER M4 ;
      RECT 0.000 158.183 0.018 158.201 ;
    END
  END wd_in[72]
  PIN wd_in[73]
    DIRECTION INPUT ;
    USE SIGNAL ;
    SHAPE ABUTMENT ;
    PORT
      LAYER M4 ;
      RECT 0.000 158.435 0.018 158.453 ;
    END
  END wd_in[73]
  PIN wd_in[74]
    DIRECTION INPUT ;
    USE SIGNAL ;
    SHAPE ABUTMENT ;
    PORT
      LAYER M4 ;
      RECT 0.000 158.687 0.018 158.705 ;
    END
  END wd_in[74]
  PIN wd_in[75]
    DIRECTION INPUT ;
    USE SIGNAL ;
    SHAPE ABUTMENT ;
    PORT
      LAYER M4 ;
      RECT 0.000 158.939 0.018 158.957 ;
    END
  END wd_in[75]
  PIN wd_in[76]
    DIRECTION INPUT ;
    USE SIGNAL ;
    SHAPE ABUTMENT ;
    PORT
      LAYER M4 ;
      RECT 0.000 159.191 0.018 159.209 ;
    END
  END wd_in[76]
  PIN wd_in[77]
    DIRECTION INPUT ;
    USE SIGNAL ;
    SHAPE ABUTMENT ;
    PORT
      LAYER M4 ;
      RECT 0.000 159.443 0.018 159.461 ;
    END
  END wd_in[77]
  PIN wd_in[78]
    DIRECTION INPUT ;
    USE SIGNAL ;
    SHAPE ABUTMENT ;
    PORT
      LAYER M4 ;
      RECT 0.000 159.695 0.018 159.713 ;
    END
  END wd_in[78]
  PIN wd_in[79]
    DIRECTION INPUT ;
    USE SIGNAL ;
    SHAPE ABUTMENT ;
    PORT
      LAYER M4 ;
      RECT 0.000 159.947 0.018 159.965 ;
    END
  END wd_in[79]
  PIN wd_in[80]
    DIRECTION INPUT ;
    USE SIGNAL ;
    SHAPE ABUTMENT ;
    PORT
      LAYER M4 ;
      RECT 0.000 160.199 0.018 160.217 ;
    END
  END wd_in[80]
  PIN wd_in[81]
    DIRECTION INPUT ;
    USE SIGNAL ;
    SHAPE ABUTMENT ;
    PORT
      LAYER M4 ;
      RECT 0.000 160.451 0.018 160.469 ;
    END
  END wd_in[81]
  PIN wd_in[82]
    DIRECTION INPUT ;
    USE SIGNAL ;
    SHAPE ABUTMENT ;
    PORT
      LAYER M4 ;
      RECT 0.000 160.703 0.018 160.721 ;
    END
  END wd_in[82]
  PIN wd_in[83]
    DIRECTION INPUT ;
    USE SIGNAL ;
    SHAPE ABUTMENT ;
    PORT
      LAYER M4 ;
      RECT 0.000 160.955 0.018 160.973 ;
    END
  END wd_in[83]
  PIN wd_in[84]
    DIRECTION INPUT ;
    USE SIGNAL ;
    SHAPE ABUTMENT ;
    PORT
      LAYER M4 ;
      RECT 0.000 161.207 0.018 161.225 ;
    END
  END wd_in[84]
  PIN wd_in[85]
    DIRECTION INPUT ;
    USE SIGNAL ;
    SHAPE ABUTMENT ;
    PORT
      LAYER M4 ;
      RECT 0.000 161.459 0.018 161.477 ;
    END
  END wd_in[85]
  PIN wd_in[86]
    DIRECTION INPUT ;
    USE SIGNAL ;
    SHAPE ABUTMENT ;
    PORT
      LAYER M4 ;
      RECT 0.000 161.711 0.018 161.729 ;
    END
  END wd_in[86]
  PIN wd_in[87]
    DIRECTION INPUT ;
    USE SIGNAL ;
    SHAPE ABUTMENT ;
    PORT
      LAYER M4 ;
      RECT 0.000 161.963 0.018 161.981 ;
    END
  END wd_in[87]
  PIN wd_in[88]
    DIRECTION INPUT ;
    USE SIGNAL ;
    SHAPE ABUTMENT ;
    PORT
      LAYER M4 ;
      RECT 0.000 162.215 0.018 162.233 ;
    END
  END wd_in[88]
  PIN wd_in[89]
    DIRECTION INPUT ;
    USE SIGNAL ;
    SHAPE ABUTMENT ;
    PORT
      LAYER M4 ;
      RECT 0.000 162.467 0.018 162.485 ;
    END
  END wd_in[89]
  PIN wd_in[90]
    DIRECTION INPUT ;
    USE SIGNAL ;
    SHAPE ABUTMENT ;
    PORT
      LAYER M4 ;
      RECT 0.000 162.719 0.018 162.737 ;
    END
  END wd_in[90]
  PIN wd_in[91]
    DIRECTION INPUT ;
    USE SIGNAL ;
    SHAPE ABUTMENT ;
    PORT
      LAYER M4 ;
      RECT 0.000 162.971 0.018 162.989 ;
    END
  END wd_in[91]
  PIN wd_in[92]
    DIRECTION INPUT ;
    USE SIGNAL ;
    SHAPE ABUTMENT ;
    PORT
      LAYER M4 ;
      RECT 0.000 163.223 0.018 163.241 ;
    END
  END wd_in[92]
  PIN wd_in[93]
    DIRECTION INPUT ;
    USE SIGNAL ;
    SHAPE ABUTMENT ;
    PORT
      LAYER M4 ;
      RECT 0.000 163.475 0.018 163.493 ;
    END
  END wd_in[93]
  PIN wd_in[94]
    DIRECTION INPUT ;
    USE SIGNAL ;
    SHAPE ABUTMENT ;
    PORT
      LAYER M4 ;
      RECT 0.000 163.727 0.018 163.745 ;
    END
  END wd_in[94]
  PIN wd_in[95]
    DIRECTION INPUT ;
    USE SIGNAL ;
    SHAPE ABUTMENT ;
    PORT
      LAYER M4 ;
      RECT 0.000 163.979 0.018 163.997 ;
    END
  END wd_in[95]
  PIN wd_in[96]
    DIRECTION INPUT ;
    USE SIGNAL ;
    SHAPE ABUTMENT ;
    PORT
      LAYER M4 ;
      RECT 0.000 164.231 0.018 164.249 ;
    END
  END wd_in[96]
  PIN wd_in[97]
    DIRECTION INPUT ;
    USE SIGNAL ;
    SHAPE ABUTMENT ;
    PORT
      LAYER M4 ;
      RECT 0.000 164.483 0.018 164.501 ;
    END
  END wd_in[97]
  PIN wd_in[98]
    DIRECTION INPUT ;
    USE SIGNAL ;
    SHAPE ABUTMENT ;
    PORT
      LAYER M4 ;
      RECT 0.000 164.735 0.018 164.753 ;
    END
  END wd_in[98]
  PIN wd_in[99]
    DIRECTION INPUT ;
    USE SIGNAL ;
    SHAPE ABUTMENT ;
    PORT
      LAYER M4 ;
      RECT 0.000 164.987 0.018 165.005 ;
    END
  END wd_in[99]
  PIN wd_in[100]
    DIRECTION INPUT ;
    USE SIGNAL ;
    SHAPE ABUTMENT ;
    PORT
      LAYER M4 ;
      RECT 0.000 165.239 0.018 165.257 ;
    END
  END wd_in[100]
  PIN wd_in[101]
    DIRECTION INPUT ;
    USE SIGNAL ;
    SHAPE ABUTMENT ;
    PORT
      LAYER M4 ;
      RECT 0.000 165.491 0.018 165.509 ;
    END
  END wd_in[101]
  PIN wd_in[102]
    DIRECTION INPUT ;
    USE SIGNAL ;
    SHAPE ABUTMENT ;
    PORT
      LAYER M4 ;
      RECT 0.000 165.743 0.018 165.761 ;
    END
  END wd_in[102]
  PIN wd_in[103]
    DIRECTION INPUT ;
    USE SIGNAL ;
    SHAPE ABUTMENT ;
    PORT
      LAYER M4 ;
      RECT 0.000 165.995 0.018 166.013 ;
    END
  END wd_in[103]
  PIN wd_in[104]
    DIRECTION INPUT ;
    USE SIGNAL ;
    SHAPE ABUTMENT ;
    PORT
      LAYER M4 ;
      RECT 0.000 166.247 0.018 166.265 ;
    END
  END wd_in[104]
  PIN wd_in[105]
    DIRECTION INPUT ;
    USE SIGNAL ;
    SHAPE ABUTMENT ;
    PORT
      LAYER M4 ;
      RECT 0.000 166.499 0.018 166.517 ;
    END
  END wd_in[105]
  PIN wd_in[106]
    DIRECTION INPUT ;
    USE SIGNAL ;
    SHAPE ABUTMENT ;
    PORT
      LAYER M4 ;
      RECT 0.000 166.751 0.018 166.769 ;
    END
  END wd_in[106]
  PIN wd_in[107]
    DIRECTION INPUT ;
    USE SIGNAL ;
    SHAPE ABUTMENT ;
    PORT
      LAYER M4 ;
      RECT 0.000 167.003 0.018 167.021 ;
    END
  END wd_in[107]
  PIN wd_in[108]
    DIRECTION INPUT ;
    USE SIGNAL ;
    SHAPE ABUTMENT ;
    PORT
      LAYER M4 ;
      RECT 0.000 167.255 0.018 167.273 ;
    END
  END wd_in[108]
  PIN wd_in[109]
    DIRECTION INPUT ;
    USE SIGNAL ;
    SHAPE ABUTMENT ;
    PORT
      LAYER M4 ;
      RECT 0.000 167.507 0.018 167.525 ;
    END
  END wd_in[109]
  PIN wd_in[110]
    DIRECTION INPUT ;
    USE SIGNAL ;
    SHAPE ABUTMENT ;
    PORT
      LAYER M4 ;
      RECT 0.000 167.759 0.018 167.777 ;
    END
  END wd_in[110]
  PIN wd_in[111]
    DIRECTION INPUT ;
    USE SIGNAL ;
    SHAPE ABUTMENT ;
    PORT
      LAYER M4 ;
      RECT 0.000 168.011 0.018 168.029 ;
    END
  END wd_in[111]
  PIN wd_in[112]
    DIRECTION INPUT ;
    USE SIGNAL ;
    SHAPE ABUTMENT ;
    PORT
      LAYER M4 ;
      RECT 0.000 168.263 0.018 168.281 ;
    END
  END wd_in[112]
  PIN wd_in[113]
    DIRECTION INPUT ;
    USE SIGNAL ;
    SHAPE ABUTMENT ;
    PORT
      LAYER M4 ;
      RECT 0.000 168.515 0.018 168.533 ;
    END
  END wd_in[113]
  PIN wd_in[114]
    DIRECTION INPUT ;
    USE SIGNAL ;
    SHAPE ABUTMENT ;
    PORT
      LAYER M4 ;
      RECT 0.000 168.767 0.018 168.785 ;
    END
  END wd_in[114]
  PIN wd_in[115]
    DIRECTION INPUT ;
    USE SIGNAL ;
    SHAPE ABUTMENT ;
    PORT
      LAYER M4 ;
      RECT 0.000 169.019 0.018 169.037 ;
    END
  END wd_in[115]
  PIN wd_in[116]
    DIRECTION INPUT ;
    USE SIGNAL ;
    SHAPE ABUTMENT ;
    PORT
      LAYER M4 ;
      RECT 0.000 169.271 0.018 169.289 ;
    END
  END wd_in[116]
  PIN wd_in[117]
    DIRECTION INPUT ;
    USE SIGNAL ;
    SHAPE ABUTMENT ;
    PORT
      LAYER M4 ;
      RECT 0.000 169.523 0.018 169.541 ;
    END
  END wd_in[117]
  PIN wd_in[118]
    DIRECTION INPUT ;
    USE SIGNAL ;
    SHAPE ABUTMENT ;
    PORT
      LAYER M4 ;
      RECT 0.000 169.775 0.018 169.793 ;
    END
  END wd_in[118]
  PIN wd_in[119]
    DIRECTION INPUT ;
    USE SIGNAL ;
    SHAPE ABUTMENT ;
    PORT
      LAYER M4 ;
      RECT 0.000 170.027 0.018 170.045 ;
    END
  END wd_in[119]
  PIN wd_in[120]
    DIRECTION INPUT ;
    USE SIGNAL ;
    SHAPE ABUTMENT ;
    PORT
      LAYER M4 ;
      RECT 0.000 170.279 0.018 170.297 ;
    END
  END wd_in[120]
  PIN wd_in[121]
    DIRECTION INPUT ;
    USE SIGNAL ;
    SHAPE ABUTMENT ;
    PORT
      LAYER M4 ;
      RECT 0.000 170.531 0.018 170.549 ;
    END
  END wd_in[121]
  PIN wd_in[122]
    DIRECTION INPUT ;
    USE SIGNAL ;
    SHAPE ABUTMENT ;
    PORT
      LAYER M4 ;
      RECT 0.000 170.783 0.018 170.801 ;
    END
  END wd_in[122]
  PIN wd_in[123]
    DIRECTION INPUT ;
    USE SIGNAL ;
    SHAPE ABUTMENT ;
    PORT
      LAYER M4 ;
      RECT 0.000 171.035 0.018 171.053 ;
    END
  END wd_in[123]
  PIN wd_in[124]
    DIRECTION INPUT ;
    USE SIGNAL ;
    SHAPE ABUTMENT ;
    PORT
      LAYER M4 ;
      RECT 0.000 171.287 0.018 171.305 ;
    END
  END wd_in[124]
  PIN wd_in[125]
    DIRECTION INPUT ;
    USE SIGNAL ;
    SHAPE ABUTMENT ;
    PORT
      LAYER M4 ;
      RECT 0.000 171.539 0.018 171.557 ;
    END
  END wd_in[125]
  PIN wd_in[126]
    DIRECTION INPUT ;
    USE SIGNAL ;
    SHAPE ABUTMENT ;
    PORT
      LAYER M4 ;
      RECT 0.000 171.791 0.018 171.809 ;
    END
  END wd_in[126]
  PIN wd_in[127]
    DIRECTION INPUT ;
    USE SIGNAL ;
    SHAPE ABUTMENT ;
    PORT
      LAYER M4 ;
      RECT 0.000 172.043 0.018 172.061 ;
    END
  END wd_in[127]
  PIN wd_in[128]
    DIRECTION INPUT ;
    USE SIGNAL ;
    SHAPE ABUTMENT ;
    PORT
      LAYER M4 ;
      RECT 0.000 172.295 0.018 172.313 ;
    END
  END wd_in[128]
  PIN wd_in[129]
    DIRECTION INPUT ;
    USE SIGNAL ;
    SHAPE ABUTMENT ;
    PORT
      LAYER M4 ;
      RECT 0.000 172.547 0.018 172.565 ;
    END
  END wd_in[129]
  PIN wd_in[130]
    DIRECTION INPUT ;
    USE SIGNAL ;
    SHAPE ABUTMENT ;
    PORT
      LAYER M4 ;
      RECT 0.000 172.799 0.018 172.817 ;
    END
  END wd_in[130]
  PIN wd_in[131]
    DIRECTION INPUT ;
    USE SIGNAL ;
    SHAPE ABUTMENT ;
    PORT
      LAYER M4 ;
      RECT 0.000 173.051 0.018 173.069 ;
    END
  END wd_in[131]
  PIN wd_in[132]
    DIRECTION INPUT ;
    USE SIGNAL ;
    SHAPE ABUTMENT ;
    PORT
      LAYER M4 ;
      RECT 0.000 173.303 0.018 173.321 ;
    END
  END wd_in[132]
  PIN wd_in[133]
    DIRECTION INPUT ;
    USE SIGNAL ;
    SHAPE ABUTMENT ;
    PORT
      LAYER M4 ;
      RECT 0.000 173.555 0.018 173.573 ;
    END
  END wd_in[133]
  PIN wd_in[134]
    DIRECTION INPUT ;
    USE SIGNAL ;
    SHAPE ABUTMENT ;
    PORT
      LAYER M4 ;
      RECT 0.000 173.807 0.018 173.825 ;
    END
  END wd_in[134]
  PIN wd_in[135]
    DIRECTION INPUT ;
    USE SIGNAL ;
    SHAPE ABUTMENT ;
    PORT
      LAYER M4 ;
      RECT 0.000 174.059 0.018 174.077 ;
    END
  END wd_in[135]
  PIN wd_in[136]
    DIRECTION INPUT ;
    USE SIGNAL ;
    SHAPE ABUTMENT ;
    PORT
      LAYER M4 ;
      RECT 0.000 174.311 0.018 174.329 ;
    END
  END wd_in[136]
  PIN wd_in[137]
    DIRECTION INPUT ;
    USE SIGNAL ;
    SHAPE ABUTMENT ;
    PORT
      LAYER M4 ;
      RECT 0.000 174.563 0.018 174.581 ;
    END
  END wd_in[137]
  PIN wd_in[138]
    DIRECTION INPUT ;
    USE SIGNAL ;
    SHAPE ABUTMENT ;
    PORT
      LAYER M4 ;
      RECT 0.000 174.815 0.018 174.833 ;
    END
  END wd_in[138]
  PIN wd_in[139]
    DIRECTION INPUT ;
    USE SIGNAL ;
    SHAPE ABUTMENT ;
    PORT
      LAYER M4 ;
      RECT 0.000 175.067 0.018 175.085 ;
    END
  END wd_in[139]
  PIN wd_in[140]
    DIRECTION INPUT ;
    USE SIGNAL ;
    SHAPE ABUTMENT ;
    PORT
      LAYER M4 ;
      RECT 0.000 175.319 0.018 175.337 ;
    END
  END wd_in[140]
  PIN wd_in[141]
    DIRECTION INPUT ;
    USE SIGNAL ;
    SHAPE ABUTMENT ;
    PORT
      LAYER M4 ;
      RECT 0.000 175.571 0.018 175.589 ;
    END
  END wd_in[141]
  PIN wd_in[142]
    DIRECTION INPUT ;
    USE SIGNAL ;
    SHAPE ABUTMENT ;
    PORT
      LAYER M4 ;
      RECT 0.000 175.823 0.018 175.841 ;
    END
  END wd_in[142]
  PIN wd_in[143]
    DIRECTION INPUT ;
    USE SIGNAL ;
    SHAPE ABUTMENT ;
    PORT
      LAYER M4 ;
      RECT 0.000 176.075 0.018 176.093 ;
    END
  END wd_in[143]
  PIN wd_in[144]
    DIRECTION INPUT ;
    USE SIGNAL ;
    SHAPE ABUTMENT ;
    PORT
      LAYER M4 ;
      RECT 0.000 176.327 0.018 176.345 ;
    END
  END wd_in[144]
  PIN wd_in[145]
    DIRECTION INPUT ;
    USE SIGNAL ;
    SHAPE ABUTMENT ;
    PORT
      LAYER M4 ;
      RECT 0.000 176.579 0.018 176.597 ;
    END
  END wd_in[145]
  PIN wd_in[146]
    DIRECTION INPUT ;
    USE SIGNAL ;
    SHAPE ABUTMENT ;
    PORT
      LAYER M4 ;
      RECT 0.000 176.831 0.018 176.849 ;
    END
  END wd_in[146]
  PIN wd_in[147]
    DIRECTION INPUT ;
    USE SIGNAL ;
    SHAPE ABUTMENT ;
    PORT
      LAYER M4 ;
      RECT 0.000 177.083 0.018 177.101 ;
    END
  END wd_in[147]
  PIN wd_in[148]
    DIRECTION INPUT ;
    USE SIGNAL ;
    SHAPE ABUTMENT ;
    PORT
      LAYER M4 ;
      RECT 0.000 177.335 0.018 177.353 ;
    END
  END wd_in[148]
  PIN wd_in[149]
    DIRECTION INPUT ;
    USE SIGNAL ;
    SHAPE ABUTMENT ;
    PORT
      LAYER M4 ;
      RECT 0.000 177.587 0.018 177.605 ;
    END
  END wd_in[149]
  PIN wd_in[150]
    DIRECTION INPUT ;
    USE SIGNAL ;
    SHAPE ABUTMENT ;
    PORT
      LAYER M4 ;
      RECT 0.000 177.839 0.018 177.857 ;
    END
  END wd_in[150]
  PIN wd_in[151]
    DIRECTION INPUT ;
    USE SIGNAL ;
    SHAPE ABUTMENT ;
    PORT
      LAYER M4 ;
      RECT 0.000 178.091 0.018 178.109 ;
    END
  END wd_in[151]
  PIN wd_in[152]
    DIRECTION INPUT ;
    USE SIGNAL ;
    SHAPE ABUTMENT ;
    PORT
      LAYER M4 ;
      RECT 0.000 178.343 0.018 178.361 ;
    END
  END wd_in[152]
  PIN wd_in[153]
    DIRECTION INPUT ;
    USE SIGNAL ;
    SHAPE ABUTMENT ;
    PORT
      LAYER M4 ;
      RECT 0.000 178.595 0.018 178.613 ;
    END
  END wd_in[153]
  PIN wd_in[154]
    DIRECTION INPUT ;
    USE SIGNAL ;
    SHAPE ABUTMENT ;
    PORT
      LAYER M4 ;
      RECT 0.000 178.847 0.018 178.865 ;
    END
  END wd_in[154]
  PIN wd_in[155]
    DIRECTION INPUT ;
    USE SIGNAL ;
    SHAPE ABUTMENT ;
    PORT
      LAYER M4 ;
      RECT 0.000 179.099 0.018 179.117 ;
    END
  END wd_in[155]
  PIN wd_in[156]
    DIRECTION INPUT ;
    USE SIGNAL ;
    SHAPE ABUTMENT ;
    PORT
      LAYER M4 ;
      RECT 0.000 179.351 0.018 179.369 ;
    END
  END wd_in[156]
  PIN wd_in[157]
    DIRECTION INPUT ;
    USE SIGNAL ;
    SHAPE ABUTMENT ;
    PORT
      LAYER M4 ;
      RECT 0.000 179.603 0.018 179.621 ;
    END
  END wd_in[157]
  PIN wd_in[158]
    DIRECTION INPUT ;
    USE SIGNAL ;
    SHAPE ABUTMENT ;
    PORT
      LAYER M4 ;
      RECT 0.000 179.855 0.018 179.873 ;
    END
  END wd_in[158]
  PIN wd_in[159]
    DIRECTION INPUT ;
    USE SIGNAL ;
    SHAPE ABUTMENT ;
    PORT
      LAYER M4 ;
      RECT 0.000 180.107 0.018 180.125 ;
    END
  END wd_in[159]
  PIN wd_in[160]
    DIRECTION INPUT ;
    USE SIGNAL ;
    SHAPE ABUTMENT ;
    PORT
      LAYER M4 ;
      RECT 0.000 180.359 0.018 180.377 ;
    END
  END wd_in[160]
  PIN wd_in[161]
    DIRECTION INPUT ;
    USE SIGNAL ;
    SHAPE ABUTMENT ;
    PORT
      LAYER M4 ;
      RECT 0.000 180.611 0.018 180.629 ;
    END
  END wd_in[161]
  PIN wd_in[162]
    DIRECTION INPUT ;
    USE SIGNAL ;
    SHAPE ABUTMENT ;
    PORT
      LAYER M4 ;
      RECT 0.000 180.863 0.018 180.881 ;
    END
  END wd_in[162]
  PIN wd_in[163]
    DIRECTION INPUT ;
    USE SIGNAL ;
    SHAPE ABUTMENT ;
    PORT
      LAYER M4 ;
      RECT 0.000 181.115 0.018 181.133 ;
    END
  END wd_in[163]
  PIN wd_in[164]
    DIRECTION INPUT ;
    USE SIGNAL ;
    SHAPE ABUTMENT ;
    PORT
      LAYER M4 ;
      RECT 0.000 181.367 0.018 181.385 ;
    END
  END wd_in[164]
  PIN wd_in[165]
    DIRECTION INPUT ;
    USE SIGNAL ;
    SHAPE ABUTMENT ;
    PORT
      LAYER M4 ;
      RECT 0.000 181.619 0.018 181.637 ;
    END
  END wd_in[165]
  PIN wd_in[166]
    DIRECTION INPUT ;
    USE SIGNAL ;
    SHAPE ABUTMENT ;
    PORT
      LAYER M4 ;
      RECT 0.000 181.871 0.018 181.889 ;
    END
  END wd_in[166]
  PIN wd_in[167]
    DIRECTION INPUT ;
    USE SIGNAL ;
    SHAPE ABUTMENT ;
    PORT
      LAYER M4 ;
      RECT 0.000 182.123 0.018 182.141 ;
    END
  END wd_in[167]
  PIN wd_in[168]
    DIRECTION INPUT ;
    USE SIGNAL ;
    SHAPE ABUTMENT ;
    PORT
      LAYER M4 ;
      RECT 0.000 182.375 0.018 182.393 ;
    END
  END wd_in[168]
  PIN wd_in[169]
    DIRECTION INPUT ;
    USE SIGNAL ;
    SHAPE ABUTMENT ;
    PORT
      LAYER M4 ;
      RECT 0.000 182.627 0.018 182.645 ;
    END
  END wd_in[169]
  PIN wd_in[170]
    DIRECTION INPUT ;
    USE SIGNAL ;
    SHAPE ABUTMENT ;
    PORT
      LAYER M4 ;
      RECT 0.000 182.879 0.018 182.897 ;
    END
  END wd_in[170]
  PIN wd_in[171]
    DIRECTION INPUT ;
    USE SIGNAL ;
    SHAPE ABUTMENT ;
    PORT
      LAYER M4 ;
      RECT 0.000 183.131 0.018 183.149 ;
    END
  END wd_in[171]
  PIN wd_in[172]
    DIRECTION INPUT ;
    USE SIGNAL ;
    SHAPE ABUTMENT ;
    PORT
      LAYER M4 ;
      RECT 0.000 183.383 0.018 183.401 ;
    END
  END wd_in[172]
  PIN wd_in[173]
    DIRECTION INPUT ;
    USE SIGNAL ;
    SHAPE ABUTMENT ;
    PORT
      LAYER M4 ;
      RECT 0.000 183.635 0.018 183.653 ;
    END
  END wd_in[173]
  PIN wd_in[174]
    DIRECTION INPUT ;
    USE SIGNAL ;
    SHAPE ABUTMENT ;
    PORT
      LAYER M4 ;
      RECT 0.000 183.887 0.018 183.905 ;
    END
  END wd_in[174]
  PIN wd_in[175]
    DIRECTION INPUT ;
    USE SIGNAL ;
    SHAPE ABUTMENT ;
    PORT
      LAYER M4 ;
      RECT 0.000 184.139 0.018 184.157 ;
    END
  END wd_in[175]
  PIN wd_in[176]
    DIRECTION INPUT ;
    USE SIGNAL ;
    SHAPE ABUTMENT ;
    PORT
      LAYER M4 ;
      RECT 0.000 184.391 0.018 184.409 ;
    END
  END wd_in[176]
  PIN wd_in[177]
    DIRECTION INPUT ;
    USE SIGNAL ;
    SHAPE ABUTMENT ;
    PORT
      LAYER M4 ;
      RECT 0.000 184.643 0.018 184.661 ;
    END
  END wd_in[177]
  PIN wd_in[178]
    DIRECTION INPUT ;
    USE SIGNAL ;
    SHAPE ABUTMENT ;
    PORT
      LAYER M4 ;
      RECT 0.000 184.895 0.018 184.913 ;
    END
  END wd_in[178]
  PIN wd_in[179]
    DIRECTION INPUT ;
    USE SIGNAL ;
    SHAPE ABUTMENT ;
    PORT
      LAYER M4 ;
      RECT 0.000 185.147 0.018 185.165 ;
    END
  END wd_in[179]
  PIN wd_in[180]
    DIRECTION INPUT ;
    USE SIGNAL ;
    SHAPE ABUTMENT ;
    PORT
      LAYER M4 ;
      RECT 0.000 185.399 0.018 185.417 ;
    END
  END wd_in[180]
  PIN wd_in[181]
    DIRECTION INPUT ;
    USE SIGNAL ;
    SHAPE ABUTMENT ;
    PORT
      LAYER M4 ;
      RECT 0.000 185.651 0.018 185.669 ;
    END
  END wd_in[181]
  PIN wd_in[182]
    DIRECTION INPUT ;
    USE SIGNAL ;
    SHAPE ABUTMENT ;
    PORT
      LAYER M4 ;
      RECT 0.000 185.903 0.018 185.921 ;
    END
  END wd_in[182]
  PIN wd_in[183]
    DIRECTION INPUT ;
    USE SIGNAL ;
    SHAPE ABUTMENT ;
    PORT
      LAYER M4 ;
      RECT 0.000 186.155 0.018 186.173 ;
    END
  END wd_in[183]
  PIN wd_in[184]
    DIRECTION INPUT ;
    USE SIGNAL ;
    SHAPE ABUTMENT ;
    PORT
      LAYER M4 ;
      RECT 0.000 186.407 0.018 186.425 ;
    END
  END wd_in[184]
  PIN wd_in[185]
    DIRECTION INPUT ;
    USE SIGNAL ;
    SHAPE ABUTMENT ;
    PORT
      LAYER M4 ;
      RECT 0.000 186.659 0.018 186.677 ;
    END
  END wd_in[185]
  PIN wd_in[186]
    DIRECTION INPUT ;
    USE SIGNAL ;
    SHAPE ABUTMENT ;
    PORT
      LAYER M4 ;
      RECT 0.000 186.911 0.018 186.929 ;
    END
  END wd_in[186]
  PIN wd_in[187]
    DIRECTION INPUT ;
    USE SIGNAL ;
    SHAPE ABUTMENT ;
    PORT
      LAYER M4 ;
      RECT 0.000 187.163 0.018 187.181 ;
    END
  END wd_in[187]
  PIN wd_in[188]
    DIRECTION INPUT ;
    USE SIGNAL ;
    SHAPE ABUTMENT ;
    PORT
      LAYER M4 ;
      RECT 0.000 187.415 0.018 187.433 ;
    END
  END wd_in[188]
  PIN wd_in[189]
    DIRECTION INPUT ;
    USE SIGNAL ;
    SHAPE ABUTMENT ;
    PORT
      LAYER M4 ;
      RECT 0.000 187.667 0.018 187.685 ;
    END
  END wd_in[189]
  PIN wd_in[190]
    DIRECTION INPUT ;
    USE SIGNAL ;
    SHAPE ABUTMENT ;
    PORT
      LAYER M4 ;
      RECT 0.000 187.919 0.018 187.937 ;
    END
  END wd_in[190]
  PIN wd_in[191]
    DIRECTION INPUT ;
    USE SIGNAL ;
    SHAPE ABUTMENT ;
    PORT
      LAYER M4 ;
      RECT 0.000 188.171 0.018 188.189 ;
    END
  END wd_in[191]
  PIN wd_in[192]
    DIRECTION INPUT ;
    USE SIGNAL ;
    SHAPE ABUTMENT ;
    PORT
      LAYER M4 ;
      RECT 0.000 188.423 0.018 188.441 ;
    END
  END wd_in[192]
  PIN wd_in[193]
    DIRECTION INPUT ;
    USE SIGNAL ;
    SHAPE ABUTMENT ;
    PORT
      LAYER M4 ;
      RECT 0.000 188.675 0.018 188.693 ;
    END
  END wd_in[193]
  PIN wd_in[194]
    DIRECTION INPUT ;
    USE SIGNAL ;
    SHAPE ABUTMENT ;
    PORT
      LAYER M4 ;
      RECT 0.000 188.927 0.018 188.945 ;
    END
  END wd_in[194]
  PIN wd_in[195]
    DIRECTION INPUT ;
    USE SIGNAL ;
    SHAPE ABUTMENT ;
    PORT
      LAYER M4 ;
      RECT 0.000 189.179 0.018 189.197 ;
    END
  END wd_in[195]
  PIN wd_in[196]
    DIRECTION INPUT ;
    USE SIGNAL ;
    SHAPE ABUTMENT ;
    PORT
      LAYER M4 ;
      RECT 0.000 189.431 0.018 189.449 ;
    END
  END wd_in[196]
  PIN wd_in[197]
    DIRECTION INPUT ;
    USE SIGNAL ;
    SHAPE ABUTMENT ;
    PORT
      LAYER M4 ;
      RECT 0.000 189.683 0.018 189.701 ;
    END
  END wd_in[197]
  PIN wd_in[198]
    DIRECTION INPUT ;
    USE SIGNAL ;
    SHAPE ABUTMENT ;
    PORT
      LAYER M4 ;
      RECT 0.000 189.935 0.018 189.953 ;
    END
  END wd_in[198]
  PIN wd_in[199]
    DIRECTION INPUT ;
    USE SIGNAL ;
    SHAPE ABUTMENT ;
    PORT
      LAYER M4 ;
      RECT 0.000 190.187 0.018 190.205 ;
    END
  END wd_in[199]
  PIN wd_in[200]
    DIRECTION INPUT ;
    USE SIGNAL ;
    SHAPE ABUTMENT ;
    PORT
      LAYER M4 ;
      RECT 0.000 190.439 0.018 190.457 ;
    END
  END wd_in[200]
  PIN wd_in[201]
    DIRECTION INPUT ;
    USE SIGNAL ;
    SHAPE ABUTMENT ;
    PORT
      LAYER M4 ;
      RECT 0.000 190.691 0.018 190.709 ;
    END
  END wd_in[201]
  PIN wd_in[202]
    DIRECTION INPUT ;
    USE SIGNAL ;
    SHAPE ABUTMENT ;
    PORT
      LAYER M4 ;
      RECT 0.000 190.943 0.018 190.961 ;
    END
  END wd_in[202]
  PIN wd_in[203]
    DIRECTION INPUT ;
    USE SIGNAL ;
    SHAPE ABUTMENT ;
    PORT
      LAYER M4 ;
      RECT 0.000 191.195 0.018 191.213 ;
    END
  END wd_in[203]
  PIN wd_in[204]
    DIRECTION INPUT ;
    USE SIGNAL ;
    SHAPE ABUTMENT ;
    PORT
      LAYER M4 ;
      RECT 0.000 191.447 0.018 191.465 ;
    END
  END wd_in[204]
  PIN wd_in[205]
    DIRECTION INPUT ;
    USE SIGNAL ;
    SHAPE ABUTMENT ;
    PORT
      LAYER M4 ;
      RECT 0.000 191.699 0.018 191.717 ;
    END
  END wd_in[205]
  PIN wd_in[206]
    DIRECTION INPUT ;
    USE SIGNAL ;
    SHAPE ABUTMENT ;
    PORT
      LAYER M4 ;
      RECT 0.000 191.951 0.018 191.969 ;
    END
  END wd_in[206]
  PIN wd_in[207]
    DIRECTION INPUT ;
    USE SIGNAL ;
    SHAPE ABUTMENT ;
    PORT
      LAYER M4 ;
      RECT 0.000 192.203 0.018 192.221 ;
    END
  END wd_in[207]
  PIN wd_in[208]
    DIRECTION INPUT ;
    USE SIGNAL ;
    SHAPE ABUTMENT ;
    PORT
      LAYER M4 ;
      RECT 0.000 192.455 0.018 192.473 ;
    END
  END wd_in[208]
  PIN wd_in[209]
    DIRECTION INPUT ;
    USE SIGNAL ;
    SHAPE ABUTMENT ;
    PORT
      LAYER M4 ;
      RECT 0.000 192.707 0.018 192.725 ;
    END
  END wd_in[209]
  PIN wd_in[210]
    DIRECTION INPUT ;
    USE SIGNAL ;
    SHAPE ABUTMENT ;
    PORT
      LAYER M4 ;
      RECT 0.000 192.959 0.018 192.977 ;
    END
  END wd_in[210]
  PIN wd_in[211]
    DIRECTION INPUT ;
    USE SIGNAL ;
    SHAPE ABUTMENT ;
    PORT
      LAYER M4 ;
      RECT 0.000 193.211 0.018 193.229 ;
    END
  END wd_in[211]
  PIN wd_in[212]
    DIRECTION INPUT ;
    USE SIGNAL ;
    SHAPE ABUTMENT ;
    PORT
      LAYER M4 ;
      RECT 0.000 193.463 0.018 193.481 ;
    END
  END wd_in[212]
  PIN wd_in[213]
    DIRECTION INPUT ;
    USE SIGNAL ;
    SHAPE ABUTMENT ;
    PORT
      LAYER M4 ;
      RECT 0.000 193.715 0.018 193.733 ;
    END
  END wd_in[213]
  PIN wd_in[214]
    DIRECTION INPUT ;
    USE SIGNAL ;
    SHAPE ABUTMENT ;
    PORT
      LAYER M4 ;
      RECT 0.000 193.967 0.018 193.985 ;
    END
  END wd_in[214]
  PIN wd_in[215]
    DIRECTION INPUT ;
    USE SIGNAL ;
    SHAPE ABUTMENT ;
    PORT
      LAYER M4 ;
      RECT 0.000 194.219 0.018 194.237 ;
    END
  END wd_in[215]
  PIN wd_in[216]
    DIRECTION INPUT ;
    USE SIGNAL ;
    SHAPE ABUTMENT ;
    PORT
      LAYER M4 ;
      RECT 0.000 194.471 0.018 194.489 ;
    END
  END wd_in[216]
  PIN wd_in[217]
    DIRECTION INPUT ;
    USE SIGNAL ;
    SHAPE ABUTMENT ;
    PORT
      LAYER M4 ;
      RECT 0.000 194.723 0.018 194.741 ;
    END
  END wd_in[217]
  PIN wd_in[218]
    DIRECTION INPUT ;
    USE SIGNAL ;
    SHAPE ABUTMENT ;
    PORT
      LAYER M4 ;
      RECT 0.000 194.975 0.018 194.993 ;
    END
  END wd_in[218]
  PIN wd_in[219]
    DIRECTION INPUT ;
    USE SIGNAL ;
    SHAPE ABUTMENT ;
    PORT
      LAYER M4 ;
      RECT 0.000 195.227 0.018 195.245 ;
    END
  END wd_in[219]
  PIN wd_in[220]
    DIRECTION INPUT ;
    USE SIGNAL ;
    SHAPE ABUTMENT ;
    PORT
      LAYER M4 ;
      RECT 0.000 195.479 0.018 195.497 ;
    END
  END wd_in[220]
  PIN wd_in[221]
    DIRECTION INPUT ;
    USE SIGNAL ;
    SHAPE ABUTMENT ;
    PORT
      LAYER M4 ;
      RECT 0.000 195.731 0.018 195.749 ;
    END
  END wd_in[221]
  PIN wd_in[222]
    DIRECTION INPUT ;
    USE SIGNAL ;
    SHAPE ABUTMENT ;
    PORT
      LAYER M4 ;
      RECT 0.000 195.983 0.018 196.001 ;
    END
  END wd_in[222]
  PIN wd_in[223]
    DIRECTION INPUT ;
    USE SIGNAL ;
    SHAPE ABUTMENT ;
    PORT
      LAYER M4 ;
      RECT 0.000 196.235 0.018 196.253 ;
    END
  END wd_in[223]
  PIN wd_in[224]
    DIRECTION INPUT ;
    USE SIGNAL ;
    SHAPE ABUTMENT ;
    PORT
      LAYER M4 ;
      RECT 0.000 196.487 0.018 196.505 ;
    END
  END wd_in[224]
  PIN wd_in[225]
    DIRECTION INPUT ;
    USE SIGNAL ;
    SHAPE ABUTMENT ;
    PORT
      LAYER M4 ;
      RECT 0.000 196.739 0.018 196.757 ;
    END
  END wd_in[225]
  PIN wd_in[226]
    DIRECTION INPUT ;
    USE SIGNAL ;
    SHAPE ABUTMENT ;
    PORT
      LAYER M4 ;
      RECT 0.000 196.991 0.018 197.009 ;
    END
  END wd_in[226]
  PIN wd_in[227]
    DIRECTION INPUT ;
    USE SIGNAL ;
    SHAPE ABUTMENT ;
    PORT
      LAYER M4 ;
      RECT 0.000 197.243 0.018 197.261 ;
    END
  END wd_in[227]
  PIN wd_in[228]
    DIRECTION INPUT ;
    USE SIGNAL ;
    SHAPE ABUTMENT ;
    PORT
      LAYER M4 ;
      RECT 0.000 197.495 0.018 197.513 ;
    END
  END wd_in[228]
  PIN wd_in[229]
    DIRECTION INPUT ;
    USE SIGNAL ;
    SHAPE ABUTMENT ;
    PORT
      LAYER M4 ;
      RECT 0.000 197.747 0.018 197.765 ;
    END
  END wd_in[229]
  PIN wd_in[230]
    DIRECTION INPUT ;
    USE SIGNAL ;
    SHAPE ABUTMENT ;
    PORT
      LAYER M4 ;
      RECT 0.000 197.999 0.018 198.017 ;
    END
  END wd_in[230]
  PIN wd_in[231]
    DIRECTION INPUT ;
    USE SIGNAL ;
    SHAPE ABUTMENT ;
    PORT
      LAYER M4 ;
      RECT 0.000 198.251 0.018 198.269 ;
    END
  END wd_in[231]
  PIN wd_in[232]
    DIRECTION INPUT ;
    USE SIGNAL ;
    SHAPE ABUTMENT ;
    PORT
      LAYER M4 ;
      RECT 0.000 198.503 0.018 198.521 ;
    END
  END wd_in[232]
  PIN wd_in[233]
    DIRECTION INPUT ;
    USE SIGNAL ;
    SHAPE ABUTMENT ;
    PORT
      LAYER M4 ;
      RECT 0.000 198.755 0.018 198.773 ;
    END
  END wd_in[233]
  PIN wd_in[234]
    DIRECTION INPUT ;
    USE SIGNAL ;
    SHAPE ABUTMENT ;
    PORT
      LAYER M4 ;
      RECT 0.000 199.007 0.018 199.025 ;
    END
  END wd_in[234]
  PIN wd_in[235]
    DIRECTION INPUT ;
    USE SIGNAL ;
    SHAPE ABUTMENT ;
    PORT
      LAYER M4 ;
      RECT 0.000 199.259 0.018 199.277 ;
    END
  END wd_in[235]
  PIN wd_in[236]
    DIRECTION INPUT ;
    USE SIGNAL ;
    SHAPE ABUTMENT ;
    PORT
      LAYER M4 ;
      RECT 0.000 199.511 0.018 199.529 ;
    END
  END wd_in[236]
  PIN wd_in[237]
    DIRECTION INPUT ;
    USE SIGNAL ;
    SHAPE ABUTMENT ;
    PORT
      LAYER M4 ;
      RECT 0.000 199.763 0.018 199.781 ;
    END
  END wd_in[237]
  PIN wd_in[238]
    DIRECTION INPUT ;
    USE SIGNAL ;
    SHAPE ABUTMENT ;
    PORT
      LAYER M4 ;
      RECT 0.000 200.015 0.018 200.033 ;
    END
  END wd_in[238]
  PIN wd_in[239]
    DIRECTION INPUT ;
    USE SIGNAL ;
    SHAPE ABUTMENT ;
    PORT
      LAYER M4 ;
      RECT 0.000 200.267 0.018 200.285 ;
    END
  END wd_in[239]
  PIN wd_in[240]
    DIRECTION INPUT ;
    USE SIGNAL ;
    SHAPE ABUTMENT ;
    PORT
      LAYER M4 ;
      RECT 0.000 200.519 0.018 200.537 ;
    END
  END wd_in[240]
  PIN wd_in[241]
    DIRECTION INPUT ;
    USE SIGNAL ;
    SHAPE ABUTMENT ;
    PORT
      LAYER M4 ;
      RECT 0.000 200.771 0.018 200.789 ;
    END
  END wd_in[241]
  PIN wd_in[242]
    DIRECTION INPUT ;
    USE SIGNAL ;
    SHAPE ABUTMENT ;
    PORT
      LAYER M4 ;
      RECT 0.000 201.023 0.018 201.041 ;
    END
  END wd_in[242]
  PIN wd_in[243]
    DIRECTION INPUT ;
    USE SIGNAL ;
    SHAPE ABUTMENT ;
    PORT
      LAYER M4 ;
      RECT 0.000 201.275 0.018 201.293 ;
    END
  END wd_in[243]
  PIN wd_in[244]
    DIRECTION INPUT ;
    USE SIGNAL ;
    SHAPE ABUTMENT ;
    PORT
      LAYER M4 ;
      RECT 0.000 201.527 0.018 201.545 ;
    END
  END wd_in[244]
  PIN wd_in[245]
    DIRECTION INPUT ;
    USE SIGNAL ;
    SHAPE ABUTMENT ;
    PORT
      LAYER M4 ;
      RECT 0.000 201.779 0.018 201.797 ;
    END
  END wd_in[245]
  PIN wd_in[246]
    DIRECTION INPUT ;
    USE SIGNAL ;
    SHAPE ABUTMENT ;
    PORT
      LAYER M4 ;
      RECT 0.000 202.031 0.018 202.049 ;
    END
  END wd_in[246]
  PIN wd_in[247]
    DIRECTION INPUT ;
    USE SIGNAL ;
    SHAPE ABUTMENT ;
    PORT
      LAYER M4 ;
      RECT 0.000 202.283 0.018 202.301 ;
    END
  END wd_in[247]
  PIN wd_in[248]
    DIRECTION INPUT ;
    USE SIGNAL ;
    SHAPE ABUTMENT ;
    PORT
      LAYER M4 ;
      RECT 0.000 202.535 0.018 202.553 ;
    END
  END wd_in[248]
  PIN wd_in[249]
    DIRECTION INPUT ;
    USE SIGNAL ;
    SHAPE ABUTMENT ;
    PORT
      LAYER M4 ;
      RECT 0.000 202.787 0.018 202.805 ;
    END
  END wd_in[249]
  PIN wd_in[250]
    DIRECTION INPUT ;
    USE SIGNAL ;
    SHAPE ABUTMENT ;
    PORT
      LAYER M4 ;
      RECT 0.000 203.039 0.018 203.057 ;
    END
  END wd_in[250]
  PIN wd_in[251]
    DIRECTION INPUT ;
    USE SIGNAL ;
    SHAPE ABUTMENT ;
    PORT
      LAYER M4 ;
      RECT 0.000 203.291 0.018 203.309 ;
    END
  END wd_in[251]
  PIN wd_in[252]
    DIRECTION INPUT ;
    USE SIGNAL ;
    SHAPE ABUTMENT ;
    PORT
      LAYER M4 ;
      RECT 0.000 203.543 0.018 203.561 ;
    END
  END wd_in[252]
  PIN wd_in[253]
    DIRECTION INPUT ;
    USE SIGNAL ;
    SHAPE ABUTMENT ;
    PORT
      LAYER M4 ;
      RECT 0.000 203.795 0.018 203.813 ;
    END
  END wd_in[253]
  PIN wd_in[254]
    DIRECTION INPUT ;
    USE SIGNAL ;
    SHAPE ABUTMENT ;
    PORT
      LAYER M4 ;
      RECT 0.000 204.047 0.018 204.065 ;
    END
  END wd_in[254]
  PIN wd_in[255]
    DIRECTION INPUT ;
    USE SIGNAL ;
    SHAPE ABUTMENT ;
    PORT
      LAYER M4 ;
      RECT 0.000 204.299 0.018 204.317 ;
    END
  END wd_in[255]
  PIN wd_in[256]
    DIRECTION INPUT ;
    USE SIGNAL ;
    SHAPE ABUTMENT ;
    PORT
      LAYER M4 ;
      RECT 0.000 204.551 0.018 204.569 ;
    END
  END wd_in[256]
  PIN wd_in[257]
    DIRECTION INPUT ;
    USE SIGNAL ;
    SHAPE ABUTMENT ;
    PORT
      LAYER M4 ;
      RECT 0.000 204.803 0.018 204.821 ;
    END
  END wd_in[257]
  PIN wd_in[258]
    DIRECTION INPUT ;
    USE SIGNAL ;
    SHAPE ABUTMENT ;
    PORT
      LAYER M4 ;
      RECT 0.000 205.055 0.018 205.073 ;
    END
  END wd_in[258]
  PIN wd_in[259]
    DIRECTION INPUT ;
    USE SIGNAL ;
    SHAPE ABUTMENT ;
    PORT
      LAYER M4 ;
      RECT 0.000 205.307 0.018 205.325 ;
    END
  END wd_in[259]
  PIN wd_in[260]
    DIRECTION INPUT ;
    USE SIGNAL ;
    SHAPE ABUTMENT ;
    PORT
      LAYER M4 ;
      RECT 0.000 205.559 0.018 205.577 ;
    END
  END wd_in[260]
  PIN wd_in[261]
    DIRECTION INPUT ;
    USE SIGNAL ;
    SHAPE ABUTMENT ;
    PORT
      LAYER M4 ;
      RECT 0.000 205.811 0.018 205.829 ;
    END
  END wd_in[261]
  PIN wd_in[262]
    DIRECTION INPUT ;
    USE SIGNAL ;
    SHAPE ABUTMENT ;
    PORT
      LAYER M4 ;
      RECT 0.000 206.063 0.018 206.081 ;
    END
  END wd_in[262]
  PIN wd_in[263]
    DIRECTION INPUT ;
    USE SIGNAL ;
    SHAPE ABUTMENT ;
    PORT
      LAYER M4 ;
      RECT 0.000 206.315 0.018 206.333 ;
    END
  END wd_in[263]
  PIN wd_in[264]
    DIRECTION INPUT ;
    USE SIGNAL ;
    SHAPE ABUTMENT ;
    PORT
      LAYER M4 ;
      RECT 0.000 206.567 0.018 206.585 ;
    END
  END wd_in[264]
  PIN wd_in[265]
    DIRECTION INPUT ;
    USE SIGNAL ;
    SHAPE ABUTMENT ;
    PORT
      LAYER M4 ;
      RECT 0.000 206.819 0.018 206.837 ;
    END
  END wd_in[265]
  PIN wd_in[266]
    DIRECTION INPUT ;
    USE SIGNAL ;
    SHAPE ABUTMENT ;
    PORT
      LAYER M4 ;
      RECT 0.000 207.071 0.018 207.089 ;
    END
  END wd_in[266]
  PIN wd_in[267]
    DIRECTION INPUT ;
    USE SIGNAL ;
    SHAPE ABUTMENT ;
    PORT
      LAYER M4 ;
      RECT 0.000 207.323 0.018 207.341 ;
    END
  END wd_in[267]
  PIN wd_in[268]
    DIRECTION INPUT ;
    USE SIGNAL ;
    SHAPE ABUTMENT ;
    PORT
      LAYER M4 ;
      RECT 0.000 207.575 0.018 207.593 ;
    END
  END wd_in[268]
  PIN wd_in[269]
    DIRECTION INPUT ;
    USE SIGNAL ;
    SHAPE ABUTMENT ;
    PORT
      LAYER M4 ;
      RECT 0.000 207.827 0.018 207.845 ;
    END
  END wd_in[269]
  PIN wd_in[270]
    DIRECTION INPUT ;
    USE SIGNAL ;
    SHAPE ABUTMENT ;
    PORT
      LAYER M4 ;
      RECT 0.000 208.079 0.018 208.097 ;
    END
  END wd_in[270]
  PIN wd_in[271]
    DIRECTION INPUT ;
    USE SIGNAL ;
    SHAPE ABUTMENT ;
    PORT
      LAYER M4 ;
      RECT 0.000 208.331 0.018 208.349 ;
    END
  END wd_in[271]
  PIN wd_in[272]
    DIRECTION INPUT ;
    USE SIGNAL ;
    SHAPE ABUTMENT ;
    PORT
      LAYER M4 ;
      RECT 0.000 208.583 0.018 208.601 ;
    END
  END wd_in[272]
  PIN wd_in[273]
    DIRECTION INPUT ;
    USE SIGNAL ;
    SHAPE ABUTMENT ;
    PORT
      LAYER M4 ;
      RECT 0.000 208.835 0.018 208.853 ;
    END
  END wd_in[273]
  PIN wd_in[274]
    DIRECTION INPUT ;
    USE SIGNAL ;
    SHAPE ABUTMENT ;
    PORT
      LAYER M4 ;
      RECT 0.000 209.087 0.018 209.105 ;
    END
  END wd_in[274]
  PIN wd_in[275]
    DIRECTION INPUT ;
    USE SIGNAL ;
    SHAPE ABUTMENT ;
    PORT
      LAYER M4 ;
      RECT 0.000 209.339 0.018 209.357 ;
    END
  END wd_in[275]
  PIN wd_in[276]
    DIRECTION INPUT ;
    USE SIGNAL ;
    SHAPE ABUTMENT ;
    PORT
      LAYER M4 ;
      RECT 0.000 209.591 0.018 209.609 ;
    END
  END wd_in[276]
  PIN wd_in[277]
    DIRECTION INPUT ;
    USE SIGNAL ;
    SHAPE ABUTMENT ;
    PORT
      LAYER M4 ;
      RECT 0.000 209.843 0.018 209.861 ;
    END
  END wd_in[277]
  PIN wd_in[278]
    DIRECTION INPUT ;
    USE SIGNAL ;
    SHAPE ABUTMENT ;
    PORT
      LAYER M4 ;
      RECT 0.000 210.095 0.018 210.113 ;
    END
  END wd_in[278]
  PIN wd_in[279]
    DIRECTION INPUT ;
    USE SIGNAL ;
    SHAPE ABUTMENT ;
    PORT
      LAYER M4 ;
      RECT 0.000 210.347 0.018 210.365 ;
    END
  END wd_in[279]
  PIN wd_in[280]
    DIRECTION INPUT ;
    USE SIGNAL ;
    SHAPE ABUTMENT ;
    PORT
      LAYER M4 ;
      RECT 0.000 210.599 0.018 210.617 ;
    END
  END wd_in[280]
  PIN wd_in[281]
    DIRECTION INPUT ;
    USE SIGNAL ;
    SHAPE ABUTMENT ;
    PORT
      LAYER M4 ;
      RECT 0.000 210.851 0.018 210.869 ;
    END
  END wd_in[281]
  PIN wd_in[282]
    DIRECTION INPUT ;
    USE SIGNAL ;
    SHAPE ABUTMENT ;
    PORT
      LAYER M4 ;
      RECT 0.000 211.103 0.018 211.121 ;
    END
  END wd_in[282]
  PIN wd_in[283]
    DIRECTION INPUT ;
    USE SIGNAL ;
    SHAPE ABUTMENT ;
    PORT
      LAYER M4 ;
      RECT 0.000 211.355 0.018 211.373 ;
    END
  END wd_in[283]
  PIN wd_in[284]
    DIRECTION INPUT ;
    USE SIGNAL ;
    SHAPE ABUTMENT ;
    PORT
      LAYER M4 ;
      RECT 0.000 211.607 0.018 211.625 ;
    END
  END wd_in[284]
  PIN wd_in[285]
    DIRECTION INPUT ;
    USE SIGNAL ;
    SHAPE ABUTMENT ;
    PORT
      LAYER M4 ;
      RECT 0.000 211.859 0.018 211.877 ;
    END
  END wd_in[285]
  PIN wd_in[286]
    DIRECTION INPUT ;
    USE SIGNAL ;
    SHAPE ABUTMENT ;
    PORT
      LAYER M4 ;
      RECT 0.000 212.111 0.018 212.129 ;
    END
  END wd_in[286]
  PIN wd_in[287]
    DIRECTION INPUT ;
    USE SIGNAL ;
    SHAPE ABUTMENT ;
    PORT
      LAYER M4 ;
      RECT 0.000 212.363 0.018 212.381 ;
    END
  END wd_in[287]
  PIN wd_in[288]
    DIRECTION INPUT ;
    USE SIGNAL ;
    SHAPE ABUTMENT ;
    PORT
      LAYER M4 ;
      RECT 0.000 212.615 0.018 212.633 ;
    END
  END wd_in[288]
  PIN wd_in[289]
    DIRECTION INPUT ;
    USE SIGNAL ;
    SHAPE ABUTMENT ;
    PORT
      LAYER M4 ;
      RECT 0.000 212.867 0.018 212.885 ;
    END
  END wd_in[289]
  PIN wd_in[290]
    DIRECTION INPUT ;
    USE SIGNAL ;
    SHAPE ABUTMENT ;
    PORT
      LAYER M4 ;
      RECT 0.000 213.119 0.018 213.137 ;
    END
  END wd_in[290]
  PIN wd_in[291]
    DIRECTION INPUT ;
    USE SIGNAL ;
    SHAPE ABUTMENT ;
    PORT
      LAYER M4 ;
      RECT 0.000 213.371 0.018 213.389 ;
    END
  END wd_in[291]
  PIN wd_in[292]
    DIRECTION INPUT ;
    USE SIGNAL ;
    SHAPE ABUTMENT ;
    PORT
      LAYER M4 ;
      RECT 0.000 213.623 0.018 213.641 ;
    END
  END wd_in[292]
  PIN wd_in[293]
    DIRECTION INPUT ;
    USE SIGNAL ;
    SHAPE ABUTMENT ;
    PORT
      LAYER M4 ;
      RECT 0.000 213.875 0.018 213.893 ;
    END
  END wd_in[293]
  PIN wd_in[294]
    DIRECTION INPUT ;
    USE SIGNAL ;
    SHAPE ABUTMENT ;
    PORT
      LAYER M4 ;
      RECT 0.000 214.127 0.018 214.145 ;
    END
  END wd_in[294]
  PIN wd_in[295]
    DIRECTION INPUT ;
    USE SIGNAL ;
    SHAPE ABUTMENT ;
    PORT
      LAYER M4 ;
      RECT 0.000 214.379 0.018 214.397 ;
    END
  END wd_in[295]
  PIN wd_in[296]
    DIRECTION INPUT ;
    USE SIGNAL ;
    SHAPE ABUTMENT ;
    PORT
      LAYER M4 ;
      RECT 0.000 214.631 0.018 214.649 ;
    END
  END wd_in[296]
  PIN wd_in[297]
    DIRECTION INPUT ;
    USE SIGNAL ;
    SHAPE ABUTMENT ;
    PORT
      LAYER M4 ;
      RECT 0.000 214.883 0.018 214.901 ;
    END
  END wd_in[297]
  PIN wd_in[298]
    DIRECTION INPUT ;
    USE SIGNAL ;
    SHAPE ABUTMENT ;
    PORT
      LAYER M4 ;
      RECT 0.000 215.135 0.018 215.153 ;
    END
  END wd_in[298]
  PIN wd_in[299]
    DIRECTION INPUT ;
    USE SIGNAL ;
    SHAPE ABUTMENT ;
    PORT
      LAYER M4 ;
      RECT 0.000 215.387 0.018 215.405 ;
    END
  END wd_in[299]
  PIN wd_in[300]
    DIRECTION INPUT ;
    USE SIGNAL ;
    SHAPE ABUTMENT ;
    PORT
      LAYER M4 ;
      RECT 0.000 215.639 0.018 215.657 ;
    END
  END wd_in[300]
  PIN wd_in[301]
    DIRECTION INPUT ;
    USE SIGNAL ;
    SHAPE ABUTMENT ;
    PORT
      LAYER M4 ;
      RECT 0.000 215.891 0.018 215.909 ;
    END
  END wd_in[301]
  PIN wd_in[302]
    DIRECTION INPUT ;
    USE SIGNAL ;
    SHAPE ABUTMENT ;
    PORT
      LAYER M4 ;
      RECT 0.000 216.143 0.018 216.161 ;
    END
  END wd_in[302]
  PIN wd_in[303]
    DIRECTION INPUT ;
    USE SIGNAL ;
    SHAPE ABUTMENT ;
    PORT
      LAYER M4 ;
      RECT 0.000 216.395 0.018 216.413 ;
    END
  END wd_in[303]
  PIN wd_in[304]
    DIRECTION INPUT ;
    USE SIGNAL ;
    SHAPE ABUTMENT ;
    PORT
      LAYER M4 ;
      RECT 0.000 216.647 0.018 216.665 ;
    END
  END wd_in[304]
  PIN wd_in[305]
    DIRECTION INPUT ;
    USE SIGNAL ;
    SHAPE ABUTMENT ;
    PORT
      LAYER M4 ;
      RECT 0.000 216.899 0.018 216.917 ;
    END
  END wd_in[305]
  PIN wd_in[306]
    DIRECTION INPUT ;
    USE SIGNAL ;
    SHAPE ABUTMENT ;
    PORT
      LAYER M4 ;
      RECT 0.000 217.151 0.018 217.169 ;
    END
  END wd_in[306]
  PIN wd_in[307]
    DIRECTION INPUT ;
    USE SIGNAL ;
    SHAPE ABUTMENT ;
    PORT
      LAYER M4 ;
      RECT 0.000 217.403 0.018 217.421 ;
    END
  END wd_in[307]
  PIN wd_in[308]
    DIRECTION INPUT ;
    USE SIGNAL ;
    SHAPE ABUTMENT ;
    PORT
      LAYER M4 ;
      RECT 0.000 217.655 0.018 217.673 ;
    END
  END wd_in[308]
  PIN wd_in[309]
    DIRECTION INPUT ;
    USE SIGNAL ;
    SHAPE ABUTMENT ;
    PORT
      LAYER M4 ;
      RECT 0.000 217.907 0.018 217.925 ;
    END
  END wd_in[309]
  PIN wd_in[310]
    DIRECTION INPUT ;
    USE SIGNAL ;
    SHAPE ABUTMENT ;
    PORT
      LAYER M4 ;
      RECT 0.000 218.159 0.018 218.177 ;
    END
  END wd_in[310]
  PIN wd_in[311]
    DIRECTION INPUT ;
    USE SIGNAL ;
    SHAPE ABUTMENT ;
    PORT
      LAYER M4 ;
      RECT 0.000 218.411 0.018 218.429 ;
    END
  END wd_in[311]
  PIN wd_in[312]
    DIRECTION INPUT ;
    USE SIGNAL ;
    SHAPE ABUTMENT ;
    PORT
      LAYER M4 ;
      RECT 0.000 218.663 0.018 218.681 ;
    END
  END wd_in[312]
  PIN wd_in[313]
    DIRECTION INPUT ;
    USE SIGNAL ;
    SHAPE ABUTMENT ;
    PORT
      LAYER M4 ;
      RECT 0.000 218.915 0.018 218.933 ;
    END
  END wd_in[313]
  PIN wd_in[314]
    DIRECTION INPUT ;
    USE SIGNAL ;
    SHAPE ABUTMENT ;
    PORT
      LAYER M4 ;
      RECT 0.000 219.167 0.018 219.185 ;
    END
  END wd_in[314]
  PIN wd_in[315]
    DIRECTION INPUT ;
    USE SIGNAL ;
    SHAPE ABUTMENT ;
    PORT
      LAYER M4 ;
      RECT 0.000 219.419 0.018 219.437 ;
    END
  END wd_in[315]
  PIN wd_in[316]
    DIRECTION INPUT ;
    USE SIGNAL ;
    SHAPE ABUTMENT ;
    PORT
      LAYER M4 ;
      RECT 0.000 219.671 0.018 219.689 ;
    END
  END wd_in[316]
  PIN wd_in[317]
    DIRECTION INPUT ;
    USE SIGNAL ;
    SHAPE ABUTMENT ;
    PORT
      LAYER M4 ;
      RECT 0.000 219.923 0.018 219.941 ;
    END
  END wd_in[317]
  PIN wd_in[318]
    DIRECTION INPUT ;
    USE SIGNAL ;
    SHAPE ABUTMENT ;
    PORT
      LAYER M4 ;
      RECT 0.000 220.175 0.018 220.193 ;
    END
  END wd_in[318]
  PIN wd_in[319]
    DIRECTION INPUT ;
    USE SIGNAL ;
    SHAPE ABUTMENT ;
    PORT
      LAYER M4 ;
      RECT 0.000 220.427 0.018 220.445 ;
    END
  END wd_in[319]
  PIN wd_in[320]
    DIRECTION INPUT ;
    USE SIGNAL ;
    SHAPE ABUTMENT ;
    PORT
      LAYER M4 ;
      RECT 0.000 220.679 0.018 220.697 ;
    END
  END wd_in[320]
  PIN wd_in[321]
    DIRECTION INPUT ;
    USE SIGNAL ;
    SHAPE ABUTMENT ;
    PORT
      LAYER M4 ;
      RECT 0.000 220.931 0.018 220.949 ;
    END
  END wd_in[321]
  PIN wd_in[322]
    DIRECTION INPUT ;
    USE SIGNAL ;
    SHAPE ABUTMENT ;
    PORT
      LAYER M4 ;
      RECT 0.000 221.183 0.018 221.201 ;
    END
  END wd_in[322]
  PIN wd_in[323]
    DIRECTION INPUT ;
    USE SIGNAL ;
    SHAPE ABUTMENT ;
    PORT
      LAYER M4 ;
      RECT 0.000 221.435 0.018 221.453 ;
    END
  END wd_in[323]
  PIN wd_in[324]
    DIRECTION INPUT ;
    USE SIGNAL ;
    SHAPE ABUTMENT ;
    PORT
      LAYER M4 ;
      RECT 0.000 221.687 0.018 221.705 ;
    END
  END wd_in[324]
  PIN wd_in[325]
    DIRECTION INPUT ;
    USE SIGNAL ;
    SHAPE ABUTMENT ;
    PORT
      LAYER M4 ;
      RECT 0.000 221.939 0.018 221.957 ;
    END
  END wd_in[325]
  PIN wd_in[326]
    DIRECTION INPUT ;
    USE SIGNAL ;
    SHAPE ABUTMENT ;
    PORT
      LAYER M4 ;
      RECT 0.000 222.191 0.018 222.209 ;
    END
  END wd_in[326]
  PIN wd_in[327]
    DIRECTION INPUT ;
    USE SIGNAL ;
    SHAPE ABUTMENT ;
    PORT
      LAYER M4 ;
      RECT 0.000 222.443 0.018 222.461 ;
    END
  END wd_in[327]
  PIN wd_in[328]
    DIRECTION INPUT ;
    USE SIGNAL ;
    SHAPE ABUTMENT ;
    PORT
      LAYER M4 ;
      RECT 0.000 222.695 0.018 222.713 ;
    END
  END wd_in[328]
  PIN wd_in[329]
    DIRECTION INPUT ;
    USE SIGNAL ;
    SHAPE ABUTMENT ;
    PORT
      LAYER M4 ;
      RECT 0.000 222.947 0.018 222.965 ;
    END
  END wd_in[329]
  PIN wd_in[330]
    DIRECTION INPUT ;
    USE SIGNAL ;
    SHAPE ABUTMENT ;
    PORT
      LAYER M4 ;
      RECT 0.000 223.199 0.018 223.217 ;
    END
  END wd_in[330]
  PIN wd_in[331]
    DIRECTION INPUT ;
    USE SIGNAL ;
    SHAPE ABUTMENT ;
    PORT
      LAYER M4 ;
      RECT 0.000 223.451 0.018 223.469 ;
    END
  END wd_in[331]
  PIN wd_in[332]
    DIRECTION INPUT ;
    USE SIGNAL ;
    SHAPE ABUTMENT ;
    PORT
      LAYER M4 ;
      RECT 0.000 223.703 0.018 223.721 ;
    END
  END wd_in[332]
  PIN wd_in[333]
    DIRECTION INPUT ;
    USE SIGNAL ;
    SHAPE ABUTMENT ;
    PORT
      LAYER M4 ;
      RECT 0.000 223.955 0.018 223.973 ;
    END
  END wd_in[333]
  PIN wd_in[334]
    DIRECTION INPUT ;
    USE SIGNAL ;
    SHAPE ABUTMENT ;
    PORT
      LAYER M4 ;
      RECT 0.000 224.207 0.018 224.225 ;
    END
  END wd_in[334]
  PIN wd_in[335]
    DIRECTION INPUT ;
    USE SIGNAL ;
    SHAPE ABUTMENT ;
    PORT
      LAYER M4 ;
      RECT 0.000 224.459 0.018 224.477 ;
    END
  END wd_in[335]
  PIN wd_in[336]
    DIRECTION INPUT ;
    USE SIGNAL ;
    SHAPE ABUTMENT ;
    PORT
      LAYER M4 ;
      RECT 0.000 224.711 0.018 224.729 ;
    END
  END wd_in[336]
  PIN wd_in[337]
    DIRECTION INPUT ;
    USE SIGNAL ;
    SHAPE ABUTMENT ;
    PORT
      LAYER M4 ;
      RECT 0.000 224.963 0.018 224.981 ;
    END
  END wd_in[337]
  PIN wd_in[338]
    DIRECTION INPUT ;
    USE SIGNAL ;
    SHAPE ABUTMENT ;
    PORT
      LAYER M4 ;
      RECT 0.000 225.215 0.018 225.233 ;
    END
  END wd_in[338]
  PIN wd_in[339]
    DIRECTION INPUT ;
    USE SIGNAL ;
    SHAPE ABUTMENT ;
    PORT
      LAYER M4 ;
      RECT 0.000 225.467 0.018 225.485 ;
    END
  END wd_in[339]
  PIN wd_in[340]
    DIRECTION INPUT ;
    USE SIGNAL ;
    SHAPE ABUTMENT ;
    PORT
      LAYER M4 ;
      RECT 0.000 225.719 0.018 225.737 ;
    END
  END wd_in[340]
  PIN wd_in[341]
    DIRECTION INPUT ;
    USE SIGNAL ;
    SHAPE ABUTMENT ;
    PORT
      LAYER M4 ;
      RECT 0.000 225.971 0.018 225.989 ;
    END
  END wd_in[341]
  PIN wd_in[342]
    DIRECTION INPUT ;
    USE SIGNAL ;
    SHAPE ABUTMENT ;
    PORT
      LAYER M4 ;
      RECT 0.000 226.223 0.018 226.241 ;
    END
  END wd_in[342]
  PIN wd_in[343]
    DIRECTION INPUT ;
    USE SIGNAL ;
    SHAPE ABUTMENT ;
    PORT
      LAYER M4 ;
      RECT 0.000 226.475 0.018 226.493 ;
    END
  END wd_in[343]
  PIN wd_in[344]
    DIRECTION INPUT ;
    USE SIGNAL ;
    SHAPE ABUTMENT ;
    PORT
      LAYER M4 ;
      RECT 0.000 226.727 0.018 226.745 ;
    END
  END wd_in[344]
  PIN wd_in[345]
    DIRECTION INPUT ;
    USE SIGNAL ;
    SHAPE ABUTMENT ;
    PORT
      LAYER M4 ;
      RECT 0.000 226.979 0.018 226.997 ;
    END
  END wd_in[345]
  PIN wd_in[346]
    DIRECTION INPUT ;
    USE SIGNAL ;
    SHAPE ABUTMENT ;
    PORT
      LAYER M4 ;
      RECT 0.000 227.231 0.018 227.249 ;
    END
  END wd_in[346]
  PIN wd_in[347]
    DIRECTION INPUT ;
    USE SIGNAL ;
    SHAPE ABUTMENT ;
    PORT
      LAYER M4 ;
      RECT 0.000 227.483 0.018 227.501 ;
    END
  END wd_in[347]
  PIN wd_in[348]
    DIRECTION INPUT ;
    USE SIGNAL ;
    SHAPE ABUTMENT ;
    PORT
      LAYER M4 ;
      RECT 0.000 227.735 0.018 227.753 ;
    END
  END wd_in[348]
  PIN wd_in[349]
    DIRECTION INPUT ;
    USE SIGNAL ;
    SHAPE ABUTMENT ;
    PORT
      LAYER M4 ;
      RECT 0.000 227.987 0.018 228.005 ;
    END
  END wd_in[349]
  PIN wd_in[350]
    DIRECTION INPUT ;
    USE SIGNAL ;
    SHAPE ABUTMENT ;
    PORT
      LAYER M4 ;
      RECT 0.000 228.239 0.018 228.257 ;
    END
  END wd_in[350]
  PIN wd_in[351]
    DIRECTION INPUT ;
    USE SIGNAL ;
    SHAPE ABUTMENT ;
    PORT
      LAYER M4 ;
      RECT 0.000 228.491 0.018 228.509 ;
    END
  END wd_in[351]
  PIN wd_in[352]
    DIRECTION INPUT ;
    USE SIGNAL ;
    SHAPE ABUTMENT ;
    PORT
      LAYER M4 ;
      RECT 0.000 228.743 0.018 228.761 ;
    END
  END wd_in[352]
  PIN wd_in[353]
    DIRECTION INPUT ;
    USE SIGNAL ;
    SHAPE ABUTMENT ;
    PORT
      LAYER M4 ;
      RECT 0.000 228.995 0.018 229.013 ;
    END
  END wd_in[353]
  PIN wd_in[354]
    DIRECTION INPUT ;
    USE SIGNAL ;
    SHAPE ABUTMENT ;
    PORT
      LAYER M4 ;
      RECT 0.000 229.247 0.018 229.265 ;
    END
  END wd_in[354]
  PIN wd_in[355]
    DIRECTION INPUT ;
    USE SIGNAL ;
    SHAPE ABUTMENT ;
    PORT
      LAYER M4 ;
      RECT 0.000 229.499 0.018 229.517 ;
    END
  END wd_in[355]
  PIN wd_in[356]
    DIRECTION INPUT ;
    USE SIGNAL ;
    SHAPE ABUTMENT ;
    PORT
      LAYER M4 ;
      RECT 0.000 229.751 0.018 229.769 ;
    END
  END wd_in[356]
  PIN wd_in[357]
    DIRECTION INPUT ;
    USE SIGNAL ;
    SHAPE ABUTMENT ;
    PORT
      LAYER M4 ;
      RECT 0.000 230.003 0.018 230.021 ;
    END
  END wd_in[357]
  PIN wd_in[358]
    DIRECTION INPUT ;
    USE SIGNAL ;
    SHAPE ABUTMENT ;
    PORT
      LAYER M4 ;
      RECT 0.000 230.255 0.018 230.273 ;
    END
  END wd_in[358]
  PIN wd_in[359]
    DIRECTION INPUT ;
    USE SIGNAL ;
    SHAPE ABUTMENT ;
    PORT
      LAYER M4 ;
      RECT 0.000 230.507 0.018 230.525 ;
    END
  END wd_in[359]
  PIN wd_in[360]
    DIRECTION INPUT ;
    USE SIGNAL ;
    SHAPE ABUTMENT ;
    PORT
      LAYER M4 ;
      RECT 0.000 230.759 0.018 230.777 ;
    END
  END wd_in[360]
  PIN wd_in[361]
    DIRECTION INPUT ;
    USE SIGNAL ;
    SHAPE ABUTMENT ;
    PORT
      LAYER M4 ;
      RECT 0.000 231.011 0.018 231.029 ;
    END
  END wd_in[361]
  PIN wd_in[362]
    DIRECTION INPUT ;
    USE SIGNAL ;
    SHAPE ABUTMENT ;
    PORT
      LAYER M4 ;
      RECT 0.000 231.263 0.018 231.281 ;
    END
  END wd_in[362]
  PIN wd_in[363]
    DIRECTION INPUT ;
    USE SIGNAL ;
    SHAPE ABUTMENT ;
    PORT
      LAYER M4 ;
      RECT 0.000 231.515 0.018 231.533 ;
    END
  END wd_in[363]
  PIN wd_in[364]
    DIRECTION INPUT ;
    USE SIGNAL ;
    SHAPE ABUTMENT ;
    PORT
      LAYER M4 ;
      RECT 0.000 231.767 0.018 231.785 ;
    END
  END wd_in[364]
  PIN wd_in[365]
    DIRECTION INPUT ;
    USE SIGNAL ;
    SHAPE ABUTMENT ;
    PORT
      LAYER M4 ;
      RECT 0.000 232.019 0.018 232.037 ;
    END
  END wd_in[365]
  PIN wd_in[366]
    DIRECTION INPUT ;
    USE SIGNAL ;
    SHAPE ABUTMENT ;
    PORT
      LAYER M4 ;
      RECT 0.000 232.271 0.018 232.289 ;
    END
  END wd_in[366]
  PIN wd_in[367]
    DIRECTION INPUT ;
    USE SIGNAL ;
    SHAPE ABUTMENT ;
    PORT
      LAYER M4 ;
      RECT 0.000 232.523 0.018 232.541 ;
    END
  END wd_in[367]
  PIN wd_in[368]
    DIRECTION INPUT ;
    USE SIGNAL ;
    SHAPE ABUTMENT ;
    PORT
      LAYER M4 ;
      RECT 0.000 232.775 0.018 232.793 ;
    END
  END wd_in[368]
  PIN wd_in[369]
    DIRECTION INPUT ;
    USE SIGNAL ;
    SHAPE ABUTMENT ;
    PORT
      LAYER M4 ;
      RECT 0.000 233.027 0.018 233.045 ;
    END
  END wd_in[369]
  PIN wd_in[370]
    DIRECTION INPUT ;
    USE SIGNAL ;
    SHAPE ABUTMENT ;
    PORT
      LAYER M4 ;
      RECT 0.000 233.279 0.018 233.297 ;
    END
  END wd_in[370]
  PIN wd_in[371]
    DIRECTION INPUT ;
    USE SIGNAL ;
    SHAPE ABUTMENT ;
    PORT
      LAYER M4 ;
      RECT 0.000 233.531 0.018 233.549 ;
    END
  END wd_in[371]
  PIN wd_in[372]
    DIRECTION INPUT ;
    USE SIGNAL ;
    SHAPE ABUTMENT ;
    PORT
      LAYER M4 ;
      RECT 0.000 233.783 0.018 233.801 ;
    END
  END wd_in[372]
  PIN wd_in[373]
    DIRECTION INPUT ;
    USE SIGNAL ;
    SHAPE ABUTMENT ;
    PORT
      LAYER M4 ;
      RECT 0.000 234.035 0.018 234.053 ;
    END
  END wd_in[373]
  PIN wd_in[374]
    DIRECTION INPUT ;
    USE SIGNAL ;
    SHAPE ABUTMENT ;
    PORT
      LAYER M4 ;
      RECT 0.000 234.287 0.018 234.305 ;
    END
  END wd_in[374]
  PIN wd_in[375]
    DIRECTION INPUT ;
    USE SIGNAL ;
    SHAPE ABUTMENT ;
    PORT
      LAYER M4 ;
      RECT 0.000 234.539 0.018 234.557 ;
    END
  END wd_in[375]
  PIN wd_in[376]
    DIRECTION INPUT ;
    USE SIGNAL ;
    SHAPE ABUTMENT ;
    PORT
      LAYER M4 ;
      RECT 0.000 234.791 0.018 234.809 ;
    END
  END wd_in[376]
  PIN wd_in[377]
    DIRECTION INPUT ;
    USE SIGNAL ;
    SHAPE ABUTMENT ;
    PORT
      LAYER M4 ;
      RECT 0.000 235.043 0.018 235.061 ;
    END
  END wd_in[377]
  PIN wd_in[378]
    DIRECTION INPUT ;
    USE SIGNAL ;
    SHAPE ABUTMENT ;
    PORT
      LAYER M4 ;
      RECT 0.000 235.295 0.018 235.313 ;
    END
  END wd_in[378]
  PIN wd_in[379]
    DIRECTION INPUT ;
    USE SIGNAL ;
    SHAPE ABUTMENT ;
    PORT
      LAYER M4 ;
      RECT 0.000 235.547 0.018 235.565 ;
    END
  END wd_in[379]
  PIN wd_in[380]
    DIRECTION INPUT ;
    USE SIGNAL ;
    SHAPE ABUTMENT ;
    PORT
      LAYER M4 ;
      RECT 0.000 235.799 0.018 235.817 ;
    END
  END wd_in[380]
  PIN wd_in[381]
    DIRECTION INPUT ;
    USE SIGNAL ;
    SHAPE ABUTMENT ;
    PORT
      LAYER M4 ;
      RECT 0.000 236.051 0.018 236.069 ;
    END
  END wd_in[381]
  PIN wd_in[382]
    DIRECTION INPUT ;
    USE SIGNAL ;
    SHAPE ABUTMENT ;
    PORT
      LAYER M4 ;
      RECT 0.000 236.303 0.018 236.321 ;
    END
  END wd_in[382]
  PIN wd_in[383]
    DIRECTION INPUT ;
    USE SIGNAL ;
    SHAPE ABUTMENT ;
    PORT
      LAYER M4 ;
      RECT 0.000 236.555 0.018 236.573 ;
    END
  END wd_in[383]
  PIN wd_in[384]
    DIRECTION INPUT ;
    USE SIGNAL ;
    SHAPE ABUTMENT ;
    PORT
      LAYER M4 ;
      RECT 0.000 236.807 0.018 236.825 ;
    END
  END wd_in[384]
  PIN wd_in[385]
    DIRECTION INPUT ;
    USE SIGNAL ;
    SHAPE ABUTMENT ;
    PORT
      LAYER M4 ;
      RECT 0.000 237.059 0.018 237.077 ;
    END
  END wd_in[385]
  PIN wd_in[386]
    DIRECTION INPUT ;
    USE SIGNAL ;
    SHAPE ABUTMENT ;
    PORT
      LAYER M4 ;
      RECT 0.000 237.311 0.018 237.329 ;
    END
  END wd_in[386]
  PIN wd_in[387]
    DIRECTION INPUT ;
    USE SIGNAL ;
    SHAPE ABUTMENT ;
    PORT
      LAYER M4 ;
      RECT 0.000 237.563 0.018 237.581 ;
    END
  END wd_in[387]
  PIN wd_in[388]
    DIRECTION INPUT ;
    USE SIGNAL ;
    SHAPE ABUTMENT ;
    PORT
      LAYER M4 ;
      RECT 0.000 237.815 0.018 237.833 ;
    END
  END wd_in[388]
  PIN wd_in[389]
    DIRECTION INPUT ;
    USE SIGNAL ;
    SHAPE ABUTMENT ;
    PORT
      LAYER M4 ;
      RECT 0.000 238.067 0.018 238.085 ;
    END
  END wd_in[389]
  PIN wd_in[390]
    DIRECTION INPUT ;
    USE SIGNAL ;
    SHAPE ABUTMENT ;
    PORT
      LAYER M4 ;
      RECT 0.000 238.319 0.018 238.337 ;
    END
  END wd_in[390]
  PIN wd_in[391]
    DIRECTION INPUT ;
    USE SIGNAL ;
    SHAPE ABUTMENT ;
    PORT
      LAYER M4 ;
      RECT 0.000 238.571 0.018 238.589 ;
    END
  END wd_in[391]
  PIN wd_in[392]
    DIRECTION INPUT ;
    USE SIGNAL ;
    SHAPE ABUTMENT ;
    PORT
      LAYER M4 ;
      RECT 0.000 238.823 0.018 238.841 ;
    END
  END wd_in[392]
  PIN wd_in[393]
    DIRECTION INPUT ;
    USE SIGNAL ;
    SHAPE ABUTMENT ;
    PORT
      LAYER M4 ;
      RECT 0.000 239.075 0.018 239.093 ;
    END
  END wd_in[393]
  PIN wd_in[394]
    DIRECTION INPUT ;
    USE SIGNAL ;
    SHAPE ABUTMENT ;
    PORT
      LAYER M4 ;
      RECT 0.000 239.327 0.018 239.345 ;
    END
  END wd_in[394]
  PIN wd_in[395]
    DIRECTION INPUT ;
    USE SIGNAL ;
    SHAPE ABUTMENT ;
    PORT
      LAYER M4 ;
      RECT 0.000 239.579 0.018 239.597 ;
    END
  END wd_in[395]
  PIN wd_in[396]
    DIRECTION INPUT ;
    USE SIGNAL ;
    SHAPE ABUTMENT ;
    PORT
      LAYER M4 ;
      RECT 0.000 239.831 0.018 239.849 ;
    END
  END wd_in[396]
  PIN wd_in[397]
    DIRECTION INPUT ;
    USE SIGNAL ;
    SHAPE ABUTMENT ;
    PORT
      LAYER M4 ;
      RECT 0.000 240.083 0.018 240.101 ;
    END
  END wd_in[397]
  PIN wd_in[398]
    DIRECTION INPUT ;
    USE SIGNAL ;
    SHAPE ABUTMENT ;
    PORT
      LAYER M4 ;
      RECT 0.000 240.335 0.018 240.353 ;
    END
  END wd_in[398]
  PIN wd_in[399]
    DIRECTION INPUT ;
    USE SIGNAL ;
    SHAPE ABUTMENT ;
    PORT
      LAYER M4 ;
      RECT 0.000 240.587 0.018 240.605 ;
    END
  END wd_in[399]
  PIN wd_in[400]
    DIRECTION INPUT ;
    USE SIGNAL ;
    SHAPE ABUTMENT ;
    PORT
      LAYER M4 ;
      RECT 0.000 240.839 0.018 240.857 ;
    END
  END wd_in[400]
  PIN wd_in[401]
    DIRECTION INPUT ;
    USE SIGNAL ;
    SHAPE ABUTMENT ;
    PORT
      LAYER M4 ;
      RECT 0.000 241.091 0.018 241.109 ;
    END
  END wd_in[401]
  PIN wd_in[402]
    DIRECTION INPUT ;
    USE SIGNAL ;
    SHAPE ABUTMENT ;
    PORT
      LAYER M4 ;
      RECT 0.000 241.343 0.018 241.361 ;
    END
  END wd_in[402]
  PIN wd_in[403]
    DIRECTION INPUT ;
    USE SIGNAL ;
    SHAPE ABUTMENT ;
    PORT
      LAYER M4 ;
      RECT 0.000 241.595 0.018 241.613 ;
    END
  END wd_in[403]
  PIN wd_in[404]
    DIRECTION INPUT ;
    USE SIGNAL ;
    SHAPE ABUTMENT ;
    PORT
      LAYER M4 ;
      RECT 0.000 241.847 0.018 241.865 ;
    END
  END wd_in[404]
  PIN wd_in[405]
    DIRECTION INPUT ;
    USE SIGNAL ;
    SHAPE ABUTMENT ;
    PORT
      LAYER M4 ;
      RECT 0.000 242.099 0.018 242.117 ;
    END
  END wd_in[405]
  PIN wd_in[406]
    DIRECTION INPUT ;
    USE SIGNAL ;
    SHAPE ABUTMENT ;
    PORT
      LAYER M4 ;
      RECT 0.000 242.351 0.018 242.369 ;
    END
  END wd_in[406]
  PIN wd_in[407]
    DIRECTION INPUT ;
    USE SIGNAL ;
    SHAPE ABUTMENT ;
    PORT
      LAYER M4 ;
      RECT 0.000 242.603 0.018 242.621 ;
    END
  END wd_in[407]
  PIN wd_in[408]
    DIRECTION INPUT ;
    USE SIGNAL ;
    SHAPE ABUTMENT ;
    PORT
      LAYER M4 ;
      RECT 0.000 242.855 0.018 242.873 ;
    END
  END wd_in[408]
  PIN wd_in[409]
    DIRECTION INPUT ;
    USE SIGNAL ;
    SHAPE ABUTMENT ;
    PORT
      LAYER M4 ;
      RECT 0.000 243.107 0.018 243.125 ;
    END
  END wd_in[409]
  PIN wd_in[410]
    DIRECTION INPUT ;
    USE SIGNAL ;
    SHAPE ABUTMENT ;
    PORT
      LAYER M4 ;
      RECT 0.000 243.359 0.018 243.377 ;
    END
  END wd_in[410]
  PIN wd_in[411]
    DIRECTION INPUT ;
    USE SIGNAL ;
    SHAPE ABUTMENT ;
    PORT
      LAYER M4 ;
      RECT 0.000 243.611 0.018 243.629 ;
    END
  END wd_in[411]
  PIN wd_in[412]
    DIRECTION INPUT ;
    USE SIGNAL ;
    SHAPE ABUTMENT ;
    PORT
      LAYER M4 ;
      RECT 0.000 243.863 0.018 243.881 ;
    END
  END wd_in[412]
  PIN wd_in[413]
    DIRECTION INPUT ;
    USE SIGNAL ;
    SHAPE ABUTMENT ;
    PORT
      LAYER M4 ;
      RECT 0.000 244.115 0.018 244.133 ;
    END
  END wd_in[413]
  PIN wd_in[414]
    DIRECTION INPUT ;
    USE SIGNAL ;
    SHAPE ABUTMENT ;
    PORT
      LAYER M4 ;
      RECT 0.000 244.367 0.018 244.385 ;
    END
  END wd_in[414]
  PIN wd_in[415]
    DIRECTION INPUT ;
    USE SIGNAL ;
    SHAPE ABUTMENT ;
    PORT
      LAYER M4 ;
      RECT 0.000 244.619 0.018 244.637 ;
    END
  END wd_in[415]
  PIN wd_in[416]
    DIRECTION INPUT ;
    USE SIGNAL ;
    SHAPE ABUTMENT ;
    PORT
      LAYER M4 ;
      RECT 0.000 244.871 0.018 244.889 ;
    END
  END wd_in[416]
  PIN wd_in[417]
    DIRECTION INPUT ;
    USE SIGNAL ;
    SHAPE ABUTMENT ;
    PORT
      LAYER M4 ;
      RECT 0.000 245.123 0.018 245.141 ;
    END
  END wd_in[417]
  PIN wd_in[418]
    DIRECTION INPUT ;
    USE SIGNAL ;
    SHAPE ABUTMENT ;
    PORT
      LAYER M4 ;
      RECT 0.000 245.375 0.018 245.393 ;
    END
  END wd_in[418]
  PIN wd_in[419]
    DIRECTION INPUT ;
    USE SIGNAL ;
    SHAPE ABUTMENT ;
    PORT
      LAYER M4 ;
      RECT 0.000 245.627 0.018 245.645 ;
    END
  END wd_in[419]
  PIN wd_in[420]
    DIRECTION INPUT ;
    USE SIGNAL ;
    SHAPE ABUTMENT ;
    PORT
      LAYER M4 ;
      RECT 0.000 245.879 0.018 245.897 ;
    END
  END wd_in[420]
  PIN wd_in[421]
    DIRECTION INPUT ;
    USE SIGNAL ;
    SHAPE ABUTMENT ;
    PORT
      LAYER M4 ;
      RECT 0.000 246.131 0.018 246.149 ;
    END
  END wd_in[421]
  PIN wd_in[422]
    DIRECTION INPUT ;
    USE SIGNAL ;
    SHAPE ABUTMENT ;
    PORT
      LAYER M4 ;
      RECT 0.000 246.383 0.018 246.401 ;
    END
  END wd_in[422]
  PIN wd_in[423]
    DIRECTION INPUT ;
    USE SIGNAL ;
    SHAPE ABUTMENT ;
    PORT
      LAYER M4 ;
      RECT 0.000 246.635 0.018 246.653 ;
    END
  END wd_in[423]
  PIN wd_in[424]
    DIRECTION INPUT ;
    USE SIGNAL ;
    SHAPE ABUTMENT ;
    PORT
      LAYER M4 ;
      RECT 0.000 246.887 0.018 246.905 ;
    END
  END wd_in[424]
  PIN wd_in[425]
    DIRECTION INPUT ;
    USE SIGNAL ;
    SHAPE ABUTMENT ;
    PORT
      LAYER M4 ;
      RECT 0.000 247.139 0.018 247.157 ;
    END
  END wd_in[425]
  PIN wd_in[426]
    DIRECTION INPUT ;
    USE SIGNAL ;
    SHAPE ABUTMENT ;
    PORT
      LAYER M4 ;
      RECT 0.000 247.391 0.018 247.409 ;
    END
  END wd_in[426]
  PIN wd_in[427]
    DIRECTION INPUT ;
    USE SIGNAL ;
    SHAPE ABUTMENT ;
    PORT
      LAYER M4 ;
      RECT 0.000 247.643 0.018 247.661 ;
    END
  END wd_in[427]
  PIN wd_in[428]
    DIRECTION INPUT ;
    USE SIGNAL ;
    SHAPE ABUTMENT ;
    PORT
      LAYER M4 ;
      RECT 0.000 247.895 0.018 247.913 ;
    END
  END wd_in[428]
  PIN wd_in[429]
    DIRECTION INPUT ;
    USE SIGNAL ;
    SHAPE ABUTMENT ;
    PORT
      LAYER M4 ;
      RECT 0.000 248.147 0.018 248.165 ;
    END
  END wd_in[429]
  PIN wd_in[430]
    DIRECTION INPUT ;
    USE SIGNAL ;
    SHAPE ABUTMENT ;
    PORT
      LAYER M4 ;
      RECT 0.000 248.399 0.018 248.417 ;
    END
  END wd_in[430]
  PIN wd_in[431]
    DIRECTION INPUT ;
    USE SIGNAL ;
    SHAPE ABUTMENT ;
    PORT
      LAYER M4 ;
      RECT 0.000 248.651 0.018 248.669 ;
    END
  END wd_in[431]
  PIN wd_in[432]
    DIRECTION INPUT ;
    USE SIGNAL ;
    SHAPE ABUTMENT ;
    PORT
      LAYER M4 ;
      RECT 0.000 248.903 0.018 248.921 ;
    END
  END wd_in[432]
  PIN wd_in[433]
    DIRECTION INPUT ;
    USE SIGNAL ;
    SHAPE ABUTMENT ;
    PORT
      LAYER M4 ;
      RECT 0.000 249.155 0.018 249.173 ;
    END
  END wd_in[433]
  PIN wd_in[434]
    DIRECTION INPUT ;
    USE SIGNAL ;
    SHAPE ABUTMENT ;
    PORT
      LAYER M4 ;
      RECT 0.000 249.407 0.018 249.425 ;
    END
  END wd_in[434]
  PIN wd_in[435]
    DIRECTION INPUT ;
    USE SIGNAL ;
    SHAPE ABUTMENT ;
    PORT
      LAYER M4 ;
      RECT 0.000 249.659 0.018 249.677 ;
    END
  END wd_in[435]
  PIN wd_in[436]
    DIRECTION INPUT ;
    USE SIGNAL ;
    SHAPE ABUTMENT ;
    PORT
      LAYER M4 ;
      RECT 0.000 249.911 0.018 249.929 ;
    END
  END wd_in[436]
  PIN wd_in[437]
    DIRECTION INPUT ;
    USE SIGNAL ;
    SHAPE ABUTMENT ;
    PORT
      LAYER M4 ;
      RECT 0.000 250.163 0.018 250.181 ;
    END
  END wd_in[437]
  PIN wd_in[438]
    DIRECTION INPUT ;
    USE SIGNAL ;
    SHAPE ABUTMENT ;
    PORT
      LAYER M4 ;
      RECT 0.000 250.415 0.018 250.433 ;
    END
  END wd_in[438]
  PIN wd_in[439]
    DIRECTION INPUT ;
    USE SIGNAL ;
    SHAPE ABUTMENT ;
    PORT
      LAYER M4 ;
      RECT 0.000 250.667 0.018 250.685 ;
    END
  END wd_in[439]
  PIN wd_in[440]
    DIRECTION INPUT ;
    USE SIGNAL ;
    SHAPE ABUTMENT ;
    PORT
      LAYER M4 ;
      RECT 0.000 250.919 0.018 250.937 ;
    END
  END wd_in[440]
  PIN wd_in[441]
    DIRECTION INPUT ;
    USE SIGNAL ;
    SHAPE ABUTMENT ;
    PORT
      LAYER M4 ;
      RECT 0.000 251.171 0.018 251.189 ;
    END
  END wd_in[441]
  PIN wd_in[442]
    DIRECTION INPUT ;
    USE SIGNAL ;
    SHAPE ABUTMENT ;
    PORT
      LAYER M4 ;
      RECT 0.000 251.423 0.018 251.441 ;
    END
  END wd_in[442]
  PIN wd_in[443]
    DIRECTION INPUT ;
    USE SIGNAL ;
    SHAPE ABUTMENT ;
    PORT
      LAYER M4 ;
      RECT 0.000 251.675 0.018 251.693 ;
    END
  END wd_in[443]
  PIN wd_in[444]
    DIRECTION INPUT ;
    USE SIGNAL ;
    SHAPE ABUTMENT ;
    PORT
      LAYER M4 ;
      RECT 0.000 251.927 0.018 251.945 ;
    END
  END wd_in[444]
  PIN wd_in[445]
    DIRECTION INPUT ;
    USE SIGNAL ;
    SHAPE ABUTMENT ;
    PORT
      LAYER M4 ;
      RECT 0.000 252.179 0.018 252.197 ;
    END
  END wd_in[445]
  PIN wd_in[446]
    DIRECTION INPUT ;
    USE SIGNAL ;
    SHAPE ABUTMENT ;
    PORT
      LAYER M4 ;
      RECT 0.000 252.431 0.018 252.449 ;
    END
  END wd_in[446]
  PIN wd_in[447]
    DIRECTION INPUT ;
    USE SIGNAL ;
    SHAPE ABUTMENT ;
    PORT
      LAYER M4 ;
      RECT 0.000 252.683 0.018 252.701 ;
    END
  END wd_in[447]
  PIN wd_in[448]
    DIRECTION INPUT ;
    USE SIGNAL ;
    SHAPE ABUTMENT ;
    PORT
      LAYER M4 ;
      RECT 0.000 252.935 0.018 252.953 ;
    END
  END wd_in[448]
  PIN wd_in[449]
    DIRECTION INPUT ;
    USE SIGNAL ;
    SHAPE ABUTMENT ;
    PORT
      LAYER M4 ;
      RECT 0.000 253.187 0.018 253.205 ;
    END
  END wd_in[449]
  PIN wd_in[450]
    DIRECTION INPUT ;
    USE SIGNAL ;
    SHAPE ABUTMENT ;
    PORT
      LAYER M4 ;
      RECT 0.000 253.439 0.018 253.457 ;
    END
  END wd_in[450]
  PIN wd_in[451]
    DIRECTION INPUT ;
    USE SIGNAL ;
    SHAPE ABUTMENT ;
    PORT
      LAYER M4 ;
      RECT 0.000 253.691 0.018 253.709 ;
    END
  END wd_in[451]
  PIN wd_in[452]
    DIRECTION INPUT ;
    USE SIGNAL ;
    SHAPE ABUTMENT ;
    PORT
      LAYER M4 ;
      RECT 0.000 253.943 0.018 253.961 ;
    END
  END wd_in[452]
  PIN wd_in[453]
    DIRECTION INPUT ;
    USE SIGNAL ;
    SHAPE ABUTMENT ;
    PORT
      LAYER M4 ;
      RECT 0.000 254.195 0.018 254.213 ;
    END
  END wd_in[453]
  PIN wd_in[454]
    DIRECTION INPUT ;
    USE SIGNAL ;
    SHAPE ABUTMENT ;
    PORT
      LAYER M4 ;
      RECT 0.000 254.447 0.018 254.465 ;
    END
  END wd_in[454]
  PIN wd_in[455]
    DIRECTION INPUT ;
    USE SIGNAL ;
    SHAPE ABUTMENT ;
    PORT
      LAYER M4 ;
      RECT 0.000 254.699 0.018 254.717 ;
    END
  END wd_in[455]
  PIN wd_in[456]
    DIRECTION INPUT ;
    USE SIGNAL ;
    SHAPE ABUTMENT ;
    PORT
      LAYER M4 ;
      RECT 0.000 254.951 0.018 254.969 ;
    END
  END wd_in[456]
  PIN wd_in[457]
    DIRECTION INPUT ;
    USE SIGNAL ;
    SHAPE ABUTMENT ;
    PORT
      LAYER M4 ;
      RECT 0.000 255.203 0.018 255.221 ;
    END
  END wd_in[457]
  PIN wd_in[458]
    DIRECTION INPUT ;
    USE SIGNAL ;
    SHAPE ABUTMENT ;
    PORT
      LAYER M4 ;
      RECT 0.000 255.455 0.018 255.473 ;
    END
  END wd_in[458]
  PIN wd_in[459]
    DIRECTION INPUT ;
    USE SIGNAL ;
    SHAPE ABUTMENT ;
    PORT
      LAYER M4 ;
      RECT 0.000 255.707 0.018 255.725 ;
    END
  END wd_in[459]
  PIN wd_in[460]
    DIRECTION INPUT ;
    USE SIGNAL ;
    SHAPE ABUTMENT ;
    PORT
      LAYER M4 ;
      RECT 0.000 255.959 0.018 255.977 ;
    END
  END wd_in[460]
  PIN wd_in[461]
    DIRECTION INPUT ;
    USE SIGNAL ;
    SHAPE ABUTMENT ;
    PORT
      LAYER M4 ;
      RECT 0.000 256.211 0.018 256.229 ;
    END
  END wd_in[461]
  PIN wd_in[462]
    DIRECTION INPUT ;
    USE SIGNAL ;
    SHAPE ABUTMENT ;
    PORT
      LAYER M4 ;
      RECT 0.000 256.463 0.018 256.481 ;
    END
  END wd_in[462]
  PIN wd_in[463]
    DIRECTION INPUT ;
    USE SIGNAL ;
    SHAPE ABUTMENT ;
    PORT
      LAYER M4 ;
      RECT 0.000 256.715 0.018 256.733 ;
    END
  END wd_in[463]
  PIN wd_in[464]
    DIRECTION INPUT ;
    USE SIGNAL ;
    SHAPE ABUTMENT ;
    PORT
      LAYER M4 ;
      RECT 0.000 256.967 0.018 256.985 ;
    END
  END wd_in[464]
  PIN wd_in[465]
    DIRECTION INPUT ;
    USE SIGNAL ;
    SHAPE ABUTMENT ;
    PORT
      LAYER M4 ;
      RECT 0.000 257.219 0.018 257.237 ;
    END
  END wd_in[465]
  PIN wd_in[466]
    DIRECTION INPUT ;
    USE SIGNAL ;
    SHAPE ABUTMENT ;
    PORT
      LAYER M4 ;
      RECT 0.000 257.471 0.018 257.489 ;
    END
  END wd_in[466]
  PIN wd_in[467]
    DIRECTION INPUT ;
    USE SIGNAL ;
    SHAPE ABUTMENT ;
    PORT
      LAYER M4 ;
      RECT 0.000 257.723 0.018 257.741 ;
    END
  END wd_in[467]
  PIN wd_in[468]
    DIRECTION INPUT ;
    USE SIGNAL ;
    SHAPE ABUTMENT ;
    PORT
      LAYER M4 ;
      RECT 0.000 257.975 0.018 257.993 ;
    END
  END wd_in[468]
  PIN wd_in[469]
    DIRECTION INPUT ;
    USE SIGNAL ;
    SHAPE ABUTMENT ;
    PORT
      LAYER M4 ;
      RECT 0.000 258.227 0.018 258.245 ;
    END
  END wd_in[469]
  PIN wd_in[470]
    DIRECTION INPUT ;
    USE SIGNAL ;
    SHAPE ABUTMENT ;
    PORT
      LAYER M4 ;
      RECT 0.000 258.479 0.018 258.497 ;
    END
  END wd_in[470]
  PIN wd_in[471]
    DIRECTION INPUT ;
    USE SIGNAL ;
    SHAPE ABUTMENT ;
    PORT
      LAYER M4 ;
      RECT 0.000 258.731 0.018 258.749 ;
    END
  END wd_in[471]
  PIN wd_in[472]
    DIRECTION INPUT ;
    USE SIGNAL ;
    SHAPE ABUTMENT ;
    PORT
      LAYER M4 ;
      RECT 0.000 258.983 0.018 259.001 ;
    END
  END wd_in[472]
  PIN wd_in[473]
    DIRECTION INPUT ;
    USE SIGNAL ;
    SHAPE ABUTMENT ;
    PORT
      LAYER M4 ;
      RECT 0.000 259.235 0.018 259.253 ;
    END
  END wd_in[473]
  PIN wd_in[474]
    DIRECTION INPUT ;
    USE SIGNAL ;
    SHAPE ABUTMENT ;
    PORT
      LAYER M4 ;
      RECT 0.000 259.487 0.018 259.505 ;
    END
  END wd_in[474]
  PIN wd_in[475]
    DIRECTION INPUT ;
    USE SIGNAL ;
    SHAPE ABUTMENT ;
    PORT
      LAYER M4 ;
      RECT 0.000 259.739 0.018 259.757 ;
    END
  END wd_in[475]
  PIN wd_in[476]
    DIRECTION INPUT ;
    USE SIGNAL ;
    SHAPE ABUTMENT ;
    PORT
      LAYER M4 ;
      RECT 0.000 259.991 0.018 260.009 ;
    END
  END wd_in[476]
  PIN wd_in[477]
    DIRECTION INPUT ;
    USE SIGNAL ;
    SHAPE ABUTMENT ;
    PORT
      LAYER M4 ;
      RECT 0.000 260.243 0.018 260.261 ;
    END
  END wd_in[477]
  PIN wd_in[478]
    DIRECTION INPUT ;
    USE SIGNAL ;
    SHAPE ABUTMENT ;
    PORT
      LAYER M4 ;
      RECT 0.000 260.495 0.018 260.513 ;
    END
  END wd_in[478]
  PIN wd_in[479]
    DIRECTION INPUT ;
    USE SIGNAL ;
    SHAPE ABUTMENT ;
    PORT
      LAYER M4 ;
      RECT 0.000 260.747 0.018 260.765 ;
    END
  END wd_in[479]
  PIN wd_in[480]
    DIRECTION INPUT ;
    USE SIGNAL ;
    SHAPE ABUTMENT ;
    PORT
      LAYER M4 ;
      RECT 0.000 260.999 0.018 261.017 ;
    END
  END wd_in[480]
  PIN wd_in[481]
    DIRECTION INPUT ;
    USE SIGNAL ;
    SHAPE ABUTMENT ;
    PORT
      LAYER M4 ;
      RECT 0.000 261.251 0.018 261.269 ;
    END
  END wd_in[481]
  PIN wd_in[482]
    DIRECTION INPUT ;
    USE SIGNAL ;
    SHAPE ABUTMENT ;
    PORT
      LAYER M4 ;
      RECT 0.000 261.503 0.018 261.521 ;
    END
  END wd_in[482]
  PIN wd_in[483]
    DIRECTION INPUT ;
    USE SIGNAL ;
    SHAPE ABUTMENT ;
    PORT
      LAYER M4 ;
      RECT 0.000 261.755 0.018 261.773 ;
    END
  END wd_in[483]
  PIN wd_in[484]
    DIRECTION INPUT ;
    USE SIGNAL ;
    SHAPE ABUTMENT ;
    PORT
      LAYER M4 ;
      RECT 0.000 262.007 0.018 262.025 ;
    END
  END wd_in[484]
  PIN wd_in[485]
    DIRECTION INPUT ;
    USE SIGNAL ;
    SHAPE ABUTMENT ;
    PORT
      LAYER M4 ;
      RECT 0.000 262.259 0.018 262.277 ;
    END
  END wd_in[485]
  PIN wd_in[486]
    DIRECTION INPUT ;
    USE SIGNAL ;
    SHAPE ABUTMENT ;
    PORT
      LAYER M4 ;
      RECT 0.000 262.511 0.018 262.529 ;
    END
  END wd_in[486]
  PIN wd_in[487]
    DIRECTION INPUT ;
    USE SIGNAL ;
    SHAPE ABUTMENT ;
    PORT
      LAYER M4 ;
      RECT 0.000 262.763 0.018 262.781 ;
    END
  END wd_in[487]
  PIN wd_in[488]
    DIRECTION INPUT ;
    USE SIGNAL ;
    SHAPE ABUTMENT ;
    PORT
      LAYER M4 ;
      RECT 0.000 263.015 0.018 263.033 ;
    END
  END wd_in[488]
  PIN wd_in[489]
    DIRECTION INPUT ;
    USE SIGNAL ;
    SHAPE ABUTMENT ;
    PORT
      LAYER M4 ;
      RECT 0.000 263.267 0.018 263.285 ;
    END
  END wd_in[489]
  PIN wd_in[490]
    DIRECTION INPUT ;
    USE SIGNAL ;
    SHAPE ABUTMENT ;
    PORT
      LAYER M4 ;
      RECT 0.000 263.519 0.018 263.537 ;
    END
  END wd_in[490]
  PIN wd_in[491]
    DIRECTION INPUT ;
    USE SIGNAL ;
    SHAPE ABUTMENT ;
    PORT
      LAYER M4 ;
      RECT 0.000 263.771 0.018 263.789 ;
    END
  END wd_in[491]
  PIN wd_in[492]
    DIRECTION INPUT ;
    USE SIGNAL ;
    SHAPE ABUTMENT ;
    PORT
      LAYER M4 ;
      RECT 0.000 264.023 0.018 264.041 ;
    END
  END wd_in[492]
  PIN wd_in[493]
    DIRECTION INPUT ;
    USE SIGNAL ;
    SHAPE ABUTMENT ;
    PORT
      LAYER M4 ;
      RECT 0.000 264.275 0.018 264.293 ;
    END
  END wd_in[493]
  PIN wd_in[494]
    DIRECTION INPUT ;
    USE SIGNAL ;
    SHAPE ABUTMENT ;
    PORT
      LAYER M4 ;
      RECT 0.000 264.527 0.018 264.545 ;
    END
  END wd_in[494]
  PIN wd_in[495]
    DIRECTION INPUT ;
    USE SIGNAL ;
    SHAPE ABUTMENT ;
    PORT
      LAYER M4 ;
      RECT 0.000 264.779 0.018 264.797 ;
    END
  END wd_in[495]
  PIN wd_in[496]
    DIRECTION INPUT ;
    USE SIGNAL ;
    SHAPE ABUTMENT ;
    PORT
      LAYER M4 ;
      RECT 0.000 265.031 0.018 265.049 ;
    END
  END wd_in[496]
  PIN wd_in[497]
    DIRECTION INPUT ;
    USE SIGNAL ;
    SHAPE ABUTMENT ;
    PORT
      LAYER M4 ;
      RECT 0.000 265.283 0.018 265.301 ;
    END
  END wd_in[497]
  PIN wd_in[498]
    DIRECTION INPUT ;
    USE SIGNAL ;
    SHAPE ABUTMENT ;
    PORT
      LAYER M4 ;
      RECT 0.000 265.535 0.018 265.553 ;
    END
  END wd_in[498]
  PIN wd_in[499]
    DIRECTION INPUT ;
    USE SIGNAL ;
    SHAPE ABUTMENT ;
    PORT
      LAYER M4 ;
      RECT 0.000 265.787 0.018 265.805 ;
    END
  END wd_in[499]
  PIN wd_in[500]
    DIRECTION INPUT ;
    USE SIGNAL ;
    SHAPE ABUTMENT ;
    PORT
      LAYER M4 ;
      RECT 0.000 266.039 0.018 266.057 ;
    END
  END wd_in[500]
  PIN wd_in[501]
    DIRECTION INPUT ;
    USE SIGNAL ;
    SHAPE ABUTMENT ;
    PORT
      LAYER M4 ;
      RECT 0.000 266.291 0.018 266.309 ;
    END
  END wd_in[501]
  PIN wd_in[502]
    DIRECTION INPUT ;
    USE SIGNAL ;
    SHAPE ABUTMENT ;
    PORT
      LAYER M4 ;
      RECT 0.000 266.543 0.018 266.561 ;
    END
  END wd_in[502]
  PIN wd_in[503]
    DIRECTION INPUT ;
    USE SIGNAL ;
    SHAPE ABUTMENT ;
    PORT
      LAYER M4 ;
      RECT 0.000 266.795 0.018 266.813 ;
    END
  END wd_in[503]
  PIN wd_in[504]
    DIRECTION INPUT ;
    USE SIGNAL ;
    SHAPE ABUTMENT ;
    PORT
      LAYER M4 ;
      RECT 0.000 267.047 0.018 267.065 ;
    END
  END wd_in[504]
  PIN wd_in[505]
    DIRECTION INPUT ;
    USE SIGNAL ;
    SHAPE ABUTMENT ;
    PORT
      LAYER M4 ;
      RECT 0.000 267.299 0.018 267.317 ;
    END
  END wd_in[505]
  PIN wd_in[506]
    DIRECTION INPUT ;
    USE SIGNAL ;
    SHAPE ABUTMENT ;
    PORT
      LAYER M4 ;
      RECT 0.000 267.551 0.018 267.569 ;
    END
  END wd_in[506]
  PIN wd_in[507]
    DIRECTION INPUT ;
    USE SIGNAL ;
    SHAPE ABUTMENT ;
    PORT
      LAYER M4 ;
      RECT 0.000 267.803 0.018 267.821 ;
    END
  END wd_in[507]
  PIN wd_in[508]
    DIRECTION INPUT ;
    USE SIGNAL ;
    SHAPE ABUTMENT ;
    PORT
      LAYER M4 ;
      RECT 0.000 268.055 0.018 268.073 ;
    END
  END wd_in[508]
  PIN wd_in[509]
    DIRECTION INPUT ;
    USE SIGNAL ;
    SHAPE ABUTMENT ;
    PORT
      LAYER M4 ;
      RECT 0.000 268.307 0.018 268.325 ;
    END
  END wd_in[509]
  PIN wd_in[510]
    DIRECTION INPUT ;
    USE SIGNAL ;
    SHAPE ABUTMENT ;
    PORT
      LAYER M4 ;
      RECT 0.000 268.559 0.018 268.577 ;
    END
  END wd_in[510]
  PIN wd_in[511]
    DIRECTION INPUT ;
    USE SIGNAL ;
    SHAPE ABUTMENT ;
    PORT
      LAYER M4 ;
      RECT 0.000 268.811 0.018 268.829 ;
    END
  END wd_in[511]
  PIN addr_in[0]
    DIRECTION INPUT ;
    USE SIGNAL ;
    SHAPE ABUTMENT ;
    PORT
      LAYER M4 ;
      RECT 0.000 280.043 0.018 280.061 ;
    END
  END addr_in[0]
  PIN addr_in[1]
    DIRECTION INPUT ;
    USE SIGNAL ;
    SHAPE ABUTMENT ;
    PORT
      LAYER M4 ;
      RECT 0.000 280.295 0.018 280.313 ;
    END
  END addr_in[1]
  PIN addr_in[2]
    DIRECTION INPUT ;
    USE SIGNAL ;
    SHAPE ABUTMENT ;
    PORT
      LAYER M4 ;
      RECT 0.000 280.547 0.018 280.565 ;
    END
  END addr_in[2]
  PIN addr_in[3]
    DIRECTION INPUT ;
    USE SIGNAL ;
    SHAPE ABUTMENT ;
    PORT
      LAYER M4 ;
      RECT 0.000 280.799 0.018 280.817 ;
    END
  END addr_in[3]
  PIN addr_in[4]
    DIRECTION INPUT ;
    USE SIGNAL ;
    SHAPE ABUTMENT ;
    PORT
      LAYER M4 ;
      RECT 0.000 281.051 0.018 281.069 ;
    END
  END addr_in[4]
  PIN addr_in[5]
    DIRECTION INPUT ;
    USE SIGNAL ;
    SHAPE ABUTMENT ;
    PORT
      LAYER M4 ;
      RECT 0.000 281.303 0.018 281.321 ;
    END
  END addr_in[5]
  PIN addr_in[6]
    DIRECTION INPUT ;
    USE SIGNAL ;
    SHAPE ABUTMENT ;
    PORT
      LAYER M4 ;
      RECT 0.000 281.555 0.018 281.573 ;
    END
  END addr_in[6]
  PIN addr_in[7]
    DIRECTION INPUT ;
    USE SIGNAL ;
    SHAPE ABUTMENT ;
    PORT
      LAYER M4 ;
      RECT 0.000 281.807 0.018 281.825 ;
    END
  END addr_in[7]
  PIN addr_in[8]
    DIRECTION INPUT ;
    USE SIGNAL ;
    SHAPE ABUTMENT ;
    PORT
      LAYER M4 ;
      RECT 0.000 282.059 0.018 282.077 ;
    END
  END addr_in[8]
  PIN addr_in[9]
    DIRECTION INPUT ;
    USE SIGNAL ;
    SHAPE ABUTMENT ;
    PORT
      LAYER M4 ;
      RECT 0.000 282.311 0.018 282.329 ;
    END
  END addr_in[9]
  PIN addr_in[10]
    DIRECTION INPUT ;
    USE SIGNAL ;
    SHAPE ABUTMENT ;
    PORT
      LAYER M4 ;
      RECT 0.000 282.563 0.018 282.581 ;
    END
  END addr_in[10]
  PIN addr_in[11]
    DIRECTION INPUT ;
    USE SIGNAL ;
    SHAPE ABUTMENT ;
    PORT
      LAYER M4 ;
      RECT 0.000 282.815 0.018 282.833 ;
    END
  END addr_in[11]
  PIN we_in
    DIRECTION INPUT ;
    USE SIGNAL ;
    SHAPE ABUTMENT ;
    PORT
      LAYER M4 ;
      RECT 0.000 294.047 0.018 294.065 ;
    END
  END we_in
  PIN ce_in
    DIRECTION INPUT ;
    USE SIGNAL ;
    SHAPE ABUTMENT ;
    PORT
      LAYER M4 ;
      RECT 0.000 294.299 0.018 294.317 ;
    END
  END ce_in
  PIN clk
    DIRECTION INPUT ;
    USE SIGNAL ;
    SHAPE ABUTMENT ;
    PORT
      LAYER M4 ;
      RECT 0.000 294.551 0.018 294.569 ;
    END
  END clk
  PIN VSS
    DIRECTION INOUT ;
    USE GROUND ;
    PORT
      LAYER M4 ;
      RECT 0.036 0.000 235.894 0.072 ;
      RECT 0.036 0.576 235.894 0.648 ;
      RECT 0.036 1.152 235.894 1.224 ;
      RECT 0.036 1.728 235.894 1.800 ;
      RECT 0.036 2.304 235.894 2.376 ;
      RECT 0.036 2.880 235.894 2.952 ;
      RECT 0.036 3.456 235.894 3.528 ;
      RECT 0.036 4.032 235.894 4.104 ;
      RECT 0.036 4.608 235.894 4.680 ;
      RECT 0.036 5.184 235.894 5.256 ;
      RECT 0.036 5.760 235.894 5.832 ;
      RECT 0.036 6.336 235.894 6.408 ;
      RECT 0.036 6.912 235.894 6.984 ;
      RECT 0.036 7.488 235.894 7.560 ;
      RECT 0.036 8.064 235.894 8.136 ;
      RECT 0.036 8.640 235.894 8.712 ;
      RECT 0.036 9.216 235.894 9.288 ;
      RECT 0.036 9.792 235.894 9.864 ;
      RECT 0.036 10.368 235.894 10.440 ;
      RECT 0.036 10.944 235.894 11.016 ;
      RECT 0.036 11.520 235.894 11.592 ;
      RECT 0.036 12.096 235.894 12.168 ;
      RECT 0.036 12.672 235.894 12.744 ;
      RECT 0.036 13.248 235.894 13.320 ;
      RECT 0.036 13.824 235.894 13.896 ;
      RECT 0.036 14.400 235.894 14.472 ;
      RECT 0.036 14.976 235.894 15.048 ;
      RECT 0.036 15.552 235.894 15.624 ;
      RECT 0.036 16.128 235.894 16.200 ;
      RECT 0.036 16.704 235.894 16.776 ;
      RECT 0.036 17.280 235.894 17.352 ;
      RECT 0.036 17.856 235.894 17.928 ;
      RECT 0.036 18.432 235.894 18.504 ;
      RECT 0.036 19.008 235.894 19.080 ;
      RECT 0.036 19.584 235.894 19.656 ;
      RECT 0.036 20.160 235.894 20.232 ;
      RECT 0.036 20.736 235.894 20.808 ;
      RECT 0.036 21.312 235.894 21.384 ;
      RECT 0.036 21.888 235.894 21.960 ;
      RECT 0.036 22.464 235.894 22.536 ;
      RECT 0.036 23.040 235.894 23.112 ;
      RECT 0.036 23.616 235.894 23.688 ;
      RECT 0.036 24.192 235.894 24.264 ;
      RECT 0.036 24.768 235.894 24.840 ;
      RECT 0.036 25.344 235.894 25.416 ;
      RECT 0.036 25.920 235.894 25.992 ;
      RECT 0.036 26.496 235.894 26.568 ;
      RECT 0.036 27.072 235.894 27.144 ;
      RECT 0.036 27.648 235.894 27.720 ;
      RECT 0.036 28.224 235.894 28.296 ;
      RECT 0.036 28.800 235.894 28.872 ;
      RECT 0.036 29.376 235.894 29.448 ;
      RECT 0.036 29.952 235.894 30.024 ;
      RECT 0.036 30.528 235.894 30.600 ;
      RECT 0.036 31.104 235.894 31.176 ;
      RECT 0.036 31.680 235.894 31.752 ;
      RECT 0.036 32.256 235.894 32.328 ;
      RECT 0.036 32.832 235.894 32.904 ;
      RECT 0.036 33.408 235.894 33.480 ;
      RECT 0.036 33.984 235.894 34.056 ;
      RECT 0.036 34.560 235.894 34.632 ;
      RECT 0.036 35.136 235.894 35.208 ;
      RECT 0.036 35.712 235.894 35.784 ;
      RECT 0.036 36.288 235.894 36.360 ;
      RECT 0.036 36.864 235.894 36.936 ;
      RECT 0.036 37.440 235.894 37.512 ;
      RECT 0.036 38.016 235.894 38.088 ;
      RECT 0.036 38.592 235.894 38.664 ;
      RECT 0.036 39.168 235.894 39.240 ;
      RECT 0.036 39.744 235.894 39.816 ;
      RECT 0.036 40.320 235.894 40.392 ;
      RECT 0.036 40.896 235.894 40.968 ;
      RECT 0.036 41.472 235.894 41.544 ;
      RECT 0.036 42.048 235.894 42.120 ;
      RECT 0.036 42.624 235.894 42.696 ;
      RECT 0.036 43.200 235.894 43.272 ;
      RECT 0.036 43.776 235.894 43.848 ;
      RECT 0.036 44.352 235.894 44.424 ;
      RECT 0.036 44.928 235.894 45.000 ;
      RECT 0.036 45.504 235.894 45.576 ;
      RECT 0.036 46.080 235.894 46.152 ;
      RECT 0.036 46.656 235.894 46.728 ;
      RECT 0.036 47.232 235.894 47.304 ;
      RECT 0.036 47.808 235.894 47.880 ;
      RECT 0.036 48.384 235.894 48.456 ;
      RECT 0.036 48.960 235.894 49.032 ;
      RECT 0.036 49.536 235.894 49.608 ;
      RECT 0.036 50.112 235.894 50.184 ;
      RECT 0.036 50.688 235.894 50.760 ;
      RECT 0.036 51.264 235.894 51.336 ;
      RECT 0.036 51.840 235.894 51.912 ;
      RECT 0.036 52.416 235.894 52.488 ;
      RECT 0.036 52.992 235.894 53.064 ;
      RECT 0.036 53.568 235.894 53.640 ;
      RECT 0.036 54.144 235.894 54.216 ;
      RECT 0.036 54.720 235.894 54.792 ;
      RECT 0.036 55.296 235.894 55.368 ;
      RECT 0.036 55.872 235.894 55.944 ;
      RECT 0.036 56.448 235.894 56.520 ;
      RECT 0.036 57.024 235.894 57.096 ;
      RECT 0.036 57.600 235.894 57.672 ;
      RECT 0.036 58.176 235.894 58.248 ;
      RECT 0.036 58.752 235.894 58.824 ;
      RECT 0.036 59.328 235.894 59.400 ;
      RECT 0.036 59.904 235.894 59.976 ;
      RECT 0.036 60.480 235.894 60.552 ;
      RECT 0.036 61.056 235.894 61.128 ;
      RECT 0.036 61.632 235.894 61.704 ;
      RECT 0.036 62.208 235.894 62.280 ;
      RECT 0.036 62.784 235.894 62.856 ;
      RECT 0.036 63.360 235.894 63.432 ;
      RECT 0.036 63.936 235.894 64.008 ;
      RECT 0.036 64.512 235.894 64.584 ;
      RECT 0.036 65.088 235.894 65.160 ;
      RECT 0.036 65.664 235.894 65.736 ;
      RECT 0.036 66.240 235.894 66.312 ;
      RECT 0.036 66.816 235.894 66.888 ;
      RECT 0.036 67.392 235.894 67.464 ;
      RECT 0.036 67.968 235.894 68.040 ;
      RECT 0.036 68.544 235.894 68.616 ;
      RECT 0.036 69.120 235.894 69.192 ;
      RECT 0.036 69.696 235.894 69.768 ;
      RECT 0.036 70.272 235.894 70.344 ;
      RECT 0.036 70.848 235.894 70.920 ;
      RECT 0.036 71.424 235.894 71.496 ;
      RECT 0.036 72.000 235.894 72.072 ;
      RECT 0.036 72.576 235.894 72.648 ;
      RECT 0.036 73.152 235.894 73.224 ;
      RECT 0.036 73.728 235.894 73.800 ;
      RECT 0.036 74.304 235.894 74.376 ;
      RECT 0.036 74.880 235.894 74.952 ;
      RECT 0.036 75.456 235.894 75.528 ;
      RECT 0.036 76.032 235.894 76.104 ;
      RECT 0.036 76.608 235.894 76.680 ;
      RECT 0.036 77.184 235.894 77.256 ;
      RECT 0.036 77.760 235.894 77.832 ;
      RECT 0.036 78.336 235.894 78.408 ;
      RECT 0.036 78.912 235.894 78.984 ;
      RECT 0.036 79.488 235.894 79.560 ;
      RECT 0.036 80.064 235.894 80.136 ;
      RECT 0.036 80.640 235.894 80.712 ;
      RECT 0.036 81.216 235.894 81.288 ;
      RECT 0.036 81.792 235.894 81.864 ;
      RECT 0.036 82.368 235.894 82.440 ;
      RECT 0.036 82.944 235.894 83.016 ;
      RECT 0.036 83.520 235.894 83.592 ;
      RECT 0.036 84.096 235.894 84.168 ;
      RECT 0.036 84.672 235.894 84.744 ;
      RECT 0.036 85.248 235.894 85.320 ;
      RECT 0.036 85.824 235.894 85.896 ;
      RECT 0.036 86.400 235.894 86.472 ;
      RECT 0.036 86.976 235.894 87.048 ;
      RECT 0.036 87.552 235.894 87.624 ;
      RECT 0.036 88.128 235.894 88.200 ;
      RECT 0.036 88.704 235.894 88.776 ;
      RECT 0.036 89.280 235.894 89.352 ;
      RECT 0.036 89.856 235.894 89.928 ;
      RECT 0.036 90.432 235.894 90.504 ;
      RECT 0.036 91.008 235.894 91.080 ;
      RECT 0.036 91.584 235.894 91.656 ;
      RECT 0.036 92.160 235.894 92.232 ;
      RECT 0.036 92.736 235.894 92.808 ;
      RECT 0.036 93.312 235.894 93.384 ;
      RECT 0.036 93.888 235.894 93.960 ;
      RECT 0.036 94.464 235.894 94.536 ;
      RECT 0.036 95.040 235.894 95.112 ;
      RECT 0.036 95.616 235.894 95.688 ;
      RECT 0.036 96.192 235.894 96.264 ;
      RECT 0.036 96.768 235.894 96.840 ;
      RECT 0.036 97.344 235.894 97.416 ;
      RECT 0.036 97.920 235.894 97.992 ;
      RECT 0.036 98.496 235.894 98.568 ;
      RECT 0.036 99.072 235.894 99.144 ;
      RECT 0.036 99.648 235.894 99.720 ;
      RECT 0.036 100.224 235.894 100.296 ;
      RECT 0.036 100.800 235.894 100.872 ;
      RECT 0.036 101.376 235.894 101.448 ;
      RECT 0.036 101.952 235.894 102.024 ;
      RECT 0.036 102.528 235.894 102.600 ;
      RECT 0.036 103.104 235.894 103.176 ;
      RECT 0.036 103.680 235.894 103.752 ;
      RECT 0.036 104.256 235.894 104.328 ;
      RECT 0.036 104.832 235.894 104.904 ;
      RECT 0.036 105.408 235.894 105.480 ;
      RECT 0.036 105.984 235.894 106.056 ;
      RECT 0.036 106.560 235.894 106.632 ;
      RECT 0.036 107.136 235.894 107.208 ;
      RECT 0.036 107.712 235.894 107.784 ;
      RECT 0.036 108.288 235.894 108.360 ;
      RECT 0.036 108.864 235.894 108.936 ;
      RECT 0.036 109.440 235.894 109.512 ;
      RECT 0.036 110.016 235.894 110.088 ;
      RECT 0.036 110.592 235.894 110.664 ;
      RECT 0.036 111.168 235.894 111.240 ;
      RECT 0.036 111.744 235.894 111.816 ;
      RECT 0.036 112.320 235.894 112.392 ;
      RECT 0.036 112.896 235.894 112.968 ;
      RECT 0.036 113.472 235.894 113.544 ;
      RECT 0.036 114.048 235.894 114.120 ;
      RECT 0.036 114.624 235.894 114.696 ;
      RECT 0.036 115.200 235.894 115.272 ;
      RECT 0.036 115.776 235.894 115.848 ;
      RECT 0.036 116.352 235.894 116.424 ;
      RECT 0.036 116.928 235.894 117.000 ;
      RECT 0.036 117.504 235.894 117.576 ;
      RECT 0.036 118.080 235.894 118.152 ;
      RECT 0.036 118.656 235.894 118.728 ;
      RECT 0.036 119.232 235.894 119.304 ;
      RECT 0.036 119.808 235.894 119.880 ;
      RECT 0.036 120.384 235.894 120.456 ;
      RECT 0.036 120.960 235.894 121.032 ;
      RECT 0.036 121.536 235.894 121.608 ;
      RECT 0.036 122.112 235.894 122.184 ;
      RECT 0.036 122.688 235.894 122.760 ;
      RECT 0.036 123.264 235.894 123.336 ;
      RECT 0.036 123.840 235.894 123.912 ;
      RECT 0.036 124.416 235.894 124.488 ;
      RECT 0.036 124.992 235.894 125.064 ;
      RECT 0.036 125.568 235.894 125.640 ;
      RECT 0.036 126.144 235.894 126.216 ;
      RECT 0.036 126.720 235.894 126.792 ;
      RECT 0.036 127.296 235.894 127.368 ;
      RECT 0.036 127.872 235.894 127.944 ;
      RECT 0.036 128.448 235.894 128.520 ;
      RECT 0.036 129.024 235.894 129.096 ;
      RECT 0.036 129.600 235.894 129.672 ;
      RECT 0.036 130.176 235.894 130.248 ;
      RECT 0.036 130.752 235.894 130.824 ;
      RECT 0.036 131.328 235.894 131.400 ;
      RECT 0.036 131.904 235.894 131.976 ;
      RECT 0.036 132.480 235.894 132.552 ;
      RECT 0.036 133.056 235.894 133.128 ;
      RECT 0.036 133.632 235.894 133.704 ;
      RECT 0.036 134.208 235.894 134.280 ;
      RECT 0.036 134.784 235.894 134.856 ;
      RECT 0.036 135.360 235.894 135.432 ;
      RECT 0.036 135.936 235.894 136.008 ;
      RECT 0.036 136.512 235.894 136.584 ;
      RECT 0.036 137.088 235.894 137.160 ;
      RECT 0.036 137.664 235.894 137.736 ;
      RECT 0.036 138.240 235.894 138.312 ;
      RECT 0.036 138.816 235.894 138.888 ;
      RECT 0.036 139.392 235.894 139.464 ;
      RECT 0.036 139.968 235.894 140.040 ;
      RECT 0.036 140.544 235.894 140.616 ;
      RECT 0.036 141.120 235.894 141.192 ;
      RECT 0.036 141.696 235.894 141.768 ;
      RECT 0.036 142.272 235.894 142.344 ;
      RECT 0.036 142.848 235.894 142.920 ;
      RECT 0.036 143.424 235.894 143.496 ;
      RECT 0.036 144.000 235.894 144.072 ;
      RECT 0.036 144.576 235.894 144.648 ;
      RECT 0.036 145.152 235.894 145.224 ;
      RECT 0.036 145.728 235.894 145.800 ;
      RECT 0.036 146.304 235.894 146.376 ;
      RECT 0.036 146.880 235.894 146.952 ;
      RECT 0.036 147.456 235.894 147.528 ;
      RECT 0.036 148.032 235.894 148.104 ;
      RECT 0.036 148.608 235.894 148.680 ;
      RECT 0.036 149.184 235.894 149.256 ;
      RECT 0.036 149.760 235.894 149.832 ;
      RECT 0.036 150.336 235.894 150.408 ;
      RECT 0.036 150.912 235.894 150.984 ;
      RECT 0.036 151.488 235.894 151.560 ;
      RECT 0.036 152.064 235.894 152.136 ;
      RECT 0.036 152.640 235.894 152.712 ;
      RECT 0.036 153.216 235.894 153.288 ;
      RECT 0.036 153.792 235.894 153.864 ;
      RECT 0.036 154.368 235.894 154.440 ;
      RECT 0.036 154.944 235.894 155.016 ;
      RECT 0.036 155.520 235.894 155.592 ;
      RECT 0.036 156.096 235.894 156.168 ;
      RECT 0.036 156.672 235.894 156.744 ;
      RECT 0.036 157.248 235.894 157.320 ;
      RECT 0.036 157.824 235.894 157.896 ;
      RECT 0.036 158.400 235.894 158.472 ;
      RECT 0.036 158.976 235.894 159.048 ;
      RECT 0.036 159.552 235.894 159.624 ;
      RECT 0.036 160.128 235.894 160.200 ;
      RECT 0.036 160.704 235.894 160.776 ;
      RECT 0.036 161.280 235.894 161.352 ;
      RECT 0.036 161.856 235.894 161.928 ;
      RECT 0.036 162.432 235.894 162.504 ;
      RECT 0.036 163.008 235.894 163.080 ;
      RECT 0.036 163.584 235.894 163.656 ;
      RECT 0.036 164.160 235.894 164.232 ;
      RECT 0.036 164.736 235.894 164.808 ;
      RECT 0.036 165.312 235.894 165.384 ;
      RECT 0.036 165.888 235.894 165.960 ;
      RECT 0.036 166.464 235.894 166.536 ;
      RECT 0.036 167.040 235.894 167.112 ;
      RECT 0.036 167.616 235.894 167.688 ;
      RECT 0.036 168.192 235.894 168.264 ;
      RECT 0.036 168.768 235.894 168.840 ;
      RECT 0.036 169.344 235.894 169.416 ;
      RECT 0.036 169.920 235.894 169.992 ;
      RECT 0.036 170.496 235.894 170.568 ;
      RECT 0.036 171.072 235.894 171.144 ;
      RECT 0.036 171.648 235.894 171.720 ;
      RECT 0.036 172.224 235.894 172.296 ;
      RECT 0.036 172.800 235.894 172.872 ;
      RECT 0.036 173.376 235.894 173.448 ;
      RECT 0.036 173.952 235.894 174.024 ;
      RECT 0.036 174.528 235.894 174.600 ;
      RECT 0.036 175.104 235.894 175.176 ;
      RECT 0.036 175.680 235.894 175.752 ;
      RECT 0.036 176.256 235.894 176.328 ;
      RECT 0.036 176.832 235.894 176.904 ;
      RECT 0.036 177.408 235.894 177.480 ;
      RECT 0.036 177.984 235.894 178.056 ;
      RECT 0.036 178.560 235.894 178.632 ;
      RECT 0.036 179.136 235.894 179.208 ;
      RECT 0.036 179.712 235.894 179.784 ;
      RECT 0.036 180.288 235.894 180.360 ;
      RECT 0.036 180.864 235.894 180.936 ;
      RECT 0.036 181.440 235.894 181.512 ;
      RECT 0.036 182.016 235.894 182.088 ;
      RECT 0.036 182.592 235.894 182.664 ;
      RECT 0.036 183.168 235.894 183.240 ;
      RECT 0.036 183.744 235.894 183.816 ;
      RECT 0.036 184.320 235.894 184.392 ;
      RECT 0.036 184.896 235.894 184.968 ;
      RECT 0.036 185.472 235.894 185.544 ;
      RECT 0.036 186.048 235.894 186.120 ;
      RECT 0.036 186.624 235.894 186.696 ;
      RECT 0.036 187.200 235.894 187.272 ;
      RECT 0.036 187.776 235.894 187.848 ;
      RECT 0.036 188.352 235.894 188.424 ;
      RECT 0.036 188.928 235.894 189.000 ;
      RECT 0.036 189.504 235.894 189.576 ;
      RECT 0.036 190.080 235.894 190.152 ;
      RECT 0.036 190.656 235.894 190.728 ;
      RECT 0.036 191.232 235.894 191.304 ;
      RECT 0.036 191.808 235.894 191.880 ;
      RECT 0.036 192.384 235.894 192.456 ;
      RECT 0.036 192.960 235.894 193.032 ;
      RECT 0.036 193.536 235.894 193.608 ;
      RECT 0.036 194.112 235.894 194.184 ;
      RECT 0.036 194.688 235.894 194.760 ;
      RECT 0.036 195.264 235.894 195.336 ;
      RECT 0.036 195.840 235.894 195.912 ;
      RECT 0.036 196.416 235.894 196.488 ;
      RECT 0.036 196.992 235.894 197.064 ;
      RECT 0.036 197.568 235.894 197.640 ;
      RECT 0.036 198.144 235.894 198.216 ;
      RECT 0.036 198.720 235.894 198.792 ;
      RECT 0.036 199.296 235.894 199.368 ;
      RECT 0.036 199.872 235.894 199.944 ;
      RECT 0.036 200.448 235.894 200.520 ;
      RECT 0.036 201.024 235.894 201.096 ;
      RECT 0.036 201.600 235.894 201.672 ;
      RECT 0.036 202.176 235.894 202.248 ;
      RECT 0.036 202.752 235.894 202.824 ;
      RECT 0.036 203.328 235.894 203.400 ;
      RECT 0.036 203.904 235.894 203.976 ;
      RECT 0.036 204.480 235.894 204.552 ;
      RECT 0.036 205.056 235.894 205.128 ;
      RECT 0.036 205.632 235.894 205.704 ;
      RECT 0.036 206.208 235.894 206.280 ;
      RECT 0.036 206.784 235.894 206.856 ;
      RECT 0.036 207.360 235.894 207.432 ;
      RECT 0.036 207.936 235.894 208.008 ;
      RECT 0.036 208.512 235.894 208.584 ;
      RECT 0.036 209.088 235.894 209.160 ;
      RECT 0.036 209.664 235.894 209.736 ;
      RECT 0.036 210.240 235.894 210.312 ;
      RECT 0.036 210.816 235.894 210.888 ;
      RECT 0.036 211.392 235.894 211.464 ;
      RECT 0.036 211.968 235.894 212.040 ;
      RECT 0.036 212.544 235.894 212.616 ;
      RECT 0.036 213.120 235.894 213.192 ;
      RECT 0.036 213.696 235.894 213.768 ;
      RECT 0.036 214.272 235.894 214.344 ;
      RECT 0.036 214.848 235.894 214.920 ;
      RECT 0.036 215.424 235.894 215.496 ;
      RECT 0.036 216.000 235.894 216.072 ;
      RECT 0.036 216.576 235.894 216.648 ;
      RECT 0.036 217.152 235.894 217.224 ;
      RECT 0.036 217.728 235.894 217.800 ;
      RECT 0.036 218.304 235.894 218.376 ;
      RECT 0.036 218.880 235.894 218.952 ;
      RECT 0.036 219.456 235.894 219.528 ;
      RECT 0.036 220.032 235.894 220.104 ;
      RECT 0.036 220.608 235.894 220.680 ;
      RECT 0.036 221.184 235.894 221.256 ;
      RECT 0.036 221.760 235.894 221.832 ;
      RECT 0.036 222.336 235.894 222.408 ;
      RECT 0.036 222.912 235.894 222.984 ;
      RECT 0.036 223.488 235.894 223.560 ;
      RECT 0.036 224.064 235.894 224.136 ;
      RECT 0.036 224.640 235.894 224.712 ;
      RECT 0.036 225.216 235.894 225.288 ;
      RECT 0.036 225.792 235.894 225.864 ;
      RECT 0.036 226.368 235.894 226.440 ;
      RECT 0.036 226.944 235.894 227.016 ;
      RECT 0.036 227.520 235.894 227.592 ;
      RECT 0.036 228.096 235.894 228.168 ;
      RECT 0.036 228.672 235.894 228.744 ;
      RECT 0.036 229.248 235.894 229.320 ;
      RECT 0.036 229.824 235.894 229.896 ;
      RECT 0.036 230.400 235.894 230.472 ;
      RECT 0.036 230.976 235.894 231.048 ;
      RECT 0.036 231.552 235.894 231.624 ;
      RECT 0.036 232.128 235.894 232.200 ;
      RECT 0.036 232.704 235.894 232.776 ;
      RECT 0.036 233.280 235.894 233.352 ;
      RECT 0.036 233.856 235.894 233.928 ;
      RECT 0.036 234.432 235.894 234.504 ;
      RECT 0.036 235.008 235.894 235.080 ;
      RECT 0.036 235.584 235.894 235.656 ;
      RECT 0.036 236.160 235.894 236.232 ;
      RECT 0.036 236.736 235.894 236.808 ;
      RECT 0.036 237.312 235.894 237.384 ;
      RECT 0.036 237.888 235.894 237.960 ;
      RECT 0.036 238.464 235.894 238.536 ;
      RECT 0.036 239.040 235.894 239.112 ;
      RECT 0.036 239.616 235.894 239.688 ;
      RECT 0.036 240.192 235.894 240.264 ;
      RECT 0.036 240.768 235.894 240.840 ;
      RECT 0.036 241.344 235.894 241.416 ;
      RECT 0.036 241.920 235.894 241.992 ;
      RECT 0.036 242.496 235.894 242.568 ;
      RECT 0.036 243.072 235.894 243.144 ;
      RECT 0.036 243.648 235.894 243.720 ;
      RECT 0.036 244.224 235.894 244.296 ;
      RECT 0.036 244.800 235.894 244.872 ;
      RECT 0.036 245.376 235.894 245.448 ;
      RECT 0.036 245.952 235.894 246.024 ;
      RECT 0.036 246.528 235.894 246.600 ;
      RECT 0.036 247.104 235.894 247.176 ;
      RECT 0.036 247.680 235.894 247.752 ;
      RECT 0.036 248.256 235.894 248.328 ;
      RECT 0.036 248.832 235.894 248.904 ;
      RECT 0.036 249.408 235.894 249.480 ;
      RECT 0.036 249.984 235.894 250.056 ;
      RECT 0.036 250.560 235.894 250.632 ;
      RECT 0.036 251.136 235.894 251.208 ;
      RECT 0.036 251.712 235.894 251.784 ;
      RECT 0.036 252.288 235.894 252.360 ;
      RECT 0.036 252.864 235.894 252.936 ;
      RECT 0.036 253.440 235.894 253.512 ;
      RECT 0.036 254.016 235.894 254.088 ;
      RECT 0.036 254.592 235.894 254.664 ;
      RECT 0.036 255.168 235.894 255.240 ;
      RECT 0.036 255.744 235.894 255.816 ;
      RECT 0.036 256.320 235.894 256.392 ;
      RECT 0.036 256.896 235.894 256.968 ;
      RECT 0.036 257.472 235.894 257.544 ;
      RECT 0.036 258.048 235.894 258.120 ;
      RECT 0.036 258.624 235.894 258.696 ;
      RECT 0.036 259.200 235.894 259.272 ;
      RECT 0.036 259.776 235.894 259.848 ;
      RECT 0.036 260.352 235.894 260.424 ;
      RECT 0.036 260.928 235.894 261.000 ;
      RECT 0.036 261.504 235.894 261.576 ;
      RECT 0.036 262.080 235.894 262.152 ;
      RECT 0.036 262.656 235.894 262.728 ;
      RECT 0.036 263.232 235.894 263.304 ;
      RECT 0.036 263.808 235.894 263.880 ;
      RECT 0.036 264.384 235.894 264.456 ;
      RECT 0.036 264.960 235.894 265.032 ;
      RECT 0.036 265.536 235.894 265.608 ;
      RECT 0.036 266.112 235.894 266.184 ;
      RECT 0.036 266.688 235.894 266.760 ;
      RECT 0.036 267.264 235.894 267.336 ;
      RECT 0.036 267.840 235.894 267.912 ;
      RECT 0.036 268.416 235.894 268.488 ;
      RECT 0.036 268.992 235.894 269.064 ;
      RECT 0.036 269.568 235.894 269.640 ;
      RECT 0.036 270.144 235.894 270.216 ;
      RECT 0.036 270.720 235.894 270.792 ;
      RECT 0.036 271.296 235.894 271.368 ;
      RECT 0.036 271.872 235.894 271.944 ;
      RECT 0.036 272.448 235.894 272.520 ;
      RECT 0.036 273.024 235.894 273.096 ;
      RECT 0.036 273.600 235.894 273.672 ;
      RECT 0.036 274.176 235.894 274.248 ;
      RECT 0.036 274.752 235.894 274.824 ;
      RECT 0.036 275.328 235.894 275.400 ;
      RECT 0.036 275.904 235.894 275.976 ;
      RECT 0.036 276.480 235.894 276.552 ;
      RECT 0.036 277.056 235.894 277.128 ;
      RECT 0.036 277.632 235.894 277.704 ;
      RECT 0.036 278.208 235.894 278.280 ;
      RECT 0.036 278.784 235.894 278.856 ;
      RECT 0.036 279.360 235.894 279.432 ;
      RECT 0.036 279.936 235.894 280.008 ;
      RECT 0.036 280.512 235.894 280.584 ;
      RECT 0.036 281.088 235.894 281.160 ;
      RECT 0.036 281.664 235.894 281.736 ;
      RECT 0.036 282.240 235.894 282.312 ;
      RECT 0.036 282.816 235.894 282.888 ;
      RECT 0.036 283.392 235.894 283.464 ;
      RECT 0.036 283.968 235.894 284.040 ;
      RECT 0.036 284.544 235.894 284.616 ;
      RECT 0.036 285.120 235.894 285.192 ;
      RECT 0.036 285.696 235.894 285.768 ;
      RECT 0.036 286.272 235.894 286.344 ;
      RECT 0.036 286.848 235.894 286.920 ;
      RECT 0.036 287.424 235.894 287.496 ;
      RECT 0.036 288.000 235.894 288.072 ;
      RECT 0.036 288.576 235.894 288.648 ;
      RECT 0.036 289.152 235.894 289.224 ;
      RECT 0.036 289.728 235.894 289.800 ;
      RECT 0.036 290.304 235.894 290.376 ;
      RECT 0.036 290.880 235.894 290.952 ;
      RECT 0.036 291.456 235.894 291.528 ;
      RECT 0.036 292.032 235.894 292.104 ;
      RECT 0.036 292.608 235.894 292.680 ;
      RECT 0.036 293.184 235.894 293.256 ;
      RECT 0.036 293.760 235.894 293.832 ;
      RECT 0.036 294.336 235.894 294.408 ;
    END
  END VSS
  PIN VDD
    DIRECTION INOUT ;
    USE POWER ;
    PORT
      LAYER M4 ;
      RECT 0.036 0.288 235.894 0.360 ;
      RECT 0.036 0.864 235.894 0.936 ;
      RECT 0.036 1.440 235.894 1.512 ;
      RECT 0.036 2.016 235.894 2.088 ;
      RECT 0.036 2.592 235.894 2.664 ;
      RECT 0.036 3.168 235.894 3.240 ;
      RECT 0.036 3.744 235.894 3.816 ;
      RECT 0.036 4.320 235.894 4.392 ;
      RECT 0.036 4.896 235.894 4.968 ;
      RECT 0.036 5.472 235.894 5.544 ;
      RECT 0.036 6.048 235.894 6.120 ;
      RECT 0.036 6.624 235.894 6.696 ;
      RECT 0.036 7.200 235.894 7.272 ;
      RECT 0.036 7.776 235.894 7.848 ;
      RECT 0.036 8.352 235.894 8.424 ;
      RECT 0.036 8.928 235.894 9.000 ;
      RECT 0.036 9.504 235.894 9.576 ;
      RECT 0.036 10.080 235.894 10.152 ;
      RECT 0.036 10.656 235.894 10.728 ;
      RECT 0.036 11.232 235.894 11.304 ;
      RECT 0.036 11.808 235.894 11.880 ;
      RECT 0.036 12.384 235.894 12.456 ;
      RECT 0.036 12.960 235.894 13.032 ;
      RECT 0.036 13.536 235.894 13.608 ;
      RECT 0.036 14.112 235.894 14.184 ;
      RECT 0.036 14.688 235.894 14.760 ;
      RECT 0.036 15.264 235.894 15.336 ;
      RECT 0.036 15.840 235.894 15.912 ;
      RECT 0.036 16.416 235.894 16.488 ;
      RECT 0.036 16.992 235.894 17.064 ;
      RECT 0.036 17.568 235.894 17.640 ;
      RECT 0.036 18.144 235.894 18.216 ;
      RECT 0.036 18.720 235.894 18.792 ;
      RECT 0.036 19.296 235.894 19.368 ;
      RECT 0.036 19.872 235.894 19.944 ;
      RECT 0.036 20.448 235.894 20.520 ;
      RECT 0.036 21.024 235.894 21.096 ;
      RECT 0.036 21.600 235.894 21.672 ;
      RECT 0.036 22.176 235.894 22.248 ;
      RECT 0.036 22.752 235.894 22.824 ;
      RECT 0.036 23.328 235.894 23.400 ;
      RECT 0.036 23.904 235.894 23.976 ;
      RECT 0.036 24.480 235.894 24.552 ;
      RECT 0.036 25.056 235.894 25.128 ;
      RECT 0.036 25.632 235.894 25.704 ;
      RECT 0.036 26.208 235.894 26.280 ;
      RECT 0.036 26.784 235.894 26.856 ;
      RECT 0.036 27.360 235.894 27.432 ;
      RECT 0.036 27.936 235.894 28.008 ;
      RECT 0.036 28.512 235.894 28.584 ;
      RECT 0.036 29.088 235.894 29.160 ;
      RECT 0.036 29.664 235.894 29.736 ;
      RECT 0.036 30.240 235.894 30.312 ;
      RECT 0.036 30.816 235.894 30.888 ;
      RECT 0.036 31.392 235.894 31.464 ;
      RECT 0.036 31.968 235.894 32.040 ;
      RECT 0.036 32.544 235.894 32.616 ;
      RECT 0.036 33.120 235.894 33.192 ;
      RECT 0.036 33.696 235.894 33.768 ;
      RECT 0.036 34.272 235.894 34.344 ;
      RECT 0.036 34.848 235.894 34.920 ;
      RECT 0.036 35.424 235.894 35.496 ;
      RECT 0.036 36.000 235.894 36.072 ;
      RECT 0.036 36.576 235.894 36.648 ;
      RECT 0.036 37.152 235.894 37.224 ;
      RECT 0.036 37.728 235.894 37.800 ;
      RECT 0.036 38.304 235.894 38.376 ;
      RECT 0.036 38.880 235.894 38.952 ;
      RECT 0.036 39.456 235.894 39.528 ;
      RECT 0.036 40.032 235.894 40.104 ;
      RECT 0.036 40.608 235.894 40.680 ;
      RECT 0.036 41.184 235.894 41.256 ;
      RECT 0.036 41.760 235.894 41.832 ;
      RECT 0.036 42.336 235.894 42.408 ;
      RECT 0.036 42.912 235.894 42.984 ;
      RECT 0.036 43.488 235.894 43.560 ;
      RECT 0.036 44.064 235.894 44.136 ;
      RECT 0.036 44.640 235.894 44.712 ;
      RECT 0.036 45.216 235.894 45.288 ;
      RECT 0.036 45.792 235.894 45.864 ;
      RECT 0.036 46.368 235.894 46.440 ;
      RECT 0.036 46.944 235.894 47.016 ;
      RECT 0.036 47.520 235.894 47.592 ;
      RECT 0.036 48.096 235.894 48.168 ;
      RECT 0.036 48.672 235.894 48.744 ;
      RECT 0.036 49.248 235.894 49.320 ;
      RECT 0.036 49.824 235.894 49.896 ;
      RECT 0.036 50.400 235.894 50.472 ;
      RECT 0.036 50.976 235.894 51.048 ;
      RECT 0.036 51.552 235.894 51.624 ;
      RECT 0.036 52.128 235.894 52.200 ;
      RECT 0.036 52.704 235.894 52.776 ;
      RECT 0.036 53.280 235.894 53.352 ;
      RECT 0.036 53.856 235.894 53.928 ;
      RECT 0.036 54.432 235.894 54.504 ;
      RECT 0.036 55.008 235.894 55.080 ;
      RECT 0.036 55.584 235.894 55.656 ;
      RECT 0.036 56.160 235.894 56.232 ;
      RECT 0.036 56.736 235.894 56.808 ;
      RECT 0.036 57.312 235.894 57.384 ;
      RECT 0.036 57.888 235.894 57.960 ;
      RECT 0.036 58.464 235.894 58.536 ;
      RECT 0.036 59.040 235.894 59.112 ;
      RECT 0.036 59.616 235.894 59.688 ;
      RECT 0.036 60.192 235.894 60.264 ;
      RECT 0.036 60.768 235.894 60.840 ;
      RECT 0.036 61.344 235.894 61.416 ;
      RECT 0.036 61.920 235.894 61.992 ;
      RECT 0.036 62.496 235.894 62.568 ;
      RECT 0.036 63.072 235.894 63.144 ;
      RECT 0.036 63.648 235.894 63.720 ;
      RECT 0.036 64.224 235.894 64.296 ;
      RECT 0.036 64.800 235.894 64.872 ;
      RECT 0.036 65.376 235.894 65.448 ;
      RECT 0.036 65.952 235.894 66.024 ;
      RECT 0.036 66.528 235.894 66.600 ;
      RECT 0.036 67.104 235.894 67.176 ;
      RECT 0.036 67.680 235.894 67.752 ;
      RECT 0.036 68.256 235.894 68.328 ;
      RECT 0.036 68.832 235.894 68.904 ;
      RECT 0.036 69.408 235.894 69.480 ;
      RECT 0.036 69.984 235.894 70.056 ;
      RECT 0.036 70.560 235.894 70.632 ;
      RECT 0.036 71.136 235.894 71.208 ;
      RECT 0.036 71.712 235.894 71.784 ;
      RECT 0.036 72.288 235.894 72.360 ;
      RECT 0.036 72.864 235.894 72.936 ;
      RECT 0.036 73.440 235.894 73.512 ;
      RECT 0.036 74.016 235.894 74.088 ;
      RECT 0.036 74.592 235.894 74.664 ;
      RECT 0.036 75.168 235.894 75.240 ;
      RECT 0.036 75.744 235.894 75.816 ;
      RECT 0.036 76.320 235.894 76.392 ;
      RECT 0.036 76.896 235.894 76.968 ;
      RECT 0.036 77.472 235.894 77.544 ;
      RECT 0.036 78.048 235.894 78.120 ;
      RECT 0.036 78.624 235.894 78.696 ;
      RECT 0.036 79.200 235.894 79.272 ;
      RECT 0.036 79.776 235.894 79.848 ;
      RECT 0.036 80.352 235.894 80.424 ;
      RECT 0.036 80.928 235.894 81.000 ;
      RECT 0.036 81.504 235.894 81.576 ;
      RECT 0.036 82.080 235.894 82.152 ;
      RECT 0.036 82.656 235.894 82.728 ;
      RECT 0.036 83.232 235.894 83.304 ;
      RECT 0.036 83.808 235.894 83.880 ;
      RECT 0.036 84.384 235.894 84.456 ;
      RECT 0.036 84.960 235.894 85.032 ;
      RECT 0.036 85.536 235.894 85.608 ;
      RECT 0.036 86.112 235.894 86.184 ;
      RECT 0.036 86.688 235.894 86.760 ;
      RECT 0.036 87.264 235.894 87.336 ;
      RECT 0.036 87.840 235.894 87.912 ;
      RECT 0.036 88.416 235.894 88.488 ;
      RECT 0.036 88.992 235.894 89.064 ;
      RECT 0.036 89.568 235.894 89.640 ;
      RECT 0.036 90.144 235.894 90.216 ;
      RECT 0.036 90.720 235.894 90.792 ;
      RECT 0.036 91.296 235.894 91.368 ;
      RECT 0.036 91.872 235.894 91.944 ;
      RECT 0.036 92.448 235.894 92.520 ;
      RECT 0.036 93.024 235.894 93.096 ;
      RECT 0.036 93.600 235.894 93.672 ;
      RECT 0.036 94.176 235.894 94.248 ;
      RECT 0.036 94.752 235.894 94.824 ;
      RECT 0.036 95.328 235.894 95.400 ;
      RECT 0.036 95.904 235.894 95.976 ;
      RECT 0.036 96.480 235.894 96.552 ;
      RECT 0.036 97.056 235.894 97.128 ;
      RECT 0.036 97.632 235.894 97.704 ;
      RECT 0.036 98.208 235.894 98.280 ;
      RECT 0.036 98.784 235.894 98.856 ;
      RECT 0.036 99.360 235.894 99.432 ;
      RECT 0.036 99.936 235.894 100.008 ;
      RECT 0.036 100.512 235.894 100.584 ;
      RECT 0.036 101.088 235.894 101.160 ;
      RECT 0.036 101.664 235.894 101.736 ;
      RECT 0.036 102.240 235.894 102.312 ;
      RECT 0.036 102.816 235.894 102.888 ;
      RECT 0.036 103.392 235.894 103.464 ;
      RECT 0.036 103.968 235.894 104.040 ;
      RECT 0.036 104.544 235.894 104.616 ;
      RECT 0.036 105.120 235.894 105.192 ;
      RECT 0.036 105.696 235.894 105.768 ;
      RECT 0.036 106.272 235.894 106.344 ;
      RECT 0.036 106.848 235.894 106.920 ;
      RECT 0.036 107.424 235.894 107.496 ;
      RECT 0.036 108.000 235.894 108.072 ;
      RECT 0.036 108.576 235.894 108.648 ;
      RECT 0.036 109.152 235.894 109.224 ;
      RECT 0.036 109.728 235.894 109.800 ;
      RECT 0.036 110.304 235.894 110.376 ;
      RECT 0.036 110.880 235.894 110.952 ;
      RECT 0.036 111.456 235.894 111.528 ;
      RECT 0.036 112.032 235.894 112.104 ;
      RECT 0.036 112.608 235.894 112.680 ;
      RECT 0.036 113.184 235.894 113.256 ;
      RECT 0.036 113.760 235.894 113.832 ;
      RECT 0.036 114.336 235.894 114.408 ;
      RECT 0.036 114.912 235.894 114.984 ;
      RECT 0.036 115.488 235.894 115.560 ;
      RECT 0.036 116.064 235.894 116.136 ;
      RECT 0.036 116.640 235.894 116.712 ;
      RECT 0.036 117.216 235.894 117.288 ;
      RECT 0.036 117.792 235.894 117.864 ;
      RECT 0.036 118.368 235.894 118.440 ;
      RECT 0.036 118.944 235.894 119.016 ;
      RECT 0.036 119.520 235.894 119.592 ;
      RECT 0.036 120.096 235.894 120.168 ;
      RECT 0.036 120.672 235.894 120.744 ;
      RECT 0.036 121.248 235.894 121.320 ;
      RECT 0.036 121.824 235.894 121.896 ;
      RECT 0.036 122.400 235.894 122.472 ;
      RECT 0.036 122.976 235.894 123.048 ;
      RECT 0.036 123.552 235.894 123.624 ;
      RECT 0.036 124.128 235.894 124.200 ;
      RECT 0.036 124.704 235.894 124.776 ;
      RECT 0.036 125.280 235.894 125.352 ;
      RECT 0.036 125.856 235.894 125.928 ;
      RECT 0.036 126.432 235.894 126.504 ;
      RECT 0.036 127.008 235.894 127.080 ;
      RECT 0.036 127.584 235.894 127.656 ;
      RECT 0.036 128.160 235.894 128.232 ;
      RECT 0.036 128.736 235.894 128.808 ;
      RECT 0.036 129.312 235.894 129.384 ;
      RECT 0.036 129.888 235.894 129.960 ;
      RECT 0.036 130.464 235.894 130.536 ;
      RECT 0.036 131.040 235.894 131.112 ;
      RECT 0.036 131.616 235.894 131.688 ;
      RECT 0.036 132.192 235.894 132.264 ;
      RECT 0.036 132.768 235.894 132.840 ;
      RECT 0.036 133.344 235.894 133.416 ;
      RECT 0.036 133.920 235.894 133.992 ;
      RECT 0.036 134.496 235.894 134.568 ;
      RECT 0.036 135.072 235.894 135.144 ;
      RECT 0.036 135.648 235.894 135.720 ;
      RECT 0.036 136.224 235.894 136.296 ;
      RECT 0.036 136.800 235.894 136.872 ;
      RECT 0.036 137.376 235.894 137.448 ;
      RECT 0.036 137.952 235.894 138.024 ;
      RECT 0.036 138.528 235.894 138.600 ;
      RECT 0.036 139.104 235.894 139.176 ;
      RECT 0.036 139.680 235.894 139.752 ;
      RECT 0.036 140.256 235.894 140.328 ;
      RECT 0.036 140.832 235.894 140.904 ;
      RECT 0.036 141.408 235.894 141.480 ;
      RECT 0.036 141.984 235.894 142.056 ;
      RECT 0.036 142.560 235.894 142.632 ;
      RECT 0.036 143.136 235.894 143.208 ;
      RECT 0.036 143.712 235.894 143.784 ;
      RECT 0.036 144.288 235.894 144.360 ;
      RECT 0.036 144.864 235.894 144.936 ;
      RECT 0.036 145.440 235.894 145.512 ;
      RECT 0.036 146.016 235.894 146.088 ;
      RECT 0.036 146.592 235.894 146.664 ;
      RECT 0.036 147.168 235.894 147.240 ;
      RECT 0.036 147.744 235.894 147.816 ;
      RECT 0.036 148.320 235.894 148.392 ;
      RECT 0.036 148.896 235.894 148.968 ;
      RECT 0.036 149.472 235.894 149.544 ;
      RECT 0.036 150.048 235.894 150.120 ;
      RECT 0.036 150.624 235.894 150.696 ;
      RECT 0.036 151.200 235.894 151.272 ;
      RECT 0.036 151.776 235.894 151.848 ;
      RECT 0.036 152.352 235.894 152.424 ;
      RECT 0.036 152.928 235.894 153.000 ;
      RECT 0.036 153.504 235.894 153.576 ;
      RECT 0.036 154.080 235.894 154.152 ;
      RECT 0.036 154.656 235.894 154.728 ;
      RECT 0.036 155.232 235.894 155.304 ;
      RECT 0.036 155.808 235.894 155.880 ;
      RECT 0.036 156.384 235.894 156.456 ;
      RECT 0.036 156.960 235.894 157.032 ;
      RECT 0.036 157.536 235.894 157.608 ;
      RECT 0.036 158.112 235.894 158.184 ;
      RECT 0.036 158.688 235.894 158.760 ;
      RECT 0.036 159.264 235.894 159.336 ;
      RECT 0.036 159.840 235.894 159.912 ;
      RECT 0.036 160.416 235.894 160.488 ;
      RECT 0.036 160.992 235.894 161.064 ;
      RECT 0.036 161.568 235.894 161.640 ;
      RECT 0.036 162.144 235.894 162.216 ;
      RECT 0.036 162.720 235.894 162.792 ;
      RECT 0.036 163.296 235.894 163.368 ;
      RECT 0.036 163.872 235.894 163.944 ;
      RECT 0.036 164.448 235.894 164.520 ;
      RECT 0.036 165.024 235.894 165.096 ;
      RECT 0.036 165.600 235.894 165.672 ;
      RECT 0.036 166.176 235.894 166.248 ;
      RECT 0.036 166.752 235.894 166.824 ;
      RECT 0.036 167.328 235.894 167.400 ;
      RECT 0.036 167.904 235.894 167.976 ;
      RECT 0.036 168.480 235.894 168.552 ;
      RECT 0.036 169.056 235.894 169.128 ;
      RECT 0.036 169.632 235.894 169.704 ;
      RECT 0.036 170.208 235.894 170.280 ;
      RECT 0.036 170.784 235.894 170.856 ;
      RECT 0.036 171.360 235.894 171.432 ;
      RECT 0.036 171.936 235.894 172.008 ;
      RECT 0.036 172.512 235.894 172.584 ;
      RECT 0.036 173.088 235.894 173.160 ;
      RECT 0.036 173.664 235.894 173.736 ;
      RECT 0.036 174.240 235.894 174.312 ;
      RECT 0.036 174.816 235.894 174.888 ;
      RECT 0.036 175.392 235.894 175.464 ;
      RECT 0.036 175.968 235.894 176.040 ;
      RECT 0.036 176.544 235.894 176.616 ;
      RECT 0.036 177.120 235.894 177.192 ;
      RECT 0.036 177.696 235.894 177.768 ;
      RECT 0.036 178.272 235.894 178.344 ;
      RECT 0.036 178.848 235.894 178.920 ;
      RECT 0.036 179.424 235.894 179.496 ;
      RECT 0.036 180.000 235.894 180.072 ;
      RECT 0.036 180.576 235.894 180.648 ;
      RECT 0.036 181.152 235.894 181.224 ;
      RECT 0.036 181.728 235.894 181.800 ;
      RECT 0.036 182.304 235.894 182.376 ;
      RECT 0.036 182.880 235.894 182.952 ;
      RECT 0.036 183.456 235.894 183.528 ;
      RECT 0.036 184.032 235.894 184.104 ;
      RECT 0.036 184.608 235.894 184.680 ;
      RECT 0.036 185.184 235.894 185.256 ;
      RECT 0.036 185.760 235.894 185.832 ;
      RECT 0.036 186.336 235.894 186.408 ;
      RECT 0.036 186.912 235.894 186.984 ;
      RECT 0.036 187.488 235.894 187.560 ;
      RECT 0.036 188.064 235.894 188.136 ;
      RECT 0.036 188.640 235.894 188.712 ;
      RECT 0.036 189.216 235.894 189.288 ;
      RECT 0.036 189.792 235.894 189.864 ;
      RECT 0.036 190.368 235.894 190.440 ;
      RECT 0.036 190.944 235.894 191.016 ;
      RECT 0.036 191.520 235.894 191.592 ;
      RECT 0.036 192.096 235.894 192.168 ;
      RECT 0.036 192.672 235.894 192.744 ;
      RECT 0.036 193.248 235.894 193.320 ;
      RECT 0.036 193.824 235.894 193.896 ;
      RECT 0.036 194.400 235.894 194.472 ;
      RECT 0.036 194.976 235.894 195.048 ;
      RECT 0.036 195.552 235.894 195.624 ;
      RECT 0.036 196.128 235.894 196.200 ;
      RECT 0.036 196.704 235.894 196.776 ;
      RECT 0.036 197.280 235.894 197.352 ;
      RECT 0.036 197.856 235.894 197.928 ;
      RECT 0.036 198.432 235.894 198.504 ;
      RECT 0.036 199.008 235.894 199.080 ;
      RECT 0.036 199.584 235.894 199.656 ;
      RECT 0.036 200.160 235.894 200.232 ;
      RECT 0.036 200.736 235.894 200.808 ;
      RECT 0.036 201.312 235.894 201.384 ;
      RECT 0.036 201.888 235.894 201.960 ;
      RECT 0.036 202.464 235.894 202.536 ;
      RECT 0.036 203.040 235.894 203.112 ;
      RECT 0.036 203.616 235.894 203.688 ;
      RECT 0.036 204.192 235.894 204.264 ;
      RECT 0.036 204.768 235.894 204.840 ;
      RECT 0.036 205.344 235.894 205.416 ;
      RECT 0.036 205.920 235.894 205.992 ;
      RECT 0.036 206.496 235.894 206.568 ;
      RECT 0.036 207.072 235.894 207.144 ;
      RECT 0.036 207.648 235.894 207.720 ;
      RECT 0.036 208.224 235.894 208.296 ;
      RECT 0.036 208.800 235.894 208.872 ;
      RECT 0.036 209.376 235.894 209.448 ;
      RECT 0.036 209.952 235.894 210.024 ;
      RECT 0.036 210.528 235.894 210.600 ;
      RECT 0.036 211.104 235.894 211.176 ;
      RECT 0.036 211.680 235.894 211.752 ;
      RECT 0.036 212.256 235.894 212.328 ;
      RECT 0.036 212.832 235.894 212.904 ;
      RECT 0.036 213.408 235.894 213.480 ;
      RECT 0.036 213.984 235.894 214.056 ;
      RECT 0.036 214.560 235.894 214.632 ;
      RECT 0.036 215.136 235.894 215.208 ;
      RECT 0.036 215.712 235.894 215.784 ;
      RECT 0.036 216.288 235.894 216.360 ;
      RECT 0.036 216.864 235.894 216.936 ;
      RECT 0.036 217.440 235.894 217.512 ;
      RECT 0.036 218.016 235.894 218.088 ;
      RECT 0.036 218.592 235.894 218.664 ;
      RECT 0.036 219.168 235.894 219.240 ;
      RECT 0.036 219.744 235.894 219.816 ;
      RECT 0.036 220.320 235.894 220.392 ;
      RECT 0.036 220.896 235.894 220.968 ;
      RECT 0.036 221.472 235.894 221.544 ;
      RECT 0.036 222.048 235.894 222.120 ;
      RECT 0.036 222.624 235.894 222.696 ;
      RECT 0.036 223.200 235.894 223.272 ;
      RECT 0.036 223.776 235.894 223.848 ;
      RECT 0.036 224.352 235.894 224.424 ;
      RECT 0.036 224.928 235.894 225.000 ;
      RECT 0.036 225.504 235.894 225.576 ;
      RECT 0.036 226.080 235.894 226.152 ;
      RECT 0.036 226.656 235.894 226.728 ;
      RECT 0.036 227.232 235.894 227.304 ;
      RECT 0.036 227.808 235.894 227.880 ;
      RECT 0.036 228.384 235.894 228.456 ;
      RECT 0.036 228.960 235.894 229.032 ;
      RECT 0.036 229.536 235.894 229.608 ;
      RECT 0.036 230.112 235.894 230.184 ;
      RECT 0.036 230.688 235.894 230.760 ;
      RECT 0.036 231.264 235.894 231.336 ;
      RECT 0.036 231.840 235.894 231.912 ;
      RECT 0.036 232.416 235.894 232.488 ;
      RECT 0.036 232.992 235.894 233.064 ;
      RECT 0.036 233.568 235.894 233.640 ;
      RECT 0.036 234.144 235.894 234.216 ;
      RECT 0.036 234.720 235.894 234.792 ;
      RECT 0.036 235.296 235.894 235.368 ;
      RECT 0.036 235.872 235.894 235.944 ;
      RECT 0.036 236.448 235.894 236.520 ;
      RECT 0.036 237.024 235.894 237.096 ;
      RECT 0.036 237.600 235.894 237.672 ;
      RECT 0.036 238.176 235.894 238.248 ;
      RECT 0.036 238.752 235.894 238.824 ;
      RECT 0.036 239.328 235.894 239.400 ;
      RECT 0.036 239.904 235.894 239.976 ;
      RECT 0.036 240.480 235.894 240.552 ;
      RECT 0.036 241.056 235.894 241.128 ;
      RECT 0.036 241.632 235.894 241.704 ;
      RECT 0.036 242.208 235.894 242.280 ;
      RECT 0.036 242.784 235.894 242.856 ;
      RECT 0.036 243.360 235.894 243.432 ;
      RECT 0.036 243.936 235.894 244.008 ;
      RECT 0.036 244.512 235.894 244.584 ;
      RECT 0.036 245.088 235.894 245.160 ;
      RECT 0.036 245.664 235.894 245.736 ;
      RECT 0.036 246.240 235.894 246.312 ;
      RECT 0.036 246.816 235.894 246.888 ;
      RECT 0.036 247.392 235.894 247.464 ;
      RECT 0.036 247.968 235.894 248.040 ;
      RECT 0.036 248.544 235.894 248.616 ;
      RECT 0.036 249.120 235.894 249.192 ;
      RECT 0.036 249.696 235.894 249.768 ;
      RECT 0.036 250.272 235.894 250.344 ;
      RECT 0.036 250.848 235.894 250.920 ;
      RECT 0.036 251.424 235.894 251.496 ;
      RECT 0.036 252.000 235.894 252.072 ;
      RECT 0.036 252.576 235.894 252.648 ;
      RECT 0.036 253.152 235.894 253.224 ;
      RECT 0.036 253.728 235.894 253.800 ;
      RECT 0.036 254.304 235.894 254.376 ;
      RECT 0.036 254.880 235.894 254.952 ;
      RECT 0.036 255.456 235.894 255.528 ;
      RECT 0.036 256.032 235.894 256.104 ;
      RECT 0.036 256.608 235.894 256.680 ;
      RECT 0.036 257.184 235.894 257.256 ;
      RECT 0.036 257.760 235.894 257.832 ;
      RECT 0.036 258.336 235.894 258.408 ;
      RECT 0.036 258.912 235.894 258.984 ;
      RECT 0.036 259.488 235.894 259.560 ;
      RECT 0.036 260.064 235.894 260.136 ;
      RECT 0.036 260.640 235.894 260.712 ;
      RECT 0.036 261.216 235.894 261.288 ;
      RECT 0.036 261.792 235.894 261.864 ;
      RECT 0.036 262.368 235.894 262.440 ;
      RECT 0.036 262.944 235.894 263.016 ;
      RECT 0.036 263.520 235.894 263.592 ;
      RECT 0.036 264.096 235.894 264.168 ;
      RECT 0.036 264.672 235.894 264.744 ;
      RECT 0.036 265.248 235.894 265.320 ;
      RECT 0.036 265.824 235.894 265.896 ;
      RECT 0.036 266.400 235.894 266.472 ;
      RECT 0.036 266.976 235.894 267.048 ;
      RECT 0.036 267.552 235.894 267.624 ;
      RECT 0.036 268.128 235.894 268.200 ;
      RECT 0.036 268.704 235.894 268.776 ;
      RECT 0.036 269.280 235.894 269.352 ;
      RECT 0.036 269.856 235.894 269.928 ;
      RECT 0.036 270.432 235.894 270.504 ;
      RECT 0.036 271.008 235.894 271.080 ;
      RECT 0.036 271.584 235.894 271.656 ;
      RECT 0.036 272.160 235.894 272.232 ;
      RECT 0.036 272.736 235.894 272.808 ;
      RECT 0.036 273.312 235.894 273.384 ;
      RECT 0.036 273.888 235.894 273.960 ;
      RECT 0.036 274.464 235.894 274.536 ;
      RECT 0.036 275.040 235.894 275.112 ;
      RECT 0.036 275.616 235.894 275.688 ;
      RECT 0.036 276.192 235.894 276.264 ;
      RECT 0.036 276.768 235.894 276.840 ;
      RECT 0.036 277.344 235.894 277.416 ;
      RECT 0.036 277.920 235.894 277.992 ;
      RECT 0.036 278.496 235.894 278.568 ;
      RECT 0.036 279.072 235.894 279.144 ;
      RECT 0.036 279.648 235.894 279.720 ;
      RECT 0.036 280.224 235.894 280.296 ;
      RECT 0.036 280.800 235.894 280.872 ;
      RECT 0.036 281.376 235.894 281.448 ;
      RECT 0.036 281.952 235.894 282.024 ;
      RECT 0.036 282.528 235.894 282.600 ;
      RECT 0.036 283.104 235.894 283.176 ;
      RECT 0.036 283.680 235.894 283.752 ;
      RECT 0.036 284.256 235.894 284.328 ;
      RECT 0.036 284.832 235.894 284.904 ;
      RECT 0.036 285.408 235.894 285.480 ;
      RECT 0.036 285.984 235.894 286.056 ;
      RECT 0.036 286.560 235.894 286.632 ;
      RECT 0.036 287.136 235.894 287.208 ;
      RECT 0.036 287.712 235.894 287.784 ;
      RECT 0.036 288.288 235.894 288.360 ;
      RECT 0.036 288.864 235.894 288.936 ;
      RECT 0.036 289.440 235.894 289.512 ;
      RECT 0.036 290.016 235.894 290.088 ;
      RECT 0.036 290.592 235.894 290.664 ;
      RECT 0.036 291.168 235.894 291.240 ;
      RECT 0.036 291.744 235.894 291.816 ;
      RECT 0.036 292.320 235.894 292.392 ;
      RECT 0.036 292.896 235.894 292.968 ;
      RECT 0.036 293.472 235.894 293.544 ;
      RECT 0.036 294.048 235.894 294.120 ;
      RECT 0.036 294.624 235.894 294.696 ;
    END
  END VDD
  OBS
    LAYER M1 ;
    RECT 0 0 235.930 294.912 ;
    LAYER M2 ;
    RECT 0 0 235.930 294.912 ;
    LAYER M3 ;
    RECT 0 0 235.930 294.912 ;
    LAYER M4 ;
    RECT 0 0 235.930 294.912 ;
  END
END mobol_sram_4096x512_1rw

END LIBRARY
